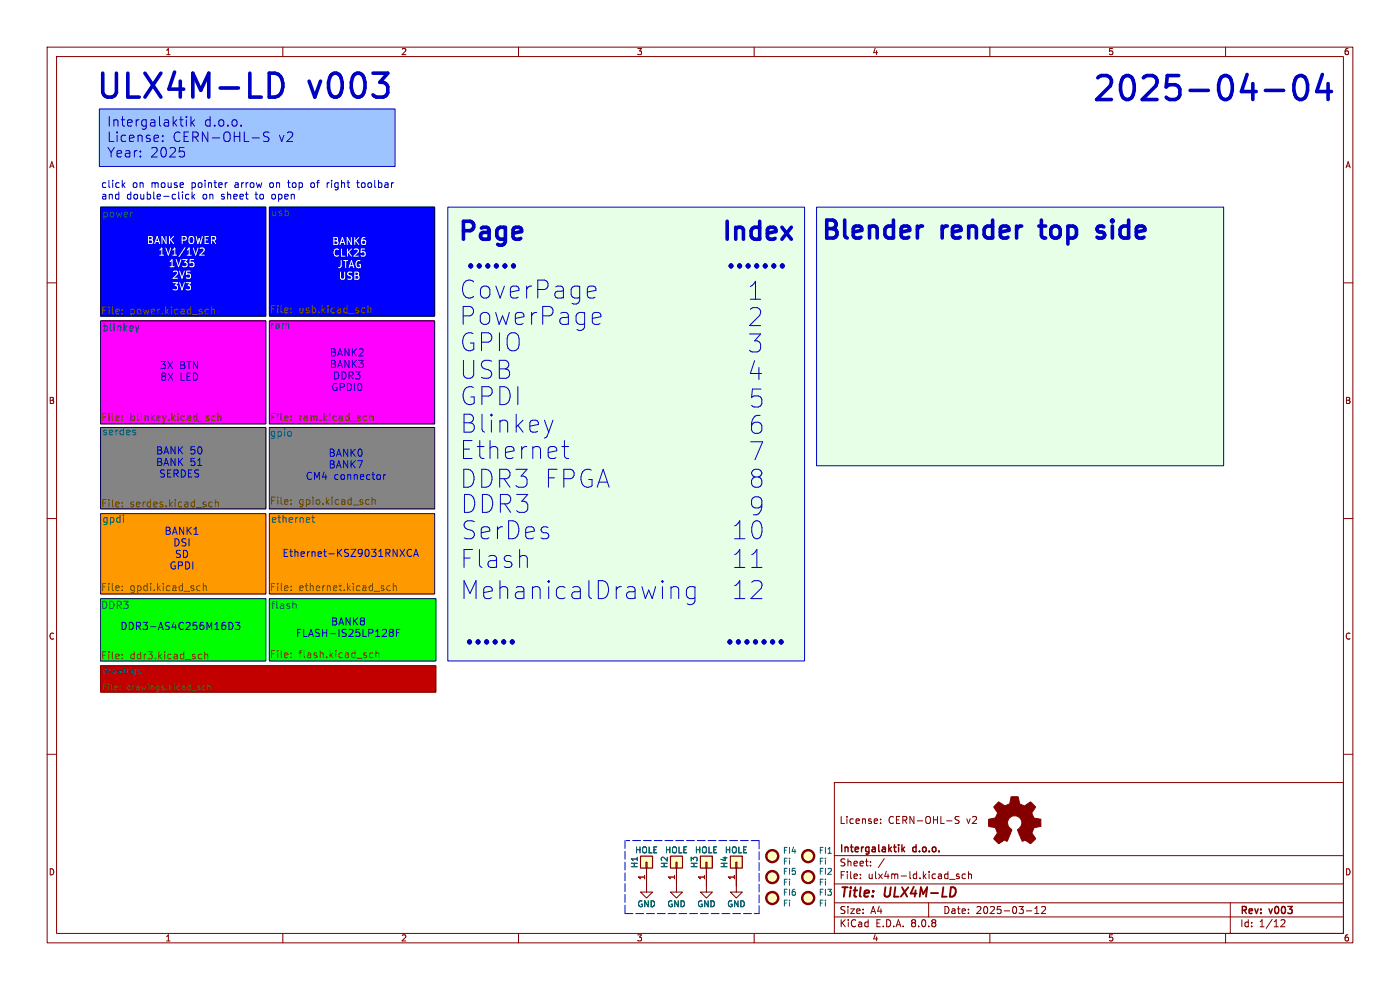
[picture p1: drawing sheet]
<svg xmlns="http://www.w3.org/2000/svg" width="297mm" height="210mm" viewBox="0 0 297 210" stroke-linecap="round" stroke-linejoin="round" font-family="sans-serif">
<defs><g id="words">
<g font-size="7.1" fill="#0000c2">
<text x="20" y="22">ULX4M-LD</text>
<text x="65.5" y="22">v003</text>
<text x="231.3" y="22.5">2025-04-04</text>
</g>
<g font-size="5.3" fill="#0000c2">
<text x="96.6" y="52.1">Page</text>
<text x="166.3" y="52.1">Index</text>
<text x="173.7" y="51.8">Blender</text>
<text x="199.7" y="51.8">render</text>
<text x="222.3" y="51.8">top</text>
<text x="235.8" y="51.8">side</text>
<text x="98.2" y="57.9">......</text>
<text x="153.4" y="57.9">.......</text>
<text x="97.5" y="63.6">CoverPage</text>
<text x="158.6" y="63.9">1</text>
<text x="97.5" y="69.2">PowerPage</text>
<text x="158.6" y="69.4">2</text>
<text x="97.6" y="74.8">GPIO</text>
<text x="158.6" y="75">3</text>
<text x="97.6" y="80.6">USB</text>
<text x="158.6" y="80.9">4</text>
<text x="97.7" y="86.2">GPDI</text>
<text x="158.9" y="86.7">5</text>
<text x="97.7" y="92.1">Blinkey</text>
<text x="158.9" y="92.3">6</text>
<text x="97.6" y="97.6">Ethernet</text>
<text x="158.9" y="97.9">7</text>
<text x="97.6" y="103.7">DDR3 FPGA</text>
<text x="158.9" y="103.7">8</text>
<text x="97.8" y="109.1">DDR3</text>
<text x="158.9" y="109.6">9</text>
<text x="97.9" y="114.7">SerDes</text>
<text x="155.3" y="114.7">10</text>
<text x="97.7" y="120.8">Flash</text>
<text x="155.3" y="120.8">11</text>
<text x="97.7" y="127.4">MehanicalDrawing</text>
<text x="155.3" y="127.4">12</text>
<text x="97.9" y="137.7">......</text>
<text x="153.2" y="137.7">.......</text>
</g>
<g font-size="2.8" fill="#0000c2">
<text x="22.6" y="27.1">Intergalaktik</text>
<text x="43.2" y="27.1">d.o.o.</text>
<text x="22.6" y="30.4">License:</text>
<text x="22.6" y="33.7">Year:</text>
<text x="31.8" y="33.7">2025</text>
<text x="36.5" y="30.4">CERN-OHL-S</text>
<text x="59" y="30.4">v2</text>
</g>
<g font-size="2.8" fill="#840000">
<text x="178" y="190.9">Title:</text>
<text x="187.7" y="190.9">ULX4M-LD</text>
</g>
<g font-size="2.1" fill="#0000c2">
<text x="21.3" y="40">click</text>
<text x="28" y="40">on</text>
<text x="32.1" y="40">mouse</text>
<text x="40.7" y="40">pointer</text>
<text x="50" y="40">arrow</text>
<text x="57.6" y="40">on</text>
<text x="61.7" y="40">top</text>
<text x="66.6" y="40">of</text>
<text x="70.2" y="40">right</text>
<text x="76.8" y="40">toolbar</text>
<text x="21.3" y="42.4">and</text>
<text x="26.8" y="42.4">double-click</text>
<text x="43" y="42.4">on</text>
<text x="47" y="42.4">sheet</text>
<text x="54.5" y="42.4">to</text>
<text x="58" y="42.4">open</text>
<text x="69.9" y="75.8">BANK2</text>
<text x="33.9" y="78.5">3X</text>
<text x="33.9" y="81">8X</text>
<text x="38.1" y="78.5">BTN</text>
<text x="38.1" y="81">LED</text>
<text x="69.9" y="78.3">BANK3</text>
<text x="70.2" y="83.2">GPDI0</text>
<text x="70.6" y="80.7">DDR3</text>
<text x="33" y="96.6">BANK 50</text>
<text x="33" y="99">BANK 51</text>
<text x="33.7" y="101.5">SERDES</text>
<text x="69.6" y="97.1">BANK0</text>
<text x="69.6" y="99.5">BANK7</text>
<text x="64.8" y="102">CM4</text>
<text x="70.8" y="102">connector</text>
<text x="34.8" y="113.6">BANK1</text>
<text x="36.7" y="116.1">DSI</text>
<text x="37" y="118.6">SD</text>
<text x="59.9" y="118.3">Ethernet-KSZ9031RNXCA</text>
<text x="35.9" y="121">GPDI</text>
<text x="25.5" y="133.8">DDR3-AS4C256M16D3</text>
<text x="62.7" y="135.3">FLASH-IS25LP128F</text>
<text x="70.1" y="132.9">BANK8</text>
</g>
<g font-size="2.1" fill="#006464">
<text x="21.6" y="46.2">power</text>
<text x="57.4" y="46">usb</text>
<text x="21.6" y="70.4">blinkey</text>
<text x="57.1" y="69.9">ram</text>
<text x="21.6" y="92.5">serdes</text>
<text x="57.1" y="92.7">gpio</text>
<text x="21.6" y="111">gpdi</text>
<text x="57.4" y="111">ethernet</text>
<text x="21.3" y="129.3">DDR3</text>
<text x="57.4" y="129.3">flash</text>
</g>
<g font-size="2.1" fill="#fff">
<text x="31.1" y="52">BANK POWER</text>
<text x="70.4" y="52.2">BANK6</text>
<text x="33.5" y="54.4">1V1/1V2</text>
<text x="35.7" y="56.9">1V35</text>
<text x="36.4" y="59.3">2V5</text>
<text x="70.5" y="54.6">CLK25</text>
<text x="71.5" y="57.1">JTAG</text>
<text x="71.8" y="59.5">USB</text>
<text x="36.4" y="61.8">3V3</text>
</g>
<g font-size="2.1" fill="#725600">
<text x="21.3" y="67">File:</text>
<text x="27.5" y="67">power.kicad_sch</text>
<text x="57.1" y="66.8">File:</text>
<text x="63.3" y="66.8">usb.kicad_sch</text>
<text x="21.3" y="89.6">File:</text>
<text x="27.5" y="89.6">blinkey.kicad_sch</text>
<text x="57.1" y="89.6">File:</text>
<text x="63.3" y="89.6">ram.kicad_sch</text>
<text x="21.3" y="107.9">File:</text>
<text x="27.5" y="107.9">serdes.kicad_sch</text>
<text x="57.1" y="107.4">File:</text>
<text x="63.3" y="107.4">gpio.kicad_sch</text>
<text x="21.3" y="125.7">File:</text>
<text x="27.5" y="125.7">gpdi.kicad_sch</text>
<text x="57.1" y="125.7">File:</text>
<text x="63.3" y="125.7">ethernet.kicad_sch</text>
<text x="21.3" y="140.2">File:</text>
<text x="27.5" y="140.2">ddr3.kicad_sch</text>
<text x="57.1" y="139.9">File:</text>
<text x="63.3" y="139.9">flash.kicad_sch</text>
</g>
<g font-size="2.1" fill="#840000">
<text x="178" y="175">License:</text>
<text x="188.4" y="175">CERN-OHL-S</text>
<text x="205.1" y="175">v2</text>
<text x="178" y="184">Sheet:</text>
<text x="178" y="181.2">Intergalaktik</text>
<text x="193.7" y="181.2">d.o.o.</text>
<text x="178" y="186.7">File:</text>
<text x="184.1" y="186.7">ulx4m-ld.kicad_sch</text>
<text x="178" y="196.9">KiCad</text>
<text x="178" y="194.1">Size:</text>
<text x="184.7" y="194.1">A4</text>
<text x="185.7" y="196.9">E.D.A.</text>
<text x="193.3" y="196.9">8.0.8</text>
<text x="200" y="194.1">Date:</text>
<text x="207" y="194.1">2025-03-12</text>
<text x="263" y="194.3">Rev:</text>
<text x="263" y="196.9">Id:</text>
<text x="267.1" y="196.9">1/12</text>
<text x="269.4" y="194.3">v003</text>
</g>
<g font-size="1.8" fill="#840000">
<text x="35" y="11.9">1</text>
<text x="85" y="11.9">2</text>
<text x="135" y="11.9">3</text>
<text x="185" y="11.9">4</text>
<text x="235" y="11.9">5</text>
<text x="285" y="11.9">6</text>
<text x="10.3" y="35.9">A</text>
<text x="285.3" y="35.9">A</text>
<text x="10.3" y="85.9">B</text>
<text x="285.3" y="85.9">B</text>
<text x="10.3" y="135.9">C</text>
<text x="285.3" y="135.9">C</text>
<text x="10.3" y="185.9">D</text>
<text x="285.3" y="185.9">D</text>
<text x="35" y="199.9">1</text>
<text x="85" y="199.9">2</text>
<text x="135" y="199.9">3</text>
<text x="185" y="199.9">4</text>
<text x="235" y="199.9">5</text>
<text x="285" y="199.9">6</text>
</g>
<g font-size="1.8" fill="#006464">
<text x="21.6" y="143">drawings</text>
<text x="134.6" y="181.2">HOLE</text>
<text x="135.5" y="184.3" transform="rotate(-90 135.5 184.3)">H1</text>
<text x="141" y="181.2">HOLE</text>
<text x="141.8" y="184.3" transform="rotate(-90 141.8 184.3)">H2</text>
<text x="147.3" y="181.2">HOLE</text>
<text x="148.2" y="184.3" transform="rotate(-90 148.2 184.3)">H3</text>
<text x="153.7" y="181.2">HOLE</text>
<text x="154.5" y="184.3" transform="rotate(-90 154.5 184.3)">H4</text>
<text x="166" y="185.8">FI5</text>
<text x="166" y="181.3">FI4</text>
<text x="166" y="183.6">Fi</text>
<text x="173.6" y="181.3">FI1</text>
<text x="173.6" y="185.8">FI2</text>
<text x="173.6" y="183.6">Fi</text>
<text x="166" y="190.2">FI6</text>
<text x="166" y="188.1">Fi</text>
<text x="173.6" y="190.2">FI3</text>
<text x="173.6" y="188.1">Fi</text>
<text x="135.1" y="192.6">GND</text>
<text x="141.5" y="192.6">GND</text>
<text x="147.8" y="192.6">GND</text>
<text x="154.2" y="192.6">GND</text>
<text x="166" y="192.5">Fi</text>
<text x="173.6" y="192.5">Fi</text>
</g>
<g font-size="1.8" fill="#725600">
<text x="21.6" y="146.8">File:</text>
<text x="26.8" y="146.8">drawings.kicad_sch</text>
</g>
<g font-size="1.8" fill="#a90000">
<text x="136.9" y="186.8" transform="rotate(-90 136.9 186.8)">1</text>
<text x="143.3" y="186.8" transform="rotate(-90 143.3 186.8)">1</text>
<text x="149.6" y="186.8" transform="rotate(-90 149.6 186.8)">1</text>
<text x="156" y="186.8" transform="rotate(-90 156 186.8)">1</text>
</g>
</g></defs>
<g fill="none" stroke="#840000" stroke-width=".21">
<path d="M10 10h277v190h-277zM12 12h273v186h-273zM60 10v2M110 10v2M160 10v2M210 10v2M260 10v2M10 60h2M285 60h2M10 110h2M285 110h2M10 160h2"/>
<path d="M177 166h108v32h-108zM186.8 174.6v.1M186.8 173.8v.1M203.5 173.3l-.6-.1-.2 .1v.5l.6 .3 .2 .3-.3 .3-.6-.1M285 160h2M60 198v2M110 198v2M160 198v2M177 194.5h108M177 191.5h108M177 187.5h108M177 181.5h108"/>
<path d="M182.5 186.3v.1M182.5 185.5v.1M184.7 183.6v.1M184.7 182.8v.1M187.6 182.1l-1.3 2M197 191.5v3M201.5 186.5h1.1M203.5 185.5l-.4-.1-.2 .2 .1 .2 .5 .2v.3h-.6M204.8 185.5l-.4-.1-.3 .3 .1 .6h.6M205.5 185.5l.2-.1 .3 .1 .1 .9M205.5 184.9v1.5M210 198v2"/>
<path d="M217.7 193.2h1.2M219.5 193.8h.9M219.5 192.7l.5-.4v1.5M221 192.4l.5-.1 .3 .4-.9 1.1h.9M260 198v2M261 191.5v6.5M271.7 195.2l.6-.1 .3 .4-.9 1.1h.9"/>
</g>
<path d="M191.3 179.2v1.5M191.9 179.7l-.6 .6M191.5 180.1l.4 .6" fill="none" stroke="#840000" stroke-width=".3"/>
<path d="M21.3 141.2h71.2v5.6h-71.2z" fill="#c20000" stroke="#c20000" stroke-width=".21"/>
<g fill="#f90" stroke="#f90" stroke-width=".21">
<path d="M57.1 109h35.1v17h-35.1z"/>
<path d="M21.3 109h35.1v17h-35.1z"/>
</g>
<g fill="#0f0" stroke="#0f0" stroke-width=".21">
<path d="M57.1 127h35.4v13.2h-35.4z"/>
<path d="M21.3 127h35.1v13.2h-35.1z"/>
</g>
<g fill="#f0f" stroke="#f0f" stroke-width=".21">
<path d="M57.1 68.1h35.1v21.8h-35.1z"/>
<path d="M21.3 68.1h35.1v21.8h-35.1z"/>
</g>
<g fill="#848484" stroke="#848484" stroke-width=".21">
<path d="M57.1 90.7h35.1v17.3h-35.1z"/>
<path d="M21.3 90.7h35.1v17.3h-35.1z"/>
</g>
<g fill="#00f" stroke="#00f" stroke-width=".21">
<path d="M21.3 43.9h35.1v23.2h-35.1z"/>
<path d="M57.1 43.9h35.1v23.2h-35.1z"/>
</g>
<path d="M21.1 23.1h62.7v12.2h-62.7z" fill="#9ec4ff"/>
<g fill="#e6ffe6">
<path d="M173.2 43.9h86.4v54.9h-86.4z"/>
<path d="M95 43.9h75.7v96.3h-75.7z"/>
</g>
<path d="M21.3 141.2h71.2v5.6h-71.2zM156.2 188v1.2h1.3l-1.3 1.3-1.3-1.3h1.3" fill="none" stroke="#840000" stroke-width=".21"/>
<path d="M28 45h.1M28.7 69.1l.4 1.1M29.1 70.2l-.2 .4M29.5 69.1l-.4 1.1M28.6 91.8l.2 .2-.2 .3M28.6 91.2l.1 .1M26.2 109.3v.1M66.1 109.8h.6M66.4 109.3v1.3l.3 .2M62.4 128.1l.4 .2v.8M29.7 142.1l-.3-.1-.2 .2 .1 .2 .4 .1v.3h-.5" fill="none" stroke="#006464" stroke-width=".21"/>
<g fill="none" stroke="#725600" stroke-width=".21">
<path d="M25.9 65.7v.1M25.9 66.5v.1M43.8 65.6l.4 .1M44.2 66.5l-.4 .1M44.9 65.1v1.5M44.9 65.7l.2-.1 .4 .1v.9M61.7 65.4v.2M61.7 66.2v.2M77.3 65.3l.1 .1M77.4 66.3l-.1 .1M78.1 64.8v1.6M78.1 65.5l.2-.2 .4 .1v1"/>
<path d="M25.9 88.3v.1M25.9 89.1v.1M45.6 88.3l-.4-.1-.3 .3 .1 .6h.6M46.3 88.3l.2-.1 .3 .1 .1 .9M46.3 87.7v1.5M61.7 88.3v.1M61.7 89.1v.1M77.4 88.2l.4 .1M77.8 89.1l-.4 .1M78.4 88.3l.3-.1 .3 .1 .1 .9M78.4 87.7v1.5M25.9 106.6v.1"/>
<path d="M25.9 107.4v.1M44.4 107.4h.6M44.4 106.6h.6M45.7 106.6l.2-.1 .4 .1v.9M45.7 106v1.5M61.7 106.1v.1M61.7 106.9v.1M77.9 106l.4 .1M78.3 106.9l-.4 .1M78.9 106.1l.3-.1 .3 .1 .1 .9M78.9 105.5v1.5M25.9 139.6v.2"/>
<path d="M25.9 124.3v.2M25.9 125.1v.2M25.9 138.8v.2M42 124.3h.5M42.3 138.7l.5 .1M42.5 125.2l-.5 .1M42.8 139.7l-.5 .1M43.1 124.4l.3-.1h.3l.1 1M43.1 123.8v1.5M43.4 138.9l.2-.2 .4 .1 .1 1M43.4 138.2v1.6M61.7 125.1v.2"/>
<path d="M61.7 124.3v.2M61.7 138.6v.1M61.7 139.4v.1M78.4 139.2l.3 .3 .4-.1M79.1 138.6l-.4-.1-.3 .3M79.7 138.6l.3-.1 .3 .1 .1 .9M79.7 138v1.5M82.8 124.3h-.4l-.3 .3 .1 .6h.6M83.4 124.4l.3-.1h.3l.1 1M83.4 123.8v1.5M25.4 146.2v.2M25.4 145.6v.1"/>
<path d="M43.5 145.6l-.3-.1-.3 .3 .1 .5h.5M44.1 145.6h.5v.8M44.1 145.1v1.3"/>
</g>
<path d="M21.3 43.9h35.1v23.2h-35.1zM57.1 43.9h35.1v23.2h-35.1zM21.3 68.1h35.1v21.8h-35.1zM57.1 68.1h35.1v21.8h-35.1zM21.3 90.7h35.1v17.3h-35.1zM57.1 90.7h35.1v17.3h-35.1zM21.3 109h35.1v17h-35.1zM57.1 109h35.1v17h-35.1zM21.3 127h35.1v13.2h-35.1zM57.1 127h35.4v13.2h-35.4z" fill="none" stroke="#000" stroke-width=".21"/>
<path d="M135.9 181.6h2.5v2.6h-2.5z" fill="#ffffc2"/>
<path d="M137 182.9h.3v1.3h-.3zM137.2 184.2v3.8" fill="none" stroke="#840000" stroke-width=".21"/>
<path d="M135.9 181.6h2.5v2.6h-2.5z" fill="none" stroke="#840000" stroke-width=".25"/>
<path d="M154.9 181.6h2.6v2.6h-2.6z" fill="#ffffc2"/>
<path d="M156.1 182.9h.2v1.3h-.2zM156.2 184.2v3.8" fill="none" stroke="#840000" stroke-width=".21"/>
<path d="M154.9 181.6h2.6v2.6h-2.6z" fill="none" stroke="#840000" stroke-width=".25"/>
<path d="M148.6 181.6h2.5v2.6h-2.5z" fill="#ffffc2"/>
<path d="M149.7 182.9h.3v1.3h-.3zM149.9 184.2v3.8" fill="none" stroke="#840000" stroke-width=".21"/>
<path d="M148.6 181.6h2.5v2.6h-2.5z" fill="none" stroke="#840000" stroke-width=".25"/>
<path d="M142.2 181.6h2.6v2.6h-2.6z" fill="#ffffc2"/>
<path d="M137.2 184.2v5h1.2l-1.2 1.3-1.3-1.3h1.3M143.4 182.9h.2v1.3h-.2zM143.5 184.2v5h1.3l-1.3 1.3-1.3-1.3h1.3M149.9 184.2v5h1.2l-1.2 1.3-1.3-1.3h1.3M156.2 184.2v3.8" fill="none" stroke="#840000" stroke-width=".21"/>
<path d="M142.2 181.6h2.6v2.6h-2.6z" fill="none" stroke="#840000" stroke-width=".25"/>
<g fill="#ffffc2" stroke="#ffffc2" stroke-width=".21">
<circle cx="163.8" cy="190.5" r="1.27"/>
<circle cx="171.4" cy="181.6" r="1.27"/>
<circle cx="163.8" cy="186.1" r="1.27"/>
<circle cx="171.4" cy="190.5" r="1.27"/>
<circle cx="171.4" cy="186.1" r="1.27"/>
<circle cx="163.8" cy="181.6" r="1.27"/>
</g>
<g fill="none" stroke="#840000" stroke-width=".51">
<circle cx="163.8" cy="186.1" r="1.27"/>
<circle cx="163.8" cy="190.5" r="1.27"/>
<circle cx="163.8" cy="181.6" r="1.27"/>
<circle cx="171.4" cy="186.1" r="1.27"/>
<circle cx="171.4" cy="190.5" r="1.27"/>
<circle cx="171.4" cy="181.6" r="1.27"/>
</g>
<path d="M211.6 170.3l.3-.2 .6 .4a1.06 1.06 0 0 0 1.2 .3 1.06 1.06 0 0 0 .7-1l.2-.8h1.4l.1 .5a1.13 1.13 0 0 0 .7 1.3l.5 .2 1.3-.9 1.1 1-.4 .7a.75 .75 0 0 0-.2 1.2l.2 .5 1.5 .3v1.5l-.7 .1a.8 .8 0 0 0-1 .9l-.2 .4 .1 .2a1.33 1.33 0 0 1 .6 1.2l-1 .9-.8-.6a.61 .61 0 0 0-.9 .1l-1-2.4a1.65 1.65 0 0 0 .8-1.6 1.65 1.65 0 0 0-1-1.4 1.55 1.55 0 0 0-1.9 1 1.55 1.55 0 0 0 .9 1.9l-.9 2.3a.4 .4 0 0 1-.4 .2 .4 .4 0 0 1-.3-.3l-1.2 .8-.6-.6a.6 .6 0 0 1-.5-.5 .6 .6 0 0 1 .4-.6l.4-.6-.2-.5a.71 .71 0 0 0-.9-.8l-.8-.1v-1.5l.5-.1a1.11 1.11 0 0 0 1.2-.7 .75 .75 0 0 0-.2-1.2l-.4-.6z" fill="#840000" stroke="#840000" stroke-width=".21"/>
<g fill="none" stroke="#0000c2" stroke-width=".21">
<path d="M21.1 23.1h62.7v12.2h-62.7zM26.1 39.2l.4 .6M26.5 38.8l-.6 .5M34.5 29.8v.2M34.5 28.8v.2M38.1 25.4h.8M38.7 26.8h.2M38.8 32l.4 .4v.5l-.4 .4M39.5 24.7v.2M39.5 25.4v1.4M40.5 24.7v2.1M40.7 26l.6 .8"/>
<path d="M41.3 25.4l-.8 .8M48.2 38.8h-.3M51.2 26.6v.2M53.5 29.3h1.5M57.1 28.1l-.8-.1-.4 .4 .2 .5 .9 .4v.5l-.3 .2-.8-.1M66 38.9v.7M69.4 38.8v1M69.7 38.8l-.3 .2M75.6 38.8h.6M75.9 38.2v1.4l.2 .2M38.7 40.7v.1M40.1 41.3l-.4-.1-.3 .3 .1 .7h.6"/>
<path d="M40.7 40.7v1.5M40.9 41.6l.4 .6M41.3 41.2l-.6 .6M95 43.9h75.7v96.3h-75.7zM173.2 43.9h86.4v54.9h-86.4zM125.1 60.7h.8l.3 .2 .2 .7-1.8 .4M126.2 66.3h.7l.4 .2 .2 .7-1.8 .3M126.2 63l-.3 .2h-.8M127.3 68.6l-.4 .2h-.7M117.3 89.1l-.9 2.6M119.2 94.7h1.4M119.7 93.5v3.2l.2 .4 .7 .2"/>
<path d="M81.4 100.7v1M81.8 100.7l-.4 .3M84.8 116.5l1.1 1.5M85.9 116.5l-1.1 1.5M87.3 116.7a.72 .72 0 0 0-1 .5 .72 .72 0 0 0 .7 .8l.3-.1M87.7 118l.5-1.5 .6 1.5M87.9 117.6h.7M48.6 132a.77 .77 0 0 1 .8 .8 .77 .77 0 0 1-.8 .7zM49.9 132h1l-.5 .6 .4 .1v.7l-.2 .1-.7-.1M82.7 134l.2 .2M82.7 133.6l.2-.1 .4 .1 .2 .3-.3 .3M82.9 134.2h.3"/>
<path d="M82.9 134.2l-.2 .1M83.2 134.2l.3 .2-.1 .5-.2 .1-.5-.1M84.1 134.2h.5M84.8 133.5h-.7v1.5M142.5 124.6l.4-.2h.5l.4 .2 .2 .4v2M147.4 124.6l-.3-.2h-.8l-.5 .4-.2 .4v1.1l.4 .5 .3 .2h.8l.3-.2M147.4 124.4v3.1a1.03 1.03 0 0 1-1.6 .6"/>
</g>
<g fill="none" stroke="#0000c2" stroke-width=".76">
<path d="M57.1 15.5h1.2a2.32 2.32 0 0 1 1.7 2.9 2.22 2.22 0 0 1-2.9 2.2M268.4 19.2h3.9M275.2 16.3a1.21 1.21 0 0 1 2 .7 4 4 0 0 1-.5 3.9 1.21 1.21 0 0 1-2-.8 4 4 0 0 1 .5-3.8zM280.5 15.8l-1.2 3.6h3.2M281.7 17.7v3.4M108.9 56.2l.2 .2-.2 .2M108.9 56.2l-.2 .2 .2 .2M108.9 56.2v.4M154.3 46.9v3.8M156.1 48.2v2.5M156.1 48.6a.95 .95 0 0 1 1.6 .2v1.9M161.2 48.4l-.4-.2h-.7l-.6 .4-.2 .3v1.1l.4 .6 .4 .1h.7l.4-.1"/>
<path d="M161.2 46.9v3.8M162.8 49.5l1.8-.4-.2-.7-.3-.2h-.8l-.3 .2-.2 .4v1.4l.2 .4 .3 .1h.8l.3-.1M166 56.2l.2 .2-.2 .2M166 56.2l-.2 .2 .2 .2M166 56.2v.4M195.7 48l-.7 .1M220.4 48h1.4M232.7 50.3l.4 .2h.7l.4-.2M234.2 48.1l-.4-.1h-.5l-.4 .1-.2 .4 .2 .5 1.3 .4M108.7 136l.2 .2-.2 .1M108.7 136l-.2 .2 .2 .1M108.7 136v.3"/>
<path d="M165.7 136l.2 .2-.2 .1M165.7 136l-.2 .2 .2 .1M165.7 136v.3"/>
</g>
<path d="M42.5 52.7h.1M43.2 52.7l.1 .2v.4l-.9 .8h.9" fill="none" stroke="#fff" stroke-width=".21"/>
<path d="M132.6 178.3v15.5M161 178.3h-28.2M132.6 193.8h28.4M161 193.8v-15.5" fill="none" stroke="#0000c2" stroke-width=".21" stroke-dasharray="1.7 .6"/>
<use href="#words"/>
</svg>
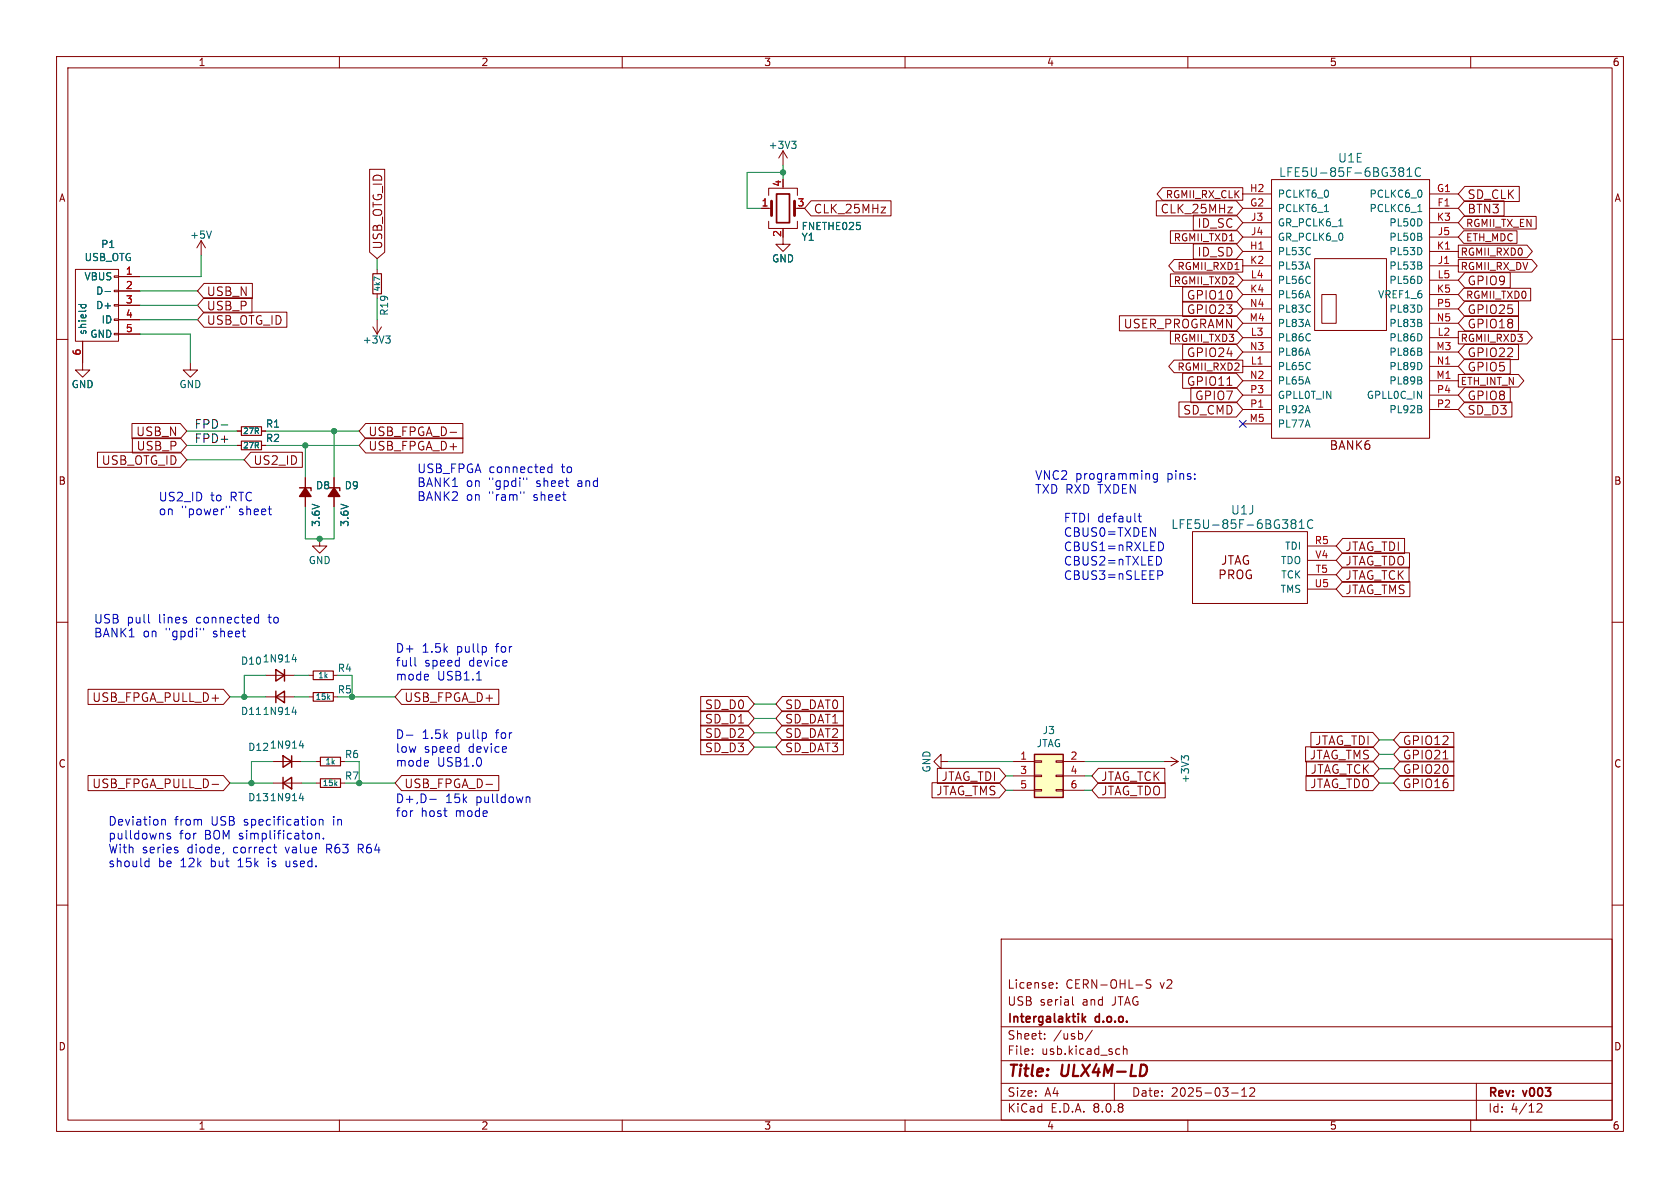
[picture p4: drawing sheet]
<svg xmlns="http://www.w3.org/2000/svg" width="297mm" height="210mm" viewBox="0 0 297 210" stroke-linecap="round" stroke-linejoin="round" font-family="sans-serif">
<defs><g id="words">
<g font-size="2.8" fill="#840000">
<text x="178" y="190.9">Title:</text>
<text x="187.7" y="190.9">ULX4M-LD</text>
</g>
<g font-size="2.1" fill="#006464">
<text x="236.5" y="28.9">U1E</text>
<text x="226" y="31.5">LFE5U-85F-6BG381C</text>
<text x="207" y="93.7">LFE5U-85F-6BG381C</text>
<text x="217.5" y="91.2">U1J</text>
</g>
<g font-size="2.1" fill="#840000">
<text x="259.3" y="35.4">SD_CLK</text>
<text x="143.8" y="37.9">CLK_25MHz</text>
<text x="205.1" y="37.9">CLK_25MHz</text>
<text x="211.6" y="40.5">ID_SC</text>
<text x="259.3" y="37.9">BTN3</text>
<text x="67.8" y="44.2" transform="rotate(-90 67.8 44.2)">USB_OTG_ID</text>
<text x="211.6" y="45.5">ID_SD</text>
<text x="36.4" y="52.5">USB_N</text>
<text x="209.8" y="53.2">GPIO10</text>
<text x="259.3" y="50.6">GPIO9</text>
<text x="36.4" y="57.6">USB_OTG_ID</text>
<text x="36.4" y="55.1">USB_P</text>
<text x="198.6" y="58.2">USER_PROGRAMN</text>
<text x="209.8" y="55.7">GPIO23</text>
<text x="259.3" y="58.2">GPIO18</text>
<text x="259.3" y="55.7">GPIO25</text>
<text x="209.8" y="63.3">GPIO24</text>
<text x="259.3" y="65.9">GPIO5</text>
<text x="259.3" y="63.3">GPIO22</text>
<text x="209.8" y="68.4">GPIO11</text>
<text x="211.2" y="70.9">GPIO7</text>
<text x="259.3" y="70.9">GPIO8</text>
<text x="24" y="77.3">USB_N</text>
<text x="65" y="77.3">USB_FPGA_D-</text>
<text x="209.1" y="73.5">SD_CMD</text>
<text x="259.3" y="73.5">SD_D3</text>
<text x="17.9" y="82.4">USB_OTG_ID</text>
<text x="24.1" y="79.8">USB_P</text>
<text x="44.7" y="82.4">US2_ID</text>
<text x="65" y="79.8">USB_FPGA_D+</text>
<text x="234.9" y="79.8">BANK6</text>
<text x="215.7" y="100.1">JTAG</text>
<text x="237.7" y="100.2">JTAG_TDO</text>
<text x="237.7" y="97.6">JTAG_TDI</text>
<text x="215.2" y="102.6">PROG</text>
<text x="237.7" y="102.7">JTAG_TCK</text>
<text x="237.7" y="105.2">JTAG_TMS</text>
<text x="16.2" y="124.3">USB_FPGA_PULL_D+</text>
<text x="71.4" y="124.3">USB_FPGA_D+</text>
<text x="124.6" y="125.6">SD_D0</text>
<text x="138.7" y="125.6">SD_DAT0</text>
<text x="124.6" y="130.6">SD_D2</text>
<text x="124.6" y="128.1">SD_D1</text>
<text x="138.7" y="130.6">SD_DAT2</text>
<text x="138.7" y="128.1">SD_DAT1</text>
<text x="232.4" y="131.9">JTAG_TDI</text>
<text x="247.9" y="131.9">GPIO12</text>
<text x="124.6" y="133.2">SD_D3</text>
<text x="138.7" y="133.2">SD_DAT3</text>
<text x="231.5" y="134.4">JTAG_TMS</text>
<text x="231.6" y="137">JTAG_TCK</text>
<text x="247.9" y="137">GPIO20</text>
<text x="247.9" y="134.4">GPIO21</text>
<text x="16.2" y="139.5">USB_FPGA_PULL_D-</text>
<text x="71.4" y="139.5">USB_FPGA_D-</text>
<text x="165.5" y="140.8">JTAG_TMS</text>
<text x="166.4" y="138.3">JTAG_TDI</text>
<text x="194.6" y="138.3">JTAG_TCK</text>
<text x="194.6" y="140.8">JTAG_TDO</text>
<text x="231.6" y="139.5">JTAG_TDO</text>
<text x="247.9" y="139.5">GPIO16</text>
<text x="178" y="178">USB</text>
<text x="178" y="175">License:</text>
<text x="183.8" y="178">serial</text>
<text x="188.4" y="175">CERN-OHL-S</text>
<text x="191.4" y="178">and</text>
<text x="196.8" y="178">JTAG</text>
<text x="205.1" y="175">v2</text>
<text x="178" y="184">Sheet:</text>
<text x="178" y="181.2">Intergalaktik</text>
<text x="186.2" y="184">/usb/</text>
<text x="193.7" y="181.2">d.o.o.</text>
<text x="178" y="186.7">File:</text>
<text x="184.1" y="186.7">usb.kicad_sch</text>
<text x="178" y="196.9">KiCad</text>
<text x="178" y="194.1">Size:</text>
<text x="184.7" y="194.1">A4</text>
<text x="185.7" y="196.9">E.D.A.</text>
<text x="193.3" y="196.9">8.0.8</text>
<text x="200" y="194.1">Date:</text>
<text x="207" y="194.1">2025-03-12</text>
<text x="263" y="194.3">Rev:</text>
<text x="263" y="196.9">Id:</text>
<text x="267.1" y="196.9">4/12</text>
<text x="269.4" y="194.3">v003</text>
</g>
<g font-size="2.1" fill="#0f0f0f">
<text x="34.3" y="75.9">FPD-</text>
<text x="34.3" y="78.4">FPD+</text>
</g>
<g font-size="2.1" fill="#0000c2">
<text x="73.7" y="83.7">USB_FPGA connected</text>
<text x="99.3" y="83.7">to</text>
<text x="27.9" y="88.7">US2_ID</text>
<text x="37.2" y="88.7">to</text>
<text x="40.7" y="88.7">RTC</text>
<text x="73.7" y="86.2">BANK1</text>
<text x="73.7" y="88.7">BANK2</text>
<text x="82.4" y="86.2">on</text>
<text x="82.4" y="88.7">on</text>
<text x="86.4" y="86.2">&quot;gpdi&quot;</text>
<text x="86.4" y="88.7">&quot;ram&quot;</text>
<text x="94.4" y="88.7">sheet</text>
<text x="94.9" y="86.2">sheet</text>
<text x="102.4" y="86.2">and</text>
<text x="182.9" y="84.9">VNC2</text>
<text x="182.9" y="87.4">TXD RXD TXDEN</text>
<text x="190.1" y="84.9">programming</text>
<text x="206.3" y="84.9">pins:</text>
<text x="27.9" y="91.2">on</text>
<text x="32" y="91.2">&quot;power&quot;</text>
<text x="42.3" y="91.2">sheet</text>
<text x="188" y="95">CBUS0=TXDEN</text>
<text x="188" y="92.5">FTDI default</text>
<text x="188" y="97.5">CBUS1=nRXLED</text>
<text x="188" y="100.1">CBUS2=nTXLED</text>
<text x="188" y="102.6">CBUS3=nSLEEP</text>
<text x="16.5" y="110.3">USB</text>
<text x="16.5" y="112.8">BANK1</text>
<text x="22.4" y="110.3">pull</text>
<text x="25.2" y="112.8">on</text>
<text x="28.1" y="110.3">lines</text>
<text x="29.3" y="112.8">&quot;gpdi&quot;</text>
<text x="34.8" y="110.3">connected</text>
<text x="37.8" y="112.8">sheet</text>
<text x="47.7" y="110.3">to</text>
<text x="69.8" y="115.5">D+</text>
<text x="69.8" y="117.9">full</text>
<text x="74.6" y="115.5">1.5k</text>
<text x="75" y="117.9">speed</text>
<text x="80.8" y="115.5">pullp</text>
<text x="82.9" y="117.9">device</text>
<text x="87.8" y="115.5">for</text>
<text x="69.8" y="120.4">mode</text>
<text x="77.3" y="120.4">USB1.1</text>
<text x="69.8" y="130.7">D-</text>
<text x="74.6" y="130.7">1.5k</text>
<text x="80.8" y="130.7">pullp</text>
<text x="87.8" y="130.7">for</text>
<text x="69.8" y="133.2">low</text>
<text x="69.8" y="135.6">mode</text>
<text x="74.9" y="133.2">speed</text>
<text x="77.3" y="135.6">USB1.0</text>
<text x="82.9" y="133.2">device</text>
<text x="69.8" y="142.1">D+,D-</text>
<text x="78.7" y="142.1">15k</text>
<text x="84.2" y="142.1">pulldown</text>
<text x="19" y="146.1">Deviation</text>
<text x="19" y="148.5">pulldowns</text>
<text x="30.8" y="146.1">from</text>
<text x="31.7" y="148.5">for</text>
<text x="36.2" y="148.5">BOM simplificaton.</text>
<text x="37.4" y="146.1">USB</text>
<text x="43.2" y="146.1">specification</text>
<text x="59.1" y="146.1">in</text>
<text x="69.8" y="144.5">for</text>
<text x="74.4" y="144.5">host</text>
<text x="80.5" y="144.5">mode</text>
<text x="19" y="151">With</text>
<text x="19" y="153.4">should</text>
<text x="25.1" y="151">series</text>
<text x="27.9" y="153.4">be</text>
<text x="31.9" y="153.4">12k</text>
<text x="33.1" y="151">diode,</text>
<text x="37.4" y="153.4">but</text>
<text x="41.4" y="151">correct</text>
<text x="42.3" y="153.4">15k</text>
<text x="47.8" y="153.4">is</text>
<text x="50.7" y="151">value</text>
<text x="51" y="153.4">used.</text>
<text x="58.1" y="151">R63</text>
<text x="63.8" y="151">R64</text>
</g>
<g font-size="1.8" fill="#840000">
<text x="35" y="11.9">1</text>
<text x="85" y="11.9">2</text>
<text x="135" y="11.9">3</text>
<text x="185" y="11.9">4</text>
<text x="235" y="11.9">5</text>
<text x="285" y="11.9">6</text>
<text x="10.3" y="35.9">A</text>
<text x="206" y="35.2">RGMII_RX_CLK</text>
<text x="285.3" y="35.9">A</text>
<text x="259.1" y="40.3">RGMII_TX_EN</text>
<text x="207.4" y="42.9">RGMII_TXD1</text>
<text x="208.1" y="47.9">RGMII_RXD1</text>
<text x="258.1" y="47.9">RGMII_RX_DV</text>
<text x="258.1" y="45.4">RGMII_RXD0</text>
<text x="259.1" y="42.9">ETH_MDC</text>
<text x="207.4" y="50.5">RGMII_TXD2</text>
<text x="259.1" y="53">RGMII_TXD0</text>
<text x="207.4" y="60.6">RGMII_TXD3</text>
<text x="208.1" y="65.7">RGMII_RXD2</text>
<text x="258.1" y="60.6">RGMII_RXD3</text>
<text x="258.1" y="68.3">ETH_INT_N</text>
<text x="10.3" y="85.9">B</text>
<text x="285.3" y="85.9">B</text>
<text x="10.3" y="135.9">C</text>
<text x="285.3" y="135.9">C</text>
<text x="10.3" y="185.9">D</text>
<text x="285.3" y="185.9">D</text>
<text x="35" y="199.9">1</text>
<text x="85" y="199.9">2</text>
<text x="135" y="199.9">3</text>
<text x="185" y="199.9">4</text>
<text x="235" y="199.9">5</text>
<text x="285" y="199.9">6</text>
</g>
<g font-size="1.8" fill="#006464">
<text x="135.8" y="26.5">+3V3</text>
<text x="225.8" y="35.2">PCLKT6_0</text>
<text x="242" y="35.2">PCLKC6_0</text>
<text x="141.6" y="40.9">FNETHE025</text>
<text x="225.8" y="37.7">PCLKT6_1</text>
<text x="225.8" y="40.2">GR_PCLK6_1</text>
<text x="242" y="37.7">PCLKC6_1</text>
<text x="245.5" y="40.2">PL50D</text>
<text x="14.9" y="46.4">USB_OTG</text>
<text x="17.8" y="44">P1</text>
<text x="33.5" y="42.4">+5V</text>
<text x="136.4" y="46.6">GND</text>
<text x="141.6" y="42.8">Y1</text>
<text x="225.8" y="45.3">PL53C</text>
<text x="225.8" y="42.8">GR_PCLK6_0</text>
<text x="225.8" y="47.9">PL53A</text>
<text x="245.5" y="47.9">PL53B</text>
<text x="245.5" y="42.8">PL50B</text>
<text x="245.5" y="45.3">PL53D</text>
<text x="14.8" y="49.8">VBUS</text>
<text x="16.9" y="52.3">D-</text>
<text x="225.8" y="52.9">PL56A</text>
<text x="225.8" y="50.4">PL56C</text>
<text x="243.5" y="52.9">VREF1_6</text>
<text x="245.5" y="50.4">PL56D</text>
<text x="15.5" y="59.3" transform="rotate(-90 15.5 59.3)">shield</text>
<text x="15.9" y="59.9">GND</text>
<text x="16.9" y="54.8">D+</text>
<text x="17.9" y="57.4">ID</text>
<text x="68.8" y="55.9" transform="rotate(-90 68.8 55.9)">R19</text>
<text x="225.8" y="58">PL83A</text>
<text x="225.8" y="55.5">PL83C</text>
<text x="245.5" y="58">PL83B</text>
<text x="245.5" y="55.5">PL83D</text>
<text x="64" y="60.9">+3V3</text>
<text x="225.8" y="65.6">PL65C</text>
<text x="225.8" y="60.6">PL86C</text>
<text x="225.8" y="63.1">PL86A</text>
<text x="245.5" y="60.6">PL86D</text>
<text x="245.5" y="63.1">PL86B</text>
<text x="245.5" y="65.6">PL89D</text>
<text x="12.6" y="68.8">GND</text>
<text x="31.6" y="68.8">GND</text>
<text x="225.8" y="68.2">PL65A</text>
<text x="225.8" y="70.7">GPLL0T_IN</text>
<text x="241.5" y="70.7">GPLL0C_IN</text>
<text x="245.5" y="68.2">PL89B</text>
<text x="46.9" y="75.8">R1</text>
<text x="225.8" y="75.8">PL77A</text>
<text x="225.8" y="73.3">PL92A</text>
<text x="245.5" y="73.3">PL92B</text>
<text x="46.9" y="78.3">R2</text>
<text x="55.8" y="86.7">D8</text>
<text x="60.8" y="86.7">D9</text>
<text x="56.7" y="93.2" transform="rotate(-90 56.7 93.2)">3.6V</text>
<text x="61.8" y="93.2" transform="rotate(-90 61.8 93.2)">3.6V</text>
<text x="54.5" y="99.9">GND</text>
<text x="226.4" y="99.9">TDO</text>
<text x="227.1" y="97.4">TDI</text>
<text x="226.3" y="105">TMS</text>
<text x="226.4" y="102.5">TCK</text>
<text x="42.5" y="117.7">D10</text>
<text x="46.3" y="117.3">1N914</text>
<text x="42.5" y="126.6">D11</text>
<text x="46.3" y="126.6">1N914</text>
<text x="184.2" y="130">J3</text>
<text x="43.8" y="132.9">D12</text>
<text x="47.6" y="132.5">1N914</text>
<text x="164.7" y="136.7" transform="rotate(-90 164.7 136.7)">GND</text>
<text x="183.2" y="132.3">JTAG</text>
<text x="43.8" y="141.8">D13</text>
<text x="47.6" y="141.8">1N914</text>
<text x="210.4" y="138.5" transform="rotate(-90 210.4 138.5)">+3V3</text>
</g>
<g font-size="1.8" fill="#a90000">
<text x="138.2" y="33.1" transform="rotate(-90 138.2 33.1)">4</text>
<text x="220.9" y="34">H2</text>
<text x="253.9" y="34">G1</text>
<text x="134.5" y="36.6">1</text>
<text x="138.2" y="42" transform="rotate(-90 138.2 42)">2</text>
<text x="140.9" y="36.6">3</text>
<text x="220.9" y="36.6">G2</text>
<text x="221.1" y="39.1">J3</text>
<text x="221.1" y="41.7">J4</text>
<text x="253.9" y="39.1">K3</text>
<text x="254" y="36.6">F1</text>
<text x="254.1" y="41.7">J5</text>
<text x="220.9" y="44.2">H1</text>
<text x="220.9" y="46.7">K2</text>
<text x="253.9" y="44.2">K1</text>
<text x="254.1" y="46.7">J1</text>
<text x="22.2" y="48.6">1</text>
<text x="22.2" y="51.2">2</text>
<text x="22.2" y="53.7">3</text>
<text x="220.9" y="51.8">K4</text>
<text x="221" y="49.3">L4</text>
<text x="253.9" y="51.8">K5</text>
<text x="254" y="49.3">L5</text>
<text x="22.2" y="56.3">4</text>
<text x="22.2" y="58.8">5</text>
<text x="220.8" y="56.9">M4</text>
<text x="220.9" y="54.4">N4</text>
<text x="221" y="59.4">L3</text>
<text x="253.9" y="56.9">N5</text>
<text x="253.9" y="54.4">P5</text>
<text x="254" y="59.4">L2</text>
<text x="14.4" y="62.9" transform="rotate(-90 14.4 62.9)">6</text>
<text x="220.9" y="62">N3</text>
<text x="221" y="64.5">L1</text>
<text x="253.8" y="62">M3</text>
<text x="253.9" y="64.5">N1</text>
<text x="220.9" y="67.1">N2</text>
<text x="220.9" y="69.6">P3</text>
<text x="253.8" y="67.1">M1</text>
<text x="253.9" y="69.6">P4</text>
<text x="220.8" y="74.7">M5</text>
<text x="220.9" y="72.1">P1</text>
<text x="253.9" y="72.1">P2</text>
<text x="232.3" y="96.3">R5</text>
<text x="232.4" y="98.8">V4</text>
<text x="232.5" y="101.3">T5</text>
<text x="232.3" y="103.9">U5</text>
<text x="180.3" y="134.4">1</text>
<text x="180.3" y="136.9">3</text>
<text x="189.2" y="134.4">2</text>
<text x="189.2" y="136.9">4</text>
<text x="180.3" y="139.4">5</text>
<text x="189.2" y="139.4">6</text>
</g>
<g font-size="1.8" fill="#009600">
<text x="59.6" y="119">R4</text>
<text x="59.6" y="122.8">R5</text>
<text x="60.9" y="134.2">R6</text>
<text x="60.9" y="138">R7</text>
</g>
<g font-size="1.4" fill="#006464">
<text x="67.4" y="51.6" transform="rotate(-90 67.4 51.6)">4k7</text>
<text x="42.9" y="76.9">27R</text>
<text x="42.9" y="79.5">27R</text>
<text x="55.7" y="123.9">15k</text>
<text x="56.1" y="120.1">1k</text>
<text x="57.4" y="135.3">1k</text>
<text x="56.9" y="139.2">15k</text>
</g>
</g></defs>
<g fill="none" stroke="#840000" stroke-width=".18">
<path d="M10 10h277v190h-277zM12 12h273v186h-273zM60 10v2M110 10v2M160 10v2M210 10v2M260 10v2M134.6 36.8h1.8M135.9 34.5v-1.2h5.1v1.2M135.9 39.1v1.3h5.1v-1.3M138.4 26.7v2.5M138.4 26.7l-.7 1.2"/>
<path d="M138.4 26.7l.8 1.2M219.7 36.8h5.1M219.7 34.3h5.1M219.7 39.4h5.1M224.8 31.8h27.9v45.7h-27.9zM252.7 36.8h5.1M252.7 34.3h5.1M252.7 39.4h5.1M13.3 47.6h7.7v12.7h-7.7zM20.2 48.8h.8v.2h-.8zM20.2 51.3h.8v.3h-.8zM20.2 53.8h.8v.3h-.8z"/>
<path d="M20.2 56.4h.8v.2h-.8zM20.2 58.9h.8v.3h-.8zM21 48.9h3.8M21 51.4h3.8M21 54h3.8M21 56.5h3.8M21 59.1h3.8M35.6 42.5l.7 1.3M35.6 42.5v2.6M35.6 42.5l-.8 1.3M65.9 57.8l.8 1.3M66.7 47.6v.8"/>
<path d="M66.7 51.9v.8M66.7 56.5v2.6M67.4 57.8l-.7 1.3M138.4 40.4v.2M219.7 44.5h5.1M219.7 47h5.1M219.7 41.9h5.1M219.7 52.1h5.1M219.7 59.7h5.1M219.7 49.5h5.1M219.7 57.2h5.1M219.7 54.6h5.1"/>
<path d="M232.4 45.7h12.7v12.7h-12.7zM233.7 52.1h2.5v5.1h-2.5zM252.7 44.5h5.1M252.7 47h5.1M252.7 41.9h5.1M252.7 52.1h5.1M252.7 59.7h5.1M252.7 49.5h5.1M252.7 57.2h5.1M252.7 54.6h5.1M10 60h2M14.6 60.3v5.1h1.3l-1.3 1.3-1.3-1.3h1.3"/>
<path d="M33.7 64.1v1.3h1.2l-1.2 1.3-1.3-1.3h1.3M41.9 78.7h.8M41.9 76.2h.8M46.2 78.7h.8M46.2 76.2h.8M219.7 64.8h5.1M219.7 67.3h5.1M219.7 62.2h5.1M219.7 74.9h5.1M219.7 72.4h5.1M219.7 69.9h5.1M252.7 64.8h5.1"/>
<path d="M252.7 67.3h5.1M252.7 62.2h5.1M252.7 72.4h5.1M252.7 69.9h5.1M285 60h2M54 84.5v5M59.1 84.5v5M210.8 94h20.3v12.7h-20.3zM231.1 96.5h5.1M231.1 99.1h5.1M10 110h2M47 119.4h5.1"/>
<path d="M54.6 119.4h.8M58.9 119.4h.8M231.1 101.6h5.1M231.1 104.1h5.1M285 110h2M47 123.2h5.1M48.3 138.4h5M54.6 123.2h.8M55.9 138.4h.7M55.9 134.6h.7M58.9 123.2h.8M60.2 138.4h.8"/>
<path d="M60.2 134.6h.8M205.7 134.6h2.6M207 133.9l1.3 .7M208.3 134.6l-1.3 .8M10 160h2M177 166h108v32h-108zM186.8 174.6v.1M186.8 173.8v.1M189.6 176.2v1.3l.2 .2M203.5 173.3l-.6-.1-.2 .1v.5l.6 .3 .2 .3-.3 .3-.6-.1M285 160h2M60 198v2"/>
<path d="M110 198v2M160 198v2M177 194.5h108M177 191.5h108M177 187.5h108M177 181.5h108M182.5 186.3v.1M182.5 185.5v.1M184.7 183.6v.1M184.7 182.8v.1M193.1 182.1l-1.3 2M197 191.5v3"/>
<path d="M197.8 185.4l.2 .1M198 186.3l-.2 .1M198.6 184.9v1.5M198.6 185.5l.2-.1 .4 .1v.9M210 198v2M217.7 193.2h1.2M219.5 193.8h.9M219.5 192.7l.5-.4v1.5M221 192.4l.5-.1 .2 .1 .1 .3-.9 1.1h.9M260 198v2M261 191.5v6.5M271.7 195.2l.6-.1 .2 .1 .1 .3-.9 1.1h.9"/>
</g>
<path d="M137.3 34.3h2.3v5.1h-2.3zM191.3 179.2v1.5M191.9 179.7l-.6 .6M191.5 180.1l.4 .6" fill="none" stroke="#840000" stroke-width=".3"/>
<path d="M53 86.2h2v.5M58 86.2h2.1v.5M48.8 118.4l1.5 1-1.5 1zM50.3 118.4v2M48.8 123.2l1.5-1v2zM48.8 122.2v2M50 138.4l1.6-1v2zM50 137.4v2" fill="none" stroke="#840000" stroke-width=".25"/>
<g fill="none" stroke="#006464" stroke-width=".18">
<path d="M139.9 25h.8l-.4 .4M140.5 25.4l.2 .3v.3l-.2 .2M234.1 37.4h.8M236.7 39.9h.7M247.6 29.7h.3l.3 .2-.3 .4M247.6 30.3h.3M247.9 30.3l.2 .2 .1 .4-.2 .2-.4 .1M248.7 31.2h.9M248.7 30.1l.5-.4v1.5M250.6 37.4h.8M251.1 29.8a.61 .61 0 0 0-.7 0 .61 .61 0 0 0-.2 .7 .57 .57 0 0 0 .3 .6 .57 .57 0 0 0 .6-.1M13.9 53.8h1.3"/>
<path d="M14.4 53.8l-.1 .4M15.1 53.8l.1 .4M18.6 51.5h.9M37.4 40.8l-.4 1.3M67.1 49.4l-1-.4v.6M68.2 59.4h.8l-.5 .5M68.7 59.9l.3 .2v.3l-.3 .3M228.5 91.9h.3l.3 .3-.3 .3M228.5 92.5h.3M228.8 92.5l.2 .2 .1 .4-.1 .2-.5 .1M229.7 93.4h.9M229.7 92.3l.4-.4v1.5"/>
<path d="M232.1 92a.61 .61 0 0 0-.8 0 .61 .61 0 0 0-.2 .8 .57 .57 0 0 0 .3 .5 .57 .57 0 0 0 .7 0M51.6 116.6h.8M52.3 116.2v.8M45.3 126.3h.8M51.6 125.9h.8M52.3 125.5v.8M209.3 134l-.4-.4v.8M209.3 133.8l.3-.2h.3l.2 .2M52.9 141.1h.8M53.5 140.7v.8"/>
</g>
<path d="M65.9 48.4h1.5v3.5h-1.5zM42.7 78h3.5v1.5h-3.5zM42.7 75.4h3.5v1.6h-3.5zM55.4 118.6h3.5v1.5h-3.5zM55.4 122.4h3.5v1.6h-3.5zM56.6 137.7h3.6v1.5h-3.6zM56.6 133.9h3.6v1.5h-3.6z" fill="none" stroke="#840000" stroke-width=".2"/>
<g fill="#840000" stroke="#840000" stroke-width=".25">
<path d="M54 86.2l1 1.6h-2z"/>
<path d="M59.1 86.2l1 1.6h-2.1z"/>
</g>
<path d="M136.4 35.6v2.5M140.5 35.6v2.5" fill="none" stroke="#840000" stroke-width=".51"/>
<path d="M182.9 133.4h5.1v7.6h-5.1z" fill="#ffffc2"/>
<g fill="none" stroke="#840000" stroke-width=".18">
<path d="M65.3 29.9h2.7v14.7l-1.3 1.1-1.4-1.1zM134.6 36.8h1.3M143.4 35.5h14.1v2.7h-14.1l-1.2-1.4zM155.8 36.6h.8l-.8 1h.8M204.4 35.5h14.2l1.1 1.3-1.1 1.4h-14.2zM205.5 33.2h14.2v2.2h-14.2l-.9-1.1zM211 38h7.6l1.1 1.4-1.1 1.3h-7.6zM217.1 36.6h.8l-.8 1h.8M258.8 38.3h12.8v2.2h-12.8l-1-1.1zM259 33h9.6v2.6h-9.6l-1.2-1.3zM259 35.5h6.9v2.7h-6.9l-1.2-1.4zM21 48.9h3.8"/>
<path d="M21 51.4h3.8M21 54h3.8M21 56.5h3.8M21 59.1h3.8M36.1 50.1h8.5v2.7h-8.5l-1.2-1.4zM36.1 55.2h14.6v2.6h-14.6l-1.2-1.3zM36.1 52.6h8.4v2.7h-8.4l-1.2-1.3zM138.4 41.9v1.3h1.3l-1.3 1.3-1.2-1.3h1.2M197.9 55.8h20.7l1.1 1.4-1.1 1.3h-20.7zM206.9 40.8h11.9l.9 1.1-.9 1.1h-11.9zM206.9 48.4h11.9l.9 1.1-.9 1.1h-11.9zM206.9 58.6h11.9l.9 1.1-.9 1.1h-11.9z"/>
<path d="M207.6 45.9h12.1v2.2h-12.1l-1-1.1zM209.1 53.3h9.5l1.1 1.3-1.1 1.3h-9.5zM209.1 50.7h9.5l1.1 1.4-1.1 1.3h-9.5zM211 43.1h7.6l1.1 1.4-1.1 1.3h-7.6zM257.8 58.6h12.2l.9 1.1-.9 1.1h-12.2zM257.8 45.9h13l1 1.1-1 1.1h-13zM257.8 43.3h12.2l.9 1.2-.9 1.1h-12.2zM258.8 40.8h9.4v2.2h-9.4l-1-1.1zM258.8 51h11.8v2.2h-11.8l-1-1.1zM259 48.2h8v2.7h-8l-1.2-1.4zM259 55.8h9.4v2.7h-9.4l-1.2-1.3zM259 53.3h9.4v2.6h-9.4l-1.2-1.3z"/>
<path d="M14.6 60.3v3.8M17.2 79.9h14.7l1.1 1.4-1.1 1.3h-14.7zM23.3 74.9h8.6l1.1 1.3-1.1 1.3h-8.6zM23.4 77.4h8.5l1.1 1.3-1.1 1.4h-8.5zM41.9 76.2h.8M41.9 78.7h.8M44.3 79.9h9.2v2.7h-9.2l-1.1-1.3zM46.2 76.2h.8M46.2 78.7h.8M64.6 77.4h17.2v2.7h-17.2l-1.1-1.4zM64.6 74.9h17.2v2.6h-17.2l-1.1-1.3zM79.6 76.4h1.1"/>
<path d="M207.6 63.7h12.1v2.2h-12.1l-1-1.1zM208.4 71.1h10.2l1.1 1.3-1.1 1.3h-10.2zM209.1 60.9h9.5l1.1 1.3-1.1 1.4h-9.5zM209.1 66h9.5l1.1 1.3-1.1 1.3h-9.5zM210.5 68.5h8.1l1.1 1.4-1.1 1.3h-8.1zM216.9 68.1h.9M257.8 66.2h10.6l1 1.1-1 1.1h-10.6zM259 68.5h8v2.7h-8l-1.2-1.3zM259 71.1h8.3v2.6h-8.3l-1.2-1.3zM259 63.4h8v2.7h-8l-1.2-1.3zM259 60.9h9.4v2.7h-9.4l-1.2-1.4zM54 84.5v1.7"/>
<path d="M54 87.8v1.7M56.5 95.3v1.2h1.3l-1.3 1.3-1.3-1.3h1.3M59.1 84.5v1.7M59.1 87.8v1.7M237.4 97.7h11.8v2.7h-11.8l-1.2-1.3zM237.4 95.2h10.9v2.7h-10.9l-1.2-1.4zM237.4 100.3h11.7v2.6h-11.7l-1.2-1.3zM237.4 102.8h11.9v2.7h-11.9l-1.2-1.4zM15.6 121.9h23.9l1.1 1.3-1.1 1.3h-23.9zM15.6 137.1h23.9l1.1 1.3-1.1 1.4h-23.9zM37.5 138.7h1.2M48.3 134.6h5"/>
<path d="M71 137.1h17.2v2.7h-17.2l-1.2-1.4zM71 121.9h17.2v2.6h-17.2l-1.2-1.3zM85.9 138.7h1.2M123.9 123.1h8.3l1.1 1.4-1.1 1.3h-8.3zM123.9 130.7h8.3l1.1 1.4-1.1 1.3h-8.3zM123.9 128.2h8.3l1.1 1.3-1.1 1.4h-8.3zM123.9 125.7h8.3l1.1 1.3-1.1 1.3h-8.3zM138.3 128.2h10.8v2.7h-10.8l-1.1-1.4zM138.3 130.7h10.8v2.7h-10.8l-1.1-1.3zM138.3 123.1h10.8v2.7h-10.8l-1.1-1.3zM138.3 125.7h10.8v2.6h-10.8l-1.1-1.3zM164.8 138.4h11.9l1.1 1.3-1.1 1.3h-11.9z"/>
<path d="M165.7 135.8h11l1.1 1.4-1.1 1.3h-11zM166.4 134.6v-1.2l-1.3 1.2 1.3 1.3v-1.3h1.2M179.1 134.6h3.8M179.1 137.2h3.8M179.1 139.7h3.8M182.9 139.6h1.2v.2h-1.2zM182.9 137h1.2v.3h-1.2zM182.9 134.5h1.2v.2h-1.2zM186.7 139.6h1.3v.2h-1.3zM186.7 137h1.3v.3h-1.3zM186.7 134.5h1.3v.2h-1.3zM188 134.6h3.8"/>
<path d="M188 137.2h3.8M188 139.7h3.8M194.2 135.8h11.7v2.7h-11.7l-1.2-1.3zM194.2 138.4h11.8v2.6h-11.8l-1.2-1.3zM230.8 132h11.9l1.1 1.4-1.1 1.3h-11.9zM230.9 137.1h11.8l1.1 1.3-1.1 1.4h-11.8zM231 134.6h11.7l1.1 1.3-1.1 1.3h-11.7zM231.8 129.5h10.9l1.1 1.3-1.1 1.3h-10.9zM247.5 137.1h9.5v2.7h-9.5l-1.1-1.4zM247.5 134.6h9.5v2.6h-9.5l-1.1-1.3zM247.5 132h9.5v2.7h-9.5l-1.1-1.3zM247.5 129.5h9.5v2.6h-9.5l-1.1-1.3z"/>
<path d="M255.1 134.2h.9"/>
</g>
<path d="M50 133.6l1.6 1-1.6 1zM51.6 133.6v2M182.9 133.4h5.1v7.6h-5.1z" fill="none" stroke="#840000" stroke-width=".25"/>
<path d="M13.9 53.8h1.3M14.4 53.8l-.1 .4M15.1 53.8l.1 .4M18.6 51.5h.9M52.9 131.8h.8M53.5 131.4v.9" fill="none" stroke="#006464" stroke-width=".18"/>
<path d="M39.1 75.1h1.2" fill="none" stroke="#0f0f0f" stroke-width=".18"/>
<g fill="none" stroke="#0000c2" stroke-width=".18">
<path d="M40 89.5v.3M40.6 89.5v.3M92.6 86.9v.3M93.1 84.5v.3M97.6 82v1.5M97.6 82.6l-.5-.1-.3 .3v.5l.2 .2h.6M201.2 91.2h.6M201.4 90.7v1.3l.4 .3M203.2 83.8v.9M203.4 93.3l.8 1.5v-1.5M204.6 83.7v1.2l-.3 .3h-.3M204.6 83.8l-.4-.1-.3 .3v.4l.1 .3h.6"/>
<path d="M204.8 95.8a.77 .77 0 0 1 .9 .8 .77 .77 0 0 1-.9 .7M204.8 98.4a.82 .82 0 0 1 .5 .7 .82 .82 0 0 1-.5 .8M26.3 109.9l.2 .2M36 111.1v.3M45.1 110.1h.6M45.1 109.2h.6M45.7 108.6v1.5M73.4 116.2v1.3l.2 .3M85.8 114.4l.2 .2v.4l-.2 .2M204.7 100.9h.6l.2 .3-.1 .4-.7 .1M71.8 130h1.2M84.2 120.2h.9"/>
<path d="M85.8 129.6l.2 .2v.4l-.2 .3M25.9 152.2l.4 .1M26.3 151.7v1.5M26.3 153.2h-.4M28.6 144.8v1.1M28.6 145l.2-.2 .4 .1v1M30.1 147.4l-.4-.1-.2 .2 .1 .2 .5 .2v.3h-.6M31.3 150.3l.2 .2-.2 .3M31.3 149.8h.1M39.5 150.7v.2M48.3 149.8h.6M48.5 149.2v1.4l.4 .2"/>
<path d="M55.5 144.8l.3 .3v.5l-.3 .3M55.8 147.3v1M55.8 147.4l.2-.1 .4 .1 .1 .9M56.5 145l.2-.2 .3 .1 .1 1M56.5 144.8v1.1M57.2 148.2v.1M76 141.3h1.1M93.1 140.9h.5l.1 1"/>
</g>
<g fill="none" stroke="#009600" stroke-width=".18">
<path d="M138.4 29.2v2.6M138.4 30.5h-6.3v6.3h2.5M24.8 54h10.1M24.8 59.1h8.9v5M24.8 51.4h10.1M24.8 56.5h10.1M35.6 45.1v3.8h-10.8M66.7 45.7v1.9M66.7 52.7v3.8M33 76.2h8.9M33 78.7h8.9M47 76.2h16.5"/>
<path d="M47 78.7h16.5M54 78.7v5.8M59.1 76.2v8.3M33 81.3h10.2M54 89.5v5.8h5.1v-5.8M47 119.4h-3.8v3.8M52.1 119.4h2.5M62.2 119.4v3.8h7.6M40.6 138.4h7.7M40.6 123.2h6.4M48.3 134.6h-3.9v3.8M52.1 123.2h2.5"/>
<path d="M53.3 138.4h2.6M53.3 134.6h2.6M63.5 134.6v3.8h6.3M133.3 124.5h3.9M133.3 127h3.9M133.3 129.5h3.9M133.3 132.1h3.9M167.6 134.6h11.5M177.8 137.2h1.3M177.8 139.7h1.3M191.8 134.6h13.9M191.8 137.2h1.2"/>
<path d="M191.8 139.7h1.2M243.8 138.4h2.6M243.8 135.9h2.6M243.8 130.8h2.6M243.8 133.4h2.6"/>
</g>
<path d="M219.1 74.3l1.2 1.2M220.3 74.3l-1.2 1.2" fill="none" stroke="#000084" stroke-width=".18"/>
<g fill="#009600" stroke="#009600" stroke-width=".18">
<circle cx="62.2" cy="123.2" r=".46"/>
<circle cx="63.5" cy="138.4" r=".46"/>
<circle cx="54" cy="78.7" r=".46"/>
<circle cx="59.1" cy="76.2" r=".46"/>
<circle cx="56.5" cy="95.3" r=".46"/>
<circle cx="43.2" cy="123.2" r=".46"/>
<circle cx="44.4" cy="138.4" r=".46"/>
<circle cx="138.4" cy="30.5" r=".46"/>
</g>
<use href="#words"/>
</svg>
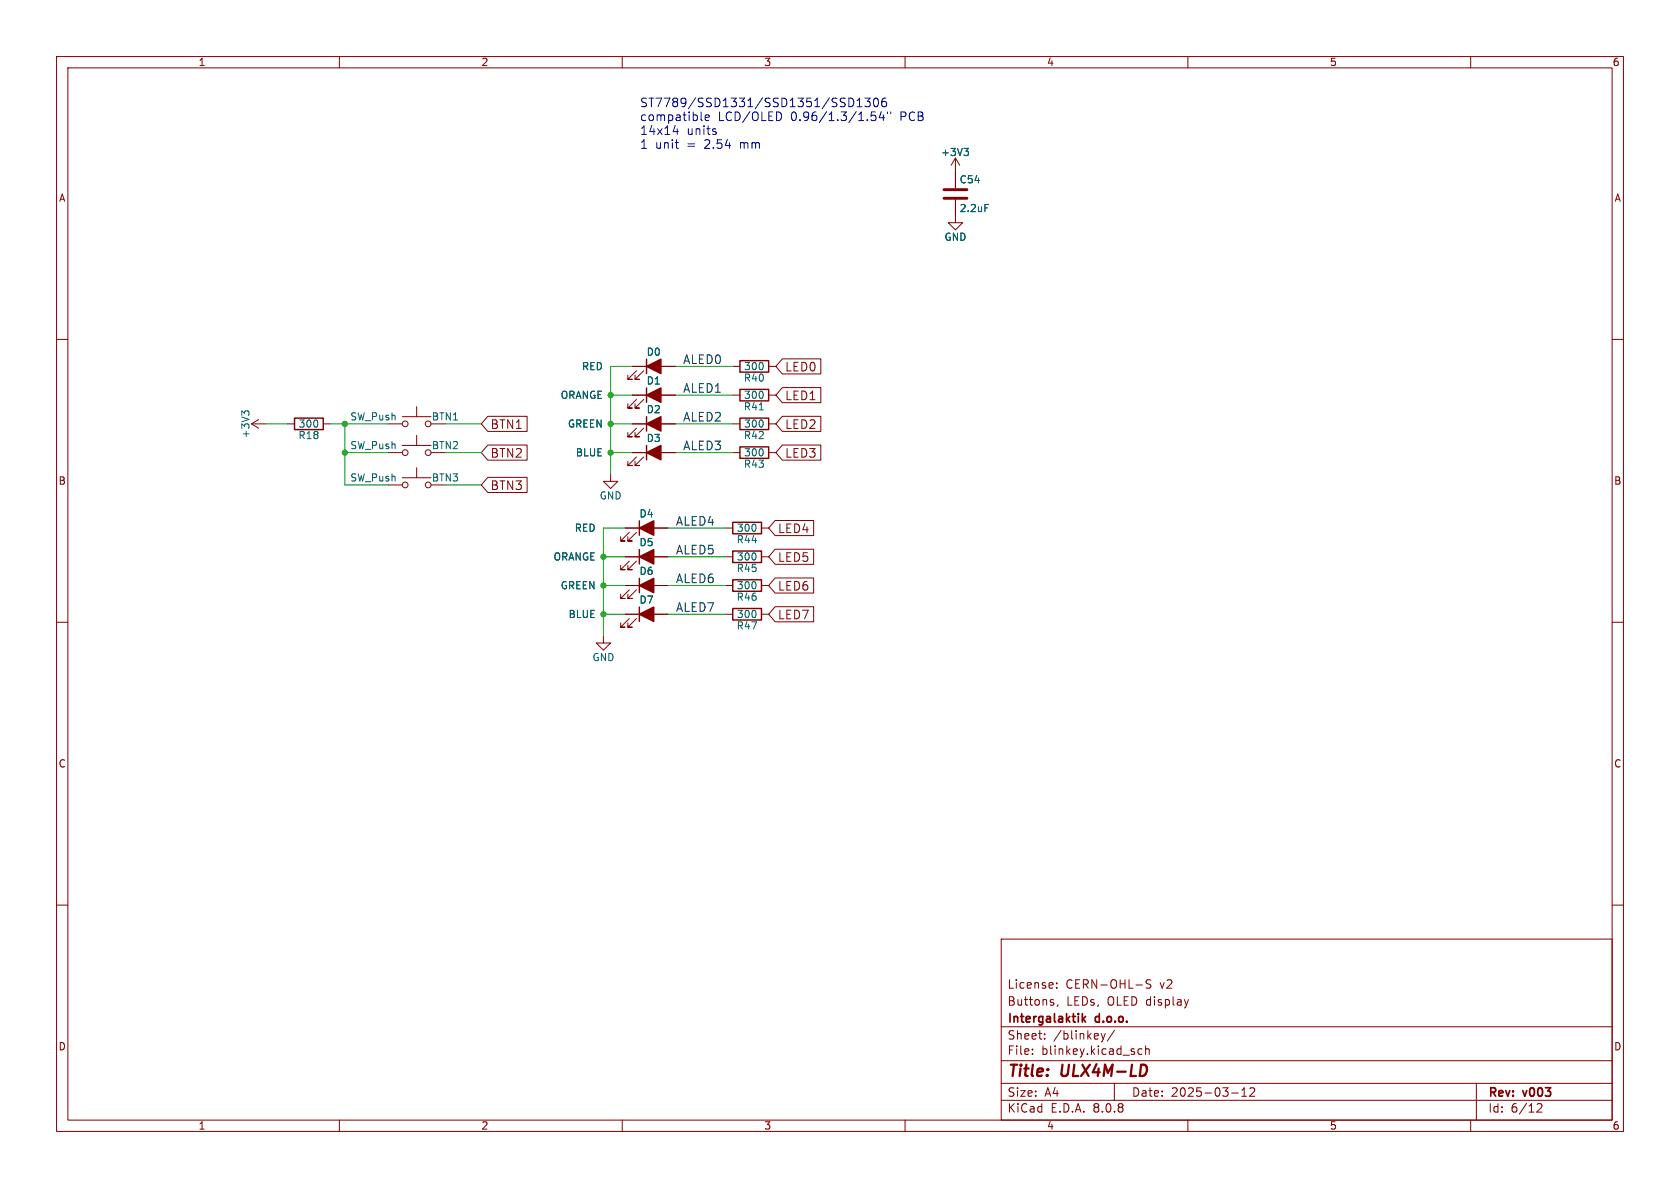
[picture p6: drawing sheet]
<svg xmlns="http://www.w3.org/2000/svg" width="297mm" height="210mm" viewBox="0 0 297 210" stroke-linecap="round" stroke-linejoin="round" font-family="sans-serif">
<defs><g id="words">
<g font-size="2.8" fill="#840000">
<text x="178" y="190.9">Title:</text>
<text x="187.7" y="190.9">ULX4M-LD</text>
</g>
<g font-size="2.1" fill="#0000c2">
<text x="113" y="19.1">ST7789/SSD1331/SSD1351/SSD1306</text>
<text x="113" y="21.5">compatible</text>
<text x="113" y="24">14x14</text>
<text x="121.4" y="24">units</text>
<text x="126.9" y="21.5">LCD/OLED</text>
<text x="139.8" y="21.5">0.96/1.3/1.54&quot;</text>
<text x="159.3" y="21.5">PCB</text>
<text x="113" y="26.4">1</text>
<text x="115.8" y="26.4">unit</text>
<text x="121.5" y="26.4">=</text>
<text x="124.7" y="26.4">2.54</text>
<text x="131.1" y="26.4">mm</text>
</g>
<g font-size="2.1" fill="#0f0f0f">
<text x="120.6" y="64.5">ALED0</text>
<text x="120.6" y="69.5">ALED1</text>
<text x="120.6" y="74.6">ALED2</text>
<text x="120.6" y="79.7">ALED3</text>
<text x="119.4" y="93">ALED4</text>
<text x="119.4" y="98.1">ALED5</text>
<text x="119.4" y="103.2">ALED6</text>
<text x="119.4" y="108.3">ALED7</text>
</g>
<g font-size="2.1" fill="#840000">
<text x="138.7" y="65.9">LED0</text>
<text x="138.7" y="70.9">LED1</text>
<text x="86.6" y="76">BTN1</text>
<text x="138.7" y="76">LED2</text>
<text x="86.6" y="81.1">BTN2</text>
<text x="138.7" y="81.1">LED3</text>
<text x="86.6" y="86.8">BTN3</text>
<text x="137.4" y="94.4">LED4</text>
<text x="137.4" y="99.5">LED5</text>
<text x="137.4" y="104.6">LED6</text>
<text x="137.4" y="109.7">LED7</text>
<text x="178" y="178">Buttons,</text>
<text x="178" y="175">License:</text>
<text x="188.4" y="175">CERN-OHL-S</text>
<text x="188.5" y="178">LEDs,</text>
<text x="195.8" y="178">OLED display</text>
<text x="205.1" y="175">v2</text>
<text x="178" y="184">Sheet:</text>
<text x="178" y="181.2">Intergalaktik</text>
<text x="186.2" y="184">/blinkey/</text>
<text x="193.7" y="181.2">d.o.o.</text>
<text x="178" y="186.7">File:</text>
<text x="184.1" y="186.7">blinkey.kicad_sch</text>
<text x="178" y="196.9">KiCad</text>
<text x="178" y="194.1">Size:</text>
<text x="184.7" y="194.1">A4</text>
<text x="185.7" y="196.9">E.D.A.</text>
<text x="193.3" y="196.9">8.0.8</text>
<text x="200" y="194.1">Date:</text>
<text x="207" y="194.1">2025-03-12</text>
<text x="263" y="194.3">Rev:</text>
<text x="263" y="196.9">Id:</text>
<text x="267.1" y="196.9">6/12</text>
<text x="269.4" y="194.3">v003</text>
</g>
<g font-size="1.8" fill="#840000">
<text x="35" y="11.9">1</text>
<text x="85" y="11.9">2</text>
<text x="135" y="11.9">3</text>
<text x="185" y="11.9">4</text>
<text x="235" y="11.9">5</text>
<text x="285" y="11.9">6</text>
<text x="10.3" y="35.9">A</text>
<text x="285.3" y="35.9">A</text>
<text x="10.3" y="85.9">B</text>
<text x="285.3" y="85.9">B</text>
<text x="10.3" y="135.9">C</text>
<text x="285.3" y="135.9">C</text>
<text x="10.3" y="185.9">D</text>
<text x="285.3" y="185.9">D</text>
<text x="35" y="199.9">1</text>
<text x="85" y="199.9">2</text>
<text x="135" y="199.9">3</text>
<text x="185" y="199.9">4</text>
<text x="235" y="199.9">5</text>
<text x="285" y="199.9">6</text>
</g>
<g font-size="1.8" fill="#006464">
<text x="166.3" y="27.8">+3V3</text>
<text x="169.6" y="32.6">C54</text>
<text x="169.6" y="37.7">2.2uF</text>
<text x="166.9" y="42.8">GND</text>
<text x="102.8" y="65.6">RED</text>
<text x="114.2" y="63.1">D0</text>
<text x="131.4" y="65.6">300</text>
<text x="99" y="70.7">ORANGE</text>
<text x="114.2" y="68.2">D1</text>
<text x="131.4" y="67.7">R40</text>
<text x="131.4" y="70.7">300</text>
<text x="44.3" y="77.6" transform="rotate(-90 44.3 77.6)">+3V3</text>
<text x="52.7" y="77.8">R18</text>
<text x="52.7" y="75.8">300</text>
<text x="61.8" y="74.5">SW_Push</text>
<text x="76.2" y="74.5">BTN1</text>
<text x="100.3" y="75.8">GREEN</text>
<text x="114.2" y="73.3">D2</text>
<text x="131.4" y="77.8">R42</text>
<text x="131.4" y="72.7">R41</text>
<text x="131.4" y="75.8">300</text>
<text x="61.8" y="79.6">SW_Push</text>
<text x="76.2" y="79.6">BTN2</text>
<text x="101.7" y="80.9">BLUE</text>
<text x="114.2" y="78.3">D3</text>
<text x="131.4" y="82.9">R43</text>
<text x="131.4" y="80.9">300</text>
<text x="61.8" y="85.3">SW_Push</text>
<text x="76.2" y="85.3">BTN3</text>
<text x="105.9" y="88.5">GND</text>
<text x="101.5" y="94.2">RED</text>
<text x="113" y="91.7">D4</text>
<text x="130.2" y="94.2">300</text>
<text x="97.8" y="99.3">ORANGE</text>
<text x="113" y="96.7">D5</text>
<text x="113" y="101.8">D6</text>
<text x="130.1" y="101.3">R45</text>
<text x="130.1" y="96.2">R44</text>
<text x="130.2" y="99.3">300</text>
<text x="99" y="104.4">GREEN</text>
<text x="113" y="106.9">D7</text>
<text x="130.1" y="106.4">R46</text>
<text x="130.2" y="104.4">300</text>
<text x="100.4" y="109.4">BLUE</text>
<text x="130.1" y="111.5">R47</text>
<text x="130.2" y="109.4">300</text>
<text x="104.6" y="117.1">GND</text>
</g>
</g></defs>
<g fill="none" stroke="#840000" stroke-width=".18">
<path d="M10 10h277v190h-277zM12 12h273v186h-273zM60 10v2M110 10v2M160 10v2M210 10v2M260 10v2M168.9 35.3v4.1h1.3l-1.3 1.2-1.3-1.2h1.3M168.9 27.9v5.4M168.9 27.9l-.8 1.3M168.9 27.9l.8 1.3M10 60h2"/>
<path d="M44.4 74.9h2.6M44.4 74.9l1.3 .8M45.7 74.2l-1.3 .7M50.8 74.9h1.3M57.1 74.9h1.3M68.6 74.9h2.5M71.1 73.7h5.1M71.1 78.7h5.1M73.7 71.9v1.8M73.7 77v1.7M86.2 73.6h7v2.7h-7l-1.1-1.4zM86.2 78.7h7v2.6h-7l-1.1-1.3z"/>
<path d="M111.8 74.9h7.6M111.8 64.8h7.6M111.8 69.9h7.6M112.5 75.7l-1.5 1.5h.8h-.8v-.7M112.5 65.5l-1.5 1.6h.8h-.8v-.8M112.5 70.6l-1.5 1.5h.8h-.8v-.7M113.8 75.7l-1.5 1.5h.7h-.7v-.7M113.8 65.5l-1.5 1.6h.7h-.7v-.8M113.8 70.6l-1.5 1.5h.7h-.7v-.7M129.5 74.9h1.3M129.5 64.8h1.3M129.5 69.9h1.3"/>
<path d="M135.9 74.9h1.3M135.9 64.8h1.3M135.9 69.9h1.3M138.3 73.6h6.8v2.7h-6.8l-1.1-1.4zM138.3 63.4h6.8v2.7h-6.8l-1.1-1.3zM138.3 68.5h6.8v2.7h-6.8l-1.1-1.3zM138.3 78.7h6.8v2.6h-6.8l-1.1-1.3zM285 60h2M68.6 85.7h2.5M68.6 80h2.5M71.1 84.5h5.1M73.7 82.7v1.8"/>
<path d="M86.2 84.4h7v2.7h-7l-1.1-1.4zM107.9 83.8v1.3h1.3l-1.3 1.3-1.2-1.3h1.2M110.5 98.4h7.6M110.5 93.3h7.6M111.3 94.1l-1.6 1.5h.8h-.8v-.7M111.3 99.2l-1.6 1.5h.8h-.8v-.8M111.8 80h7.6M112.5 80.8l-1.5 1.5h.8h-.8v-.8M112.5 94.1l-1.5 1.5h.8h-.8v-.7M112.5 99.2l-1.5 1.5h.8h-.8v-.8M113.8 80.8l-1.5 1.5h.7h-.7v-.8M128.3 98.4h1.2"/>
<path d="M128.3 93.3h1.2M129.5 80h1.3M134.6 98.4h1.3M134.6 93.3h1.3M135.9 80h1.3M137 92h6.8v2.7h-6.8l-1.1-1.4zM137 97.1h6.8v2.7h-6.8l-1.1-1.4zM10 110h2M106.7 112.4v1.3h1.2l-1.2 1.2-1.3-1.2h1.3M110.5 108.6h7.6M110.5 103.5h7.6M111.3 109.3l-1.6 1.6h.8h-.8v-.8"/>
<path d="M111.3 104.3l-1.6 1.5h.8h-.8v-.8M112.5 109.3l-1.5 1.6h.8h-.8v-.8M112.5 104.3l-1.5 1.5h.8h-.8v-.8M128.3 108.6h1.2M128.3 103.5h1.2M134.6 108.6h1.3M134.6 103.5h1.3M137 107.3h6.8v2.6h-6.8l-1.1-1.3zM137 102.2h6.8v2.6h-6.8l-1.1-1.3zM285 110h2M10 160h2M177 166h108v32h-108z"/>
<path d="M186.1 177.2l.2 .2-.2 .3M186.1 176.7l.1 .1M186.8 174.6v.1M186.8 173.8v.1M187 177.6l-.1 .3M203.5 173.3l-.6-.1-.2 .1v.5l.6 .3 .2 .3-.3 .3-.6-.1M210.1 176.7l-.4 1M285 160h2M60 198v2M110 198v2M160 198v2M177 194.5h108"/>
<path d="M177 191.5h108M177 187.5h108M177 181.5h108M182.5 186.3v.1M182.5 185.5v.1M184.7 183.6v.1M184.7 182.8v.1M194.7 182.7l.3 1M195 183.7l-.1 .4-.2 .1M195.4 182.7l-.4 1M197 191.5v3M197 182.1l-1.3 2"/>
<path d="M201.9 185.5l-.4-.1-.3 .3v.4l.1 .2h.6M202.5 185.5l.2-.1 .4 .1 .1 .9M202.5 184.9v1.5M210 198v2M217.7 193.2h1.2M219.5 193.8h.9M219.5 192.7l.5-.4v1.5M221 192.4l.5-.1 .2 .1 .1 .3-.9 1.1h.9M260 198v2M261 191.5v6.5M271.7 195.2l.6-.1 .2 .1 .1 .3-.9 1.1h.9"/>
<circle cx="71.6" cy="74.9" r=".51"/>
<circle cx="75.7" cy="74.9" r=".51"/>
<circle cx="71.6" cy="80" r=".51"/>
<circle cx="71.6" cy="85.7" r=".51"/>
<circle cx="75.7" cy="85.7" r=".51"/>
<circle cx="75.7" cy="80" r=".51"/>
</g>
<path d="M191.3 179.2v1.5M191.9 179.7l-.6 .6M191.5 180.1l.4 .6" fill="none" stroke="#840000" stroke-width=".3"/>
<g fill="none" stroke="#840000" stroke-width=".25">
<path d="M52.1 73.9h5v2h-5zM114.3 63.5v2.5M114.3 68.6v2.5M114.3 73.7v2.5M114.3 78.7v2.6M130.8 79h5.1v2h-5.1zM130.8 73.9h5.1v2h-5.1zM130.8 68.8h5.1v2.1h-5.1zM130.8 63.8h5.1v2h-5.1zM113 92.1v2.5M113 97.2v2.5M129.5 97.4h5.1v2h-5.1z"/>
<path d="M129.5 92.3h5.1v2.1h-5.1zM113 102.2v2.6M113 107.3v2.6M129.5 107.6h5.1v2h-5.1zM129.5 102.5h5.1v2h-5.1z"/>
</g>
<g fill="#840000" stroke="#840000" stroke-width=".25">
<path d="M114.3 74.9l2.5-1.2v2.5z"/>
<path d="M114.3 64.8l2.5-1.3v2.5z"/>
<path d="M114.3 80l2.5-1.3v2.6z"/>
<path d="M114.3 69.9l2.5-1.3v2.5z"/>
<path d="M113 93.3l2.6-1.2v2.5z"/>
<path d="M113 108.6l2.6-1.3v2.6z"/>
<path d="M113 98.4l2.6-1.2v2.5z"/>
<path d="M113 103.5l2.6-1.3v2.6z"/>
</g>
<path d="M170.4 26.2h.8l-.4 .5M171 26.7l.2 .3v.3l-.2 .2M174.1 36.1h.6M43.2 73.1l-.5-.5v.8M43.2 72.9l.3-.3h.3l.2 .3M134.2 72.5h.8" fill="none" stroke="#006464" stroke-width=".18"/>
<path d="M166.9 35.1h4M166.9 33.5h4" fill="none" stroke="#840000" stroke-width=".51"/>
<g fill="none" stroke="#0000c2" stroke-width=".18">
<path d="M150.1 17.3a.77 .77 0 0 1 .8 .8 .77 .77 0 0 1-.8 .8M151.5 18.9h.9M151.5 17.8l.5-.5v1.6M152.9 17.3h.9l-.5 .6 .5 .2v.6l-.2 .2h-.5l-.2-.2M154.6 17.5l.2-.2a.83 .83 0 0 1 .6 .7 .83 .83 0 0 1-.3 .8l-.2 .1a.82 .82 0 0 1-.3-1.4zM154.8 19.8h-.7l-.1 .7 .2-.1h.5l.2 .3-.1 .5-.2 .1-.6-.1M155.8 19.7l-.4 1.1h1M156.6 17.3a.6 .6 0 0 0-.7 .7v.6l.1 .2 .5 .1 .2-.2v-.5l-.1-.2-.4-.1-.3 .3M156.9 19.8v.3M157.5 19.8v.3M119 23.3h1M119.4 25.2h.6"/>
<path d="M119.7 22.8v1M119.8 26.2h.2M123.9 21.1l.3 .2M124.7 20.8l.7-.1-.1-.3-.4-.1-.2 .2v.7h.6M126.4 23.3l.2 .2-.2 .3M126.4 22.8h.2M138.1 20.2v.8M156.2 20.3v1"/>
</g>
<g fill="none" stroke="#009600" stroke-width=".18">
<path d="M47 74.9h3.8M58.4 74.9h10.2M61 74.9v10.8h7.6M78.7 74.9h6.4M107.9 74.9h3.9M107.9 69.9h3.9M111.8 64.8h-3.9v19M119.4 64.8h10.1M119.4 74.9h10.1M119.4 69.9h10.1M61 80h7.6M78.7 80h6.4"/>
<path d="M78.7 85.7h6.4M106.7 98.4h3.8M107.9 80h3.9M110.5 93.3h-3.8v19.1M118.1 93.3h10.2M118.1 98.4h10.2M119.4 80h10.1M106.7 103.5h3.8M106.7 108.6h3.8M118.1 103.5h10.2M118.1 108.6h10.2"/>
</g>
<g fill="#009600" stroke="#009600" stroke-width=".18">
<circle cx="106.7" cy="98.4" r=".46"/>
<circle cx="106.7" cy="103.5" r=".46"/>
<circle cx="106.7" cy="108.6" r=".46"/>
<circle cx="107.9" cy="80" r=".46"/>
<circle cx="107.9" cy="69.9" r=".46"/>
<circle cx="61" cy="80" r=".46"/>
<circle cx="61" cy="74.9" r=".46"/>
<circle cx="107.9" cy="74.9" r=".46"/>
</g>
<use href="#words"/>
</svg>
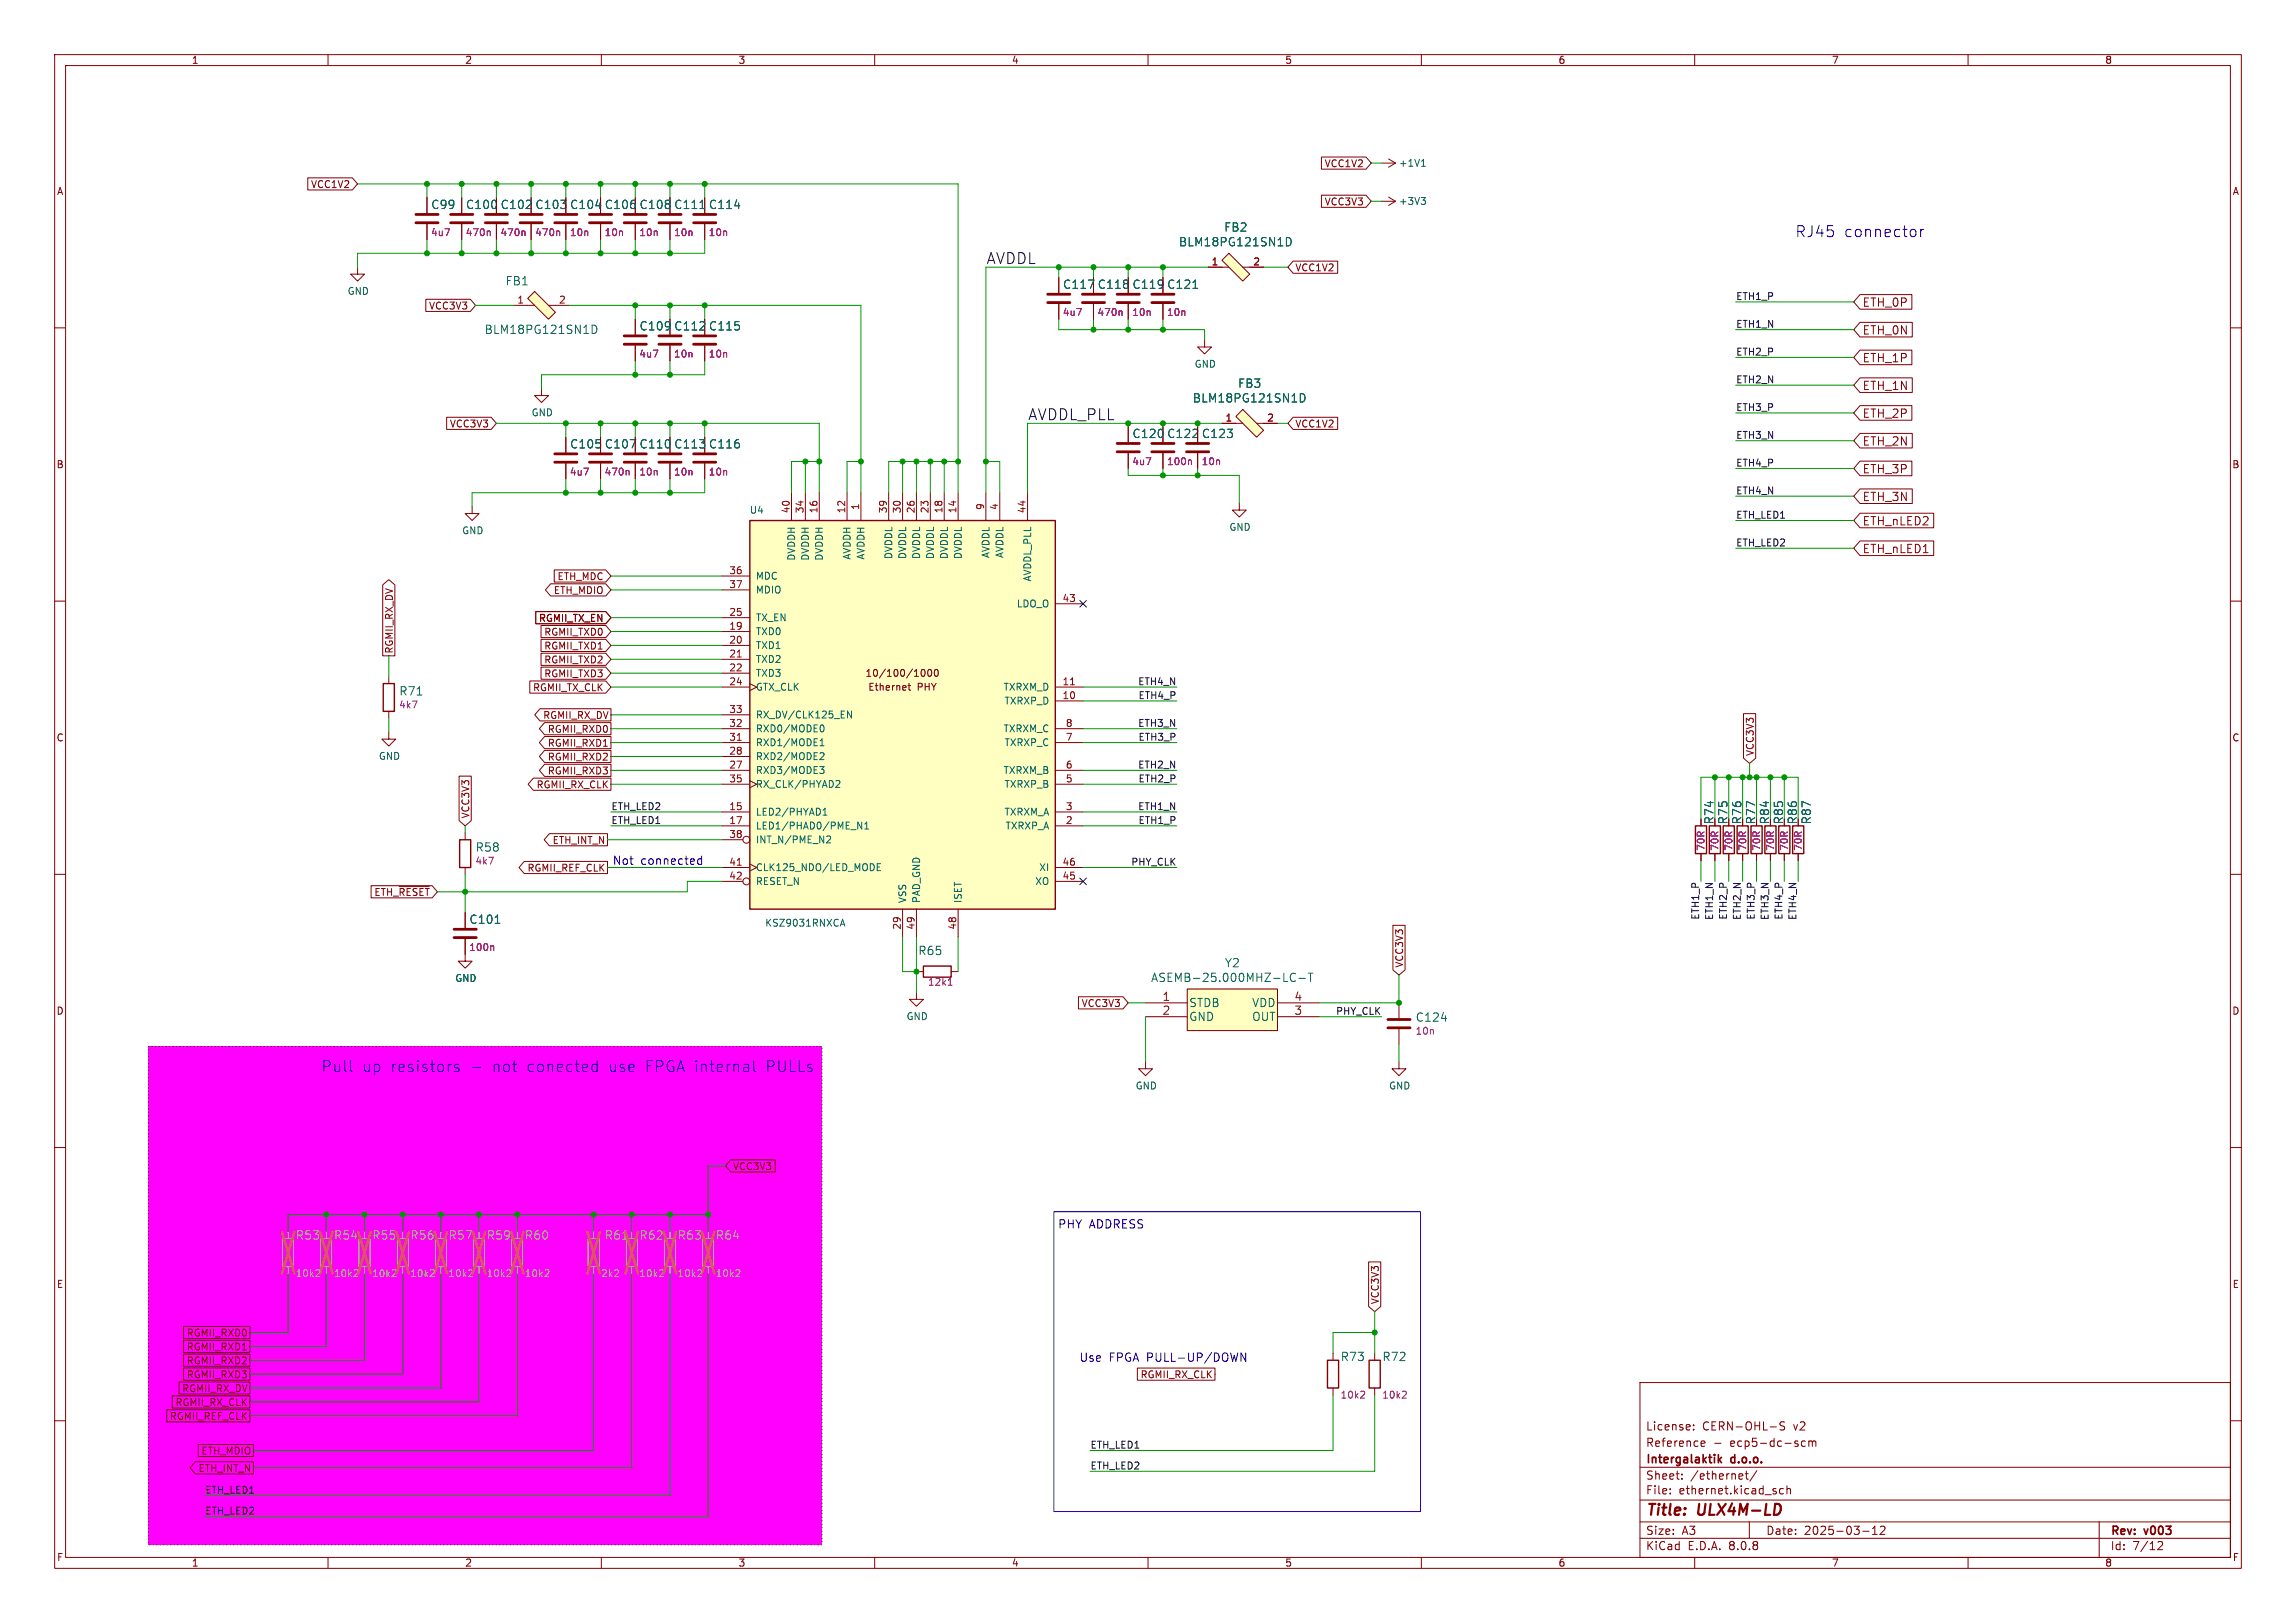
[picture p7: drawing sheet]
<svg xmlns="http://www.w3.org/2000/svg" width="420mm" height="297mm" viewBox="0 0 420 297" stroke-linecap="round" stroke-linejoin="round" font-family="sans-serif">
<defs><g id="words">
<g font-size="2.8" fill="#0000c2">
<text x="328.3" y="43.6">RJ45</text>
<text x="337.2" y="43.6">connector</text>
<text x="58.7" y="196.3">Pull</text>
<text x="66.2" y="196.3">up</text>
<text x="71.4" y="196.3">resistors</text>
<text x="90" y="196.3">not</text>
<text x="96.4" y="196.3">conected</text>
<text x="111.5" y="196.3">use</text>
<text x="118.2" y="196.3">FPGA internal</text>
<text x="140.4" y="196.3">PULLs</text>
</g>
<g font-size="2.8" fill="#0f0f0f">
<text x="180.3" y="48.5">AVDDL</text>
<text x="188" y="77.1">AVDDL_PLL</text>
</g>
<g font-size="2.8" fill="#840000">
<text x="301" y="277.9">Title:</text>
<text x="310.6" y="277.9">ULX4M-LD</text>
</g>
<g font-size="2.1" fill="#006464">
<text x="78.8" y="38.5">C99</text>
<text x="91.5" y="38.5">C102</text>
<text x="104.2" y="38.5">C104</text>
<text x="110.5" y="38.5">C106</text>
<text x="116.9" y="38.5">C108</text>
<text x="123.2" y="38.5">C111</text>
<text x="129.6" y="38.5">C114</text>
<text x="215.6" y="45.3">BLM18PG121SN1D</text>
<text x="223.8" y="42.6">FB2</text>
<text x="92.4" y="52.4">FB1</text>
<text x="194.4" y="53.1">C117</text>
<text x="213.4" y="53.1">C121</text>
<text x="88.6" y="61.3">BLM18PG121SN1D</text>
<text x="116.9" y="60.7">C109</text>
<text x="123.2" y="60.7">C112</text>
<text x="129.6" y="60.7">C115</text>
<text x="226.4" y="71.2">FB3</text>
<text x="218.1" y="73.9">BLM18PG121SN1D</text>
<text x="116.9" y="82.3">C110</text>
<text x="123.2" y="82.3">C113</text>
<text x="129.6" y="82.3">C116</text>
<text x="207.1" y="80.4">C120</text>
<text x="219.8" y="80.4">C123</text>
<text x="73" y="127.5">R71</text>
<text x="316.2" y="150.9" transform="rotate(-90 316.2 150.9)">R75</text>
<text x="321.3" y="150.9" transform="rotate(-90 321.3 150.9)">R77</text>
<text x="323.8" y="150.9" transform="rotate(-90 323.8 150.9)">R84</text>
<text x="326.4" y="150.9" transform="rotate(-90 326.4 150.9)">R85</text>
<text x="331.4" y="150.9" transform="rotate(-90 331.4 150.9)">R87</text>
<text x="86.9" y="156.1">R58</text>
<text x="85.8" y="169.3">C101</text>
<text x="167.9" y="175">R65</text>
<text x="210.5" y="179.9">ASEMB-25.000MHZ-LC-T</text>
<text x="224" y="177.2">Y2</text>
<text x="217.4" y="184.5">STDB</text>
<text x="229" y="184.5">VDD</text>
<text x="217.4" y="187">GND</text>
<text x="229" y="187">OUT</text>
<text x="258.9" y="187.2">C124</text>
<text x="245.2" y="249.3">R73</text>
<text x="252.8" y="249.3">R72</text>
</g>
<g font-size="2.1" fill="#840000">
<text x="85.1" y="38.5">C100</text>
<text x="97.8" y="38.5">C103</text>
<text x="200.7" y="53.1">C118</text>
<text x="207.1" y="53.1">C119</text>
<text x="340.6" y="56.3">ETH_0P</text>
<text x="340.6" y="61.4">ETH_0N</text>
<text x="340.6" y="71.6">ETH_1N</text>
<text x="340.6" y="66.5">ETH_1P</text>
<text x="340.6" y="76.7">ETH_2P</text>
<text x="104.2" y="82.3">C105</text>
<text x="110.5" y="82.3">C107</text>
<text x="213.4" y="80.4">C122</text>
<text x="340.6" y="81.7">ETH_2N</text>
<text x="340.6" y="86.8">ETH_3P</text>
<text x="340.6" y="91.9">ETH_3N</text>
<text x="340.6" y="101.4">ETH_nLED1</text>
<text x="340.6" y="96.3">ETH_nLED2</text>
<text x="313.7" y="150.9" transform="rotate(-90 313.7 150.9)">R74</text>
<text x="318.7" y="150.9" transform="rotate(-90 318.7 150.9)">R76</text>
<text x="328.9" y="150.9" transform="rotate(-90 328.9 150.9)">R86</text>
<text x="301" y="262">License:</text>
<text x="311.4" y="262">CERN-OHL-S</text>
<text x="328.1" y="262">v2</text>
<text x="301" y="268.2">Intergalaktik</text>
<text x="301" y="265">Reference</text>
<text x="316.5" y="265">ecp5-dc-scm</text>
<text x="316.7" y="268.2">d.o.o.</text>
<text x="301" y="273.7">File:</text>
<text x="301" y="271">Sheet:</text>
<text x="307.1" y="273.7">ethernet.kicad_sch</text>
<text x="309.2" y="271">/ethernet/</text>
<text x="301" y="281.1">Size:</text>
<text x="307.6" y="281.1">A3</text>
<text x="323" y="281.1">Date:</text>
<text x="330" y="281.1">2025-03-12</text>
<text x="386" y="281.3">Rev:</text>
<text x="392.4" y="281.3">v003</text>
<text x="301" y="283.9">KiCad</text>
<text x="308.7" y="283.9">E.D.A.</text>
<text x="316.3" y="283.9">8.0.8</text>
<text x="386" y="283.9">Id:</text>
<text x="390.1" y="283.9">7/12</text>
</g>
<g font-size="2.1" fill="#0000c2">
<text x="112" y="158.5">Not</text>
<text x="117.2" y="158.5">connected</text>
<text x="193.5" y="225">PHY ADDRESS</text>
<text x="197.4" y="249.4">Use</text>
<text x="202.8" y="249.4">FPGA PULL-UP/DOWN</text>
</g>
<g font-size="2.1" fill="#a90000">
<text x="212.6" y="183.3">1</text>
<text x="212.6" y="185.8">2</text>
<text x="236.7" y="185.8">3</text>
<text x="236.7" y="183.3">4</text>
</g>
<g font-size="2.1" fill="#989898">
<text x="54" y="227.1">R53</text>
<text x="61" y="227.1">R54</text>
<text x="68" y="227.1">R55</text>
<text x="75" y="227.1">R56</text>
<text x="82" y="227.1">R57</text>
<text x="89" y="227.1">R59</text>
<text x="95.9" y="227.1">R60</text>
<text x="110.5" y="227.1">R61</text>
<text x="116.9" y="227.1">R62</text>
<text x="123.9" y="227.1">R63</text>
<text x="130.9" y="227.1">R64</text>
</g>
<g font-size="1.8" fill="#840000">
<text x="35" y="11.9">1</text>
<text x="85" y="11.9">2</text>
<text x="135" y="11.9">3</text>
<text x="185" y="11.9">4</text>
<text x="235" y="11.9">5</text>
<text x="285" y="11.9">6</text>
<text x="335" y="11.9">7</text>
<text x="385" y="11.9">8</text>
<text x="10.3" y="35.9">A</text>
<text x="56.8" y="34.6">VCC1V2</text>
<text x="242.2" y="30.8">VCC1V2</text>
<text x="408.3" y="35.9">A</text>
<text x="242.2" y="37.8">VCC3V3</text>
<text x="236.9" y="49.8">VCC1V2</text>
<text x="78.4" y="56.8">VCC3V3</text>
<text x="82.2" y="78.4">VCC3V3</text>
<text x="236.9" y="78.4">VCC1V2</text>
<text x="10.3" y="85.9">B</text>
<text x="408.2" y="85.9">B</text>
<text x="101.9" y="106.4">ETH_MDC</text>
<text x="98.5" y="114">RGMII_TX_EN</text>
<text x="101.2" y="108.9">ETH_MDIO</text>
<text x="72.1" y="119.7" transform="rotate(-90 72.1 119.7)">RGMII_RX_DV</text>
<text x="99.5" y="119.1">RGMII_TXD1</text>
<text x="99.5" y="116.5">RGMII_TXD0</text>
<text x="99.5" y="124.1">RGMII_TXD3</text>
<text x="99.5" y="121.6">RGMII_TXD2</text>
<text x="158.2" y="124.1">10/100/1000</text>
<text x="97.4" y="126.7">RGMII_TX_CLK</text>
<text x="99.3" y="131.8">RGMII_RX_DV</text>
<text x="158.7" y="126.6">Ethernet</text>
<text x="167.8" y="126.6">PHY</text>
<text x="10.3" y="135.9">C</text>
<text x="100.1" y="136.8">RGMII_RXD1</text>
<text x="100.1" y="134.3">RGMII_RXD0</text>
<text x="408.2" y="135.9">C</text>
<text x="100.1" y="139.4">RGMII_RXD2</text>
<text x="100.1" y="141.9">RGMII_RXD3</text>
<text x="321" y="138.4" transform="rotate(-90 321 138.4)">VCC3V3</text>
<text x="86" y="149.9" transform="rotate(-90 86 149.9)">VCC3V3</text>
<text x="98.1" y="144.5">RGMII_RX_CLK</text>
<text x="101" y="154.6">ETH_INT_N</text>
<text x="96.4" y="159.7">RGMII_REF_CLK</text>
<text x="68.4" y="164.1">ETH_~{RESET}</text>
<text x="256.9" y="177.2" transform="rotate(-90 256.9 177.2)">VCC3V3</text>
<text x="10.3" y="185.9">D</text>
<text x="197.8" y="184.5">VCC3V3</text>
<text x="408.2" y="185.9">D</text>
<text x="134" y="214.3">VCC3V3</text>
<text x="10.3" y="235.9">E</text>
<text x="252.4" y="238.8" transform="rotate(-90 252.4 238.8)">VCC3V3</text>
<text x="408.3" y="235.9">E</text>
<text x="34.1" y="244.8">RGMII_RXD0</text>
<text x="34.1" y="247.3">RGMII_RXD1</text>
<text x="34.1" y="249.9">RGMII_RXD2</text>
<text x="32" y="257.5">RGMII_RX_CLK</text>
<text x="33.2" y="255">RGMII_RX_DV</text>
<text x="34.1" y="252.4">RGMII_RXD3</text>
<text x="208.5" y="252.4">RGMII_RX_CLK</text>
<text x="31" y="260">RGMII_REF_CLK</text>
<text x="36.2" y="269.6">ETH_INT_N</text>
<text x="36.8" y="266.4">ETH_MDIO</text>
<text x="10.3" y="285.9">F</text>
<text x="35" y="286.9">1</text>
<text x="85" y="286.9">2</text>
<text x="135" y="286.9">3</text>
<text x="185" y="286.9">4</text>
<text x="235" y="286.9">5</text>
<text x="285" y="286.9">6</text>
<text x="335" y="286.9">7</text>
<text x="385" y="286.9">8</text>
<text x="408.3" y="285.9">F</text>
</g>
<g font-size="1.8" fill="#006464">
<text x="255.8" y="30.7">+1V1</text>
<text x="255.8" y="37.7">+3V3</text>
<text x="63.5" y="54.2">GND</text>
<text x="218.4" y="67.5">GND</text>
<text x="97.2" y="76.4">GND</text>
<text x="137.1" y="94.2">U4</text>
<text x="84.5" y="98">GND</text>
<text x="224.8" y="97.3">GND</text>
<text x="138.2" y="106.3">MDC</text>
<text x="145.6" y="102.7" transform="rotate(-90 145.6 102.7)">DVDDH</text>
<text x="148.2" y="102.7" transform="rotate(-90 148.2 102.7)">DVDDH</text>
<text x="150.7" y="102.7" transform="rotate(-90 150.7 102.7)">DVDDH</text>
<text x="155.8" y="102.5" transform="rotate(-90 155.8 102.5)">AVDDH</text>
<text x="158.3" y="102.5" transform="rotate(-90 158.3 102.5)">AVDDH</text>
<text x="163.4" y="102.4" transform="rotate(-90 163.4 102.4)">DVDDL</text>
<text x="166" y="102.4" transform="rotate(-90 166 102.4)">DVDDL</text>
<text x="168.5" y="102.4" transform="rotate(-90 168.5 102.4)">DVDDL</text>
<text x="171" y="102.4" transform="rotate(-90 171 102.4)">DVDDL</text>
<text x="173.6" y="102.4" transform="rotate(-90 173.6 102.4)">DVDDL</text>
<text x="176.1" y="102.4" transform="rotate(-90 176.1 102.4)">DVDDL</text>
<text x="181.2" y="102.2" transform="rotate(-90 181.2 102.2)">AVDDL</text>
<text x="183.7" y="102.2" transform="rotate(-90 183.7 102.2)">AVDDL</text>
<text x="188.8" y="106.5" transform="rotate(-90 188.8 106.5)">AVDDL_PLL</text>
<text x="138.2" y="113.9">TX_EN</text>
<text x="138.2" y="108.8">MDIO</text>
<text x="185.9" y="111.4">LDO_O</text>
<text x="138.2" y="116.4">TXD0</text>
<text x="138.2" y="119">TXD1</text>
<text x="138.2" y="121.5">TXD2</text>
<text x="138.2" y="124.1">TXD3</text>
<text x="138.2" y="126.6">GTX_CLK</text>
<text x="138.2" y="131.7">RX_DV/CLK125_EN</text>
<text x="183.5" y="126.6">TXRXM_D</text>
<text x="183.7" y="129.1">TXRXP_D</text>
<text x="138.2" y="136.8">RXD1/MODE1</text>
<text x="138.2" y="134.2">RXD0/MODE0</text>
<text x="183.5" y="134.2">TXRXM_C</text>
<text x="183.7" y="136.8">TXRXP_C</text>
<text x="69.2" y="139.2">GND</text>
<text x="138.2" y="141.8">RXD3/MODE3</text>
<text x="138.2" y="139.3">RXD2/MODE2</text>
<text x="183.5" y="141.8">TXRXM_B</text>
<text x="138.2" y="149.5">LED2/PHYAD1</text>
<text x="138.2" y="144.4">RX_CLK/PHYAD2</text>
<text x="183.7" y="149.5">TXRXM_A</text>
<text x="183.7" y="144.4">TXRXP_B</text>
<text x="138.2" y="152">LED1/PHAD0/PME_N1</text>
<text x="138.2" y="154.5">INT_N/PME_N2</text>
<text x="183.8" y="152">TXRXP_A</text>
<text x="138.2" y="159.6">CLK125_NDO/LED_MODE</text>
<text x="190" y="159.6">XI</text>
<text x="138.2" y="162.2">RESET_N</text>
<text x="166" y="165.4" transform="rotate(-90 166 165.4)">VSS</text>
<text x="168.5" y="165.4" transform="rotate(-90 168.5 165.4)">PAD_GND</text>
<text x="176.1" y="165.4" transform="rotate(-90 176.1 165.4)">ISET</text>
<text x="189.3" y="162.2">XO</text>
<text x="139.9" y="169.8">KSZ9031RNXCA</text>
<text x="83.2" y="179.9">GND</text>
<text x="165.7" y="186.9">GND</text>
<text x="207.6" y="199.6">GND</text>
<text x="254" y="199.6">GND</text>
</g>
<g font-size="1.8" fill="#840084">
<text x="78.7" y="43.4">4u7</text>
<text x="85.1" y="43.4">470n</text>
<text x="91.4" y="43.4">470n</text>
<text x="97.8" y="43.4">470n</text>
<text x="104.1" y="43.4">10n</text>
<text x="110.5" y="43.4">10n</text>
<text x="116.8" y="43.4">10n</text>
<text x="123.2" y="43.4">10n</text>
<text x="129.5" y="43.4">10n</text>
<text x="194.3" y="58">4u7</text>
<text x="200.7" y="58">470n</text>
<text x="207" y="58">10n</text>
<text x="213.4" y="58">10n</text>
<text x="116.8" y="65.6">4u7</text>
<text x="123.2" y="65.6">10n</text>
<text x="129.5" y="65.6">10n</text>
<text x="104.1" y="87.2">4u7</text>
<text x="110.5" y="87.2">470n</text>
<text x="116.8" y="87.2">10n</text>
<text x="123.2" y="87.2">10n</text>
<text x="129.5" y="87.2">10n</text>
<text x="207" y="85.3">4u7</text>
<text x="213.4" y="85.3">100n</text>
<text x="219.7" y="85.3">10n</text>
<text x="72.9" y="129.8">4k7</text>
<text x="312" y="155.8" transform="rotate(-90 312 155.8)">70R</text>
<text x="314.6" y="155.8" transform="rotate(-90 314.6 155.8)">70R</text>
<text x="317.1" y="155.8" transform="rotate(-90 317.1 155.8)">70R</text>
<text x="319.6" y="155.8" transform="rotate(-90 319.6 155.8)">70R</text>
<text x="322.2" y="155.8" transform="rotate(-90 322.2 155.8)">70R</text>
<text x="324.7" y="155.8" transform="rotate(-90 324.7 155.8)">70R</text>
<text x="327.3" y="155.8" transform="rotate(-90 327.3 155.8)">70R</text>
<text x="329.8" y="155.8" transform="rotate(-90 329.8 155.8)">70R</text>
<text x="86.9" y="158.4">4k7</text>
<text x="85.7" y="174.2">100n</text>
<text x="169.7" y="180.6">12k1</text>
<text x="258.8" y="189.5">10n</text>
<text x="245.1" y="256.1">10k2</text>
<text x="252.7" y="256.1">10k2</text>
</g>
<g font-size="1.8" fill="#a90000">
<text x="221.5" y="48.6">1</text>
<text x="229.2" y="48.6">2</text>
<text x="94.5" y="55.6">1</text>
<text x="102.2" y="55.6">2</text>
<text x="224.1" y="77.2">1</text>
<text x="231.7" y="77.2">2</text>
<text x="144.5" y="94" transform="rotate(-90 144.5 94)">40</text>
<text x="147.1" y="94" transform="rotate(-90 147.1 94)">34</text>
<text x="149.6" y="94" transform="rotate(-90 149.6 94)">16</text>
<text x="154.7" y="94" transform="rotate(-90 154.7 94)">12</text>
<text x="157.2" y="93.4" transform="rotate(-90 157.2 93.4)">1</text>
<text x="162.3" y="94" transform="rotate(-90 162.3 94)">39</text>
<text x="164.8" y="94" transform="rotate(-90 164.8 94)">30</text>
<text x="167.4" y="94" transform="rotate(-90 167.4 94)">26</text>
<text x="169.9" y="94" transform="rotate(-90 169.9 94)">23</text>
<text x="172.5" y="94" transform="rotate(-90 172.5 94)">18</text>
<text x="175" y="94" transform="rotate(-90 175 94)">14</text>
<text x="180.1" y="93.4" transform="rotate(-90 180.1 93.4)">9</text>
<text x="182.6" y="93.4" transform="rotate(-90 182.6 93.4)">4</text>
<text x="187.7" y="94" transform="rotate(-90 187.7 94)">44</text>
<text x="133.3" y="105.2">36</text>
<text x="133.3" y="107.7">37</text>
<text x="133.3" y="112.8">25</text>
<text x="194.3" y="110.2">43</text>
<text x="133.3" y="115.3">19</text>
<text x="133.3" y="117.9">20</text>
<text x="133.3" y="120.4">21</text>
<text x="133.3" y="122.9">22</text>
<text x="133.3" y="125.5">24</text>
<text x="194.3" y="125.5">11</text>
<text x="133.3" y="130.6">33</text>
<text x="194.3" y="128">10</text>
<text x="133.3" y="135.6">31</text>
<text x="133.3" y="133.1">32</text>
<text x="194.9" y="135.6">7</text>
<text x="194.9" y="133.1">8</text>
<text x="133.3" y="140.7">27</text>
<text x="133.3" y="138.2">28</text>
<text x="133.3" y="143.3">35</text>
<text x="194.9" y="143.3">5</text>
<text x="194.9" y="140.7">6</text>
<text x="133.3" y="148.3">15</text>
<text x="194.9" y="148.3">3</text>
<text x="133.3" y="150.9">17</text>
<text x="133.3" y="153.4">38</text>
<text x="194.9" y="150.9">2</text>
<text x="133.3" y="158.5">41</text>
<text x="133.3" y="161">42</text>
<text x="194.3" y="161">45</text>
<text x="194.3" y="158.5">46</text>
<text x="164.8" y="170.2" transform="rotate(-90 164.8 170.2)">29</text>
<text x="167.4" y="170.2" transform="rotate(-90 167.4 170.2)">49</text>
<text x="175" y="170.2" transform="rotate(-90 175 170.2)">48</text>
</g>
<g font-size="1.8" fill="#0f0f0f">
<text x="317.5" y="55">ETH1_P</text>
<text x="317.5" y="60.1">ETH1_N</text>
<text x="317.5" y="65.1">ETH2_P</text>
<text x="317.5" y="70.2">ETH2_N</text>
<text x="317.5" y="75.3">ETH3_P</text>
<text x="317.5" y="80.4">ETH3_N</text>
<text x="317.5" y="85.5">ETH4_P</text>
<text x="317.5" y="95">ETH_LED1</text>
<text x="317.5" y="90.5">ETH4_N</text>
<text x="317.5" y="100.1">ETH_LED2</text>
<text x="208.1" y="125.5">ETH4_N</text>
<text x="208.2" y="128">ETH4_P</text>
<text x="208.1" y="133.1">ETH3_N</text>
<text x="208.2" y="135.6">ETH3_P</text>
<text x="208.1" y="140.7">ETH2_N</text>
<text x="208.2" y="143.2">ETH2_P</text>
<text x="111.8" y="148.3">ETH_LED2</text>
<text x="208.1" y="148.3">ETH1_N</text>
<text x="111.8" y="150.9">ETH_LED1</text>
<text x="208.2" y="150.9">ETH1_P</text>
<text x="206.8" y="158.5">PHY_CLK</text>
<text x="310.9" y="168.4" transform="rotate(-90 310.9 168.4)">ETH1_P</text>
<text x="313.4" y="168.4" transform="rotate(-90 313.4 168.4)">ETH1_N</text>
<text x="316" y="168.4" transform="rotate(-90 316 168.4)">ETH2_P</text>
<text x="318.5" y="168.4" transform="rotate(-90 318.5 168.4)">ETH2_N</text>
<text x="321" y="168.4" transform="rotate(-90 321 168.4)">ETH3_P</text>
<text x="323.6" y="168.4" transform="rotate(-90 323.6 168.4)">ETH3_N</text>
<text x="326.1" y="168.4" transform="rotate(-90 326.1 168.4)">ETH4_P</text>
<text x="328.7" y="168.4" transform="rotate(-90 328.7 168.4)">ETH4_N</text>
<text x="244.3" y="185.8">PHY_CLK</text>
<text x="199.4" y="265.2">ETH_LED1</text>
<text x="199.4" y="269">ETH_LED2</text>
<text x="37.5" y="273.4">ETH_LED1</text>
<text x="37.5" y="277.2">ETH_LED2</text>
</g>
<g font-size="1.8" fill="#a1a1a1">
<text x="54" y="233.9">10k2</text>
<text x="61" y="233.9">10k2</text>
<text x="68" y="233.9">10k2</text>
<text x="74.9" y="233.9">10k2</text>
<text x="81.9" y="233.9">10k2</text>
<text x="88.9" y="233.9">10k2</text>
<text x="95.9" y="233.9">10k2</text>
<text x="109.9" y="233.9">2k2</text>
<text x="116.8" y="233.9">10k2</text>
<text x="123.8" y="233.9">10k2</text>
<text x="130.8" y="233.9">10k2</text>
</g>
</g></defs>
<g fill="none" stroke="#840000" stroke-width=".18">
<path d="M10 10h400v277h-400zM12 12h396v273h-396zM60 10v2M110 10v2M160 10v2M210 10v2M260 10v2M310 10v2M360 10v2M10 60h2M408 60h2M10 110h2"/>
<path d="M408 110h2M10 160h2M408 160h2M10 210h2M408 210h2M300 253h108v32h-108zM10 260h2M300 278.5h108M300 274.5h108M300 268.5h108M305.5 273.2v.2M305.5 272.5v.1"/>
<path d="M307.7 270.5v.2M307.7 269.8v.1M309.8 261.5v.2M309.8 260.8v.1M311.2 264.6h.6M311.2 263.8l.5-.1 .2 .3-.7 .2M313.7 264.1h1.1M319.2 269.7h.6M319.4 269.2v1.3l.4 .2M320 278.5v3M321.4 269.1l-1.3 1.9M326.2 272.5l-.4-.1-.3 .3v.4l.2 .2h.5"/>
<path d="M326.4 260.3l-.5-.1-.2 .1v.5l.6 .2 .1 .4-.2 .3-.6-.1M326.9 272.5l.2-.1 .3 .1 .1 .9M326.9 271.9v1.5M330.2 263.8l-.4-.1-.3 .3v.4l.2 .2h.5M330.9 263.8l.4-.1 .2 .2M330.9 263.7v1M331.5 263.9l.2-.2 .4 .1 .1 .9M331.5 263.9v.8M342.5 279.7l.4-.4v1.5M343.9 279.4l.6-.1 .2 .1 .1 .3-.9 1.1h.9M384 278.5v6.5M408 260h2"/>
<path d="M60 285v2M110 285v2M160 285v2M210 285v2M260 285v2M300 281.5h108M310 285v2M340.7 280.2h1.2M342.5 280.8h.9M360 285v2M394.7 282.2l.6-.1 .2 .1 .1 .3-.9 1.1h.9"/>
</g>
<path d="M314.3 266.2v1.5M314.5 267.1l.4 .6M314.9 266.7l-.6 .6" fill="none" stroke="#840000" stroke-width=".3"/>
<path d="M27.2 191.5h123.2v91.2h-123.2z" fill="#f0f"/>
<path d="M107.8 39.2h4.1M114.2 39.2h4M120.5 39.2h4.1M126.9 39.2h4M107.8 40.8h4.1M114.2 40.8h4M120.5 40.8h4.1M126.9 40.8h4M253.9 188.1h4M253.9 186.6h4" fill="none" stroke="#840000" stroke-width=".51"/>
<g fill="none" stroke="#840000" stroke-width=".18">
<path d="M128.9 36.2v2.8M109.9 41v2.8M116.2 41v2.8M122.6 41v2.8M128.9 41v2.8M99.1 71.1v1.3h1.2l-1.2 1.3-1.3-1.3h1.3M167.6 177.8h1.3M174 177.8h1.3M167.6 181.6v1.3h1.3l-1.3 1.3-1.2-1.3h1.2M255.9 194.3v1.3h1.3l-1.3 1.3-1.3-1.3h1.3M255.9 183.5v2.8M255.9 188.3v2.8"/>
<path d="M243.8 247.6v1.3M243.8 254v1.3M251.5 247.6v1.3M251.5 254v1.3"/>
</g>
<path d="M168.9 176.8h5.1v2h-5.1zM242.8 248.9h2.1v5.1h-2.1zM250.4 248.9h2.1v5.1h-2.1z" fill="none" stroke="#840000" stroke-width=".25"/>
<path d="M173.7 179.2l.1-.2v1.3M173.4 180.3h.8M249.4 254.6l.2 .2v.3l-.8 .7h.8M257 254.6l.3 .2-.1 .3-.7 .7h.8" fill="none" stroke="#840084" stroke-width=".18"/>
<path d="M128 38.2h.9" fill="none" stroke="#006464" stroke-width=".18"/>
<path d="M96.5 54.6l1.3-1.3 3.8 3.9-1.3 1.2z" fill="#ffffc2"/>
<g fill="none" stroke="#840000" stroke-width=".18">
<path d="M78.1 36.2v2.8M65.4 48.9v1.3h1.3l-1.3 1.2-1.3-1.2h1.3M78.1 41v2.8M90.8 41v2.8M94 55.9h3.8M96.5 54.6l1.3-1.3 3.8 3.9-1.3 1.2zM97.2 41v2.8M100.3 55.9h3.8M103.5 41v2.8M116.2 58.4v2.8M200 55.6v2.8M116.2 63.2v2.8"/>
<path d="M122.6 63.2v2.8M128.9 63.2v2.8M206.4 78.1v2.8M103.5 80v2.8M103.5 84.8v2.8M206.4 82.9v2.8M85.1 152.4v1.3M85.1 158.8v1.2M311.1 149.9v1.2M311.1 156.2v1.3M313.7 156.2v1.3M316.2 156.2v1.3"/>
<path d="M318.8 156.2v1.3M321.3 156.2v1.3M323.8 156.2v1.3M326.4 156.2v1.3M328.9 156.2v1.3M85.1 171.8v4.1h1.3l-1.3 1.3-1.3-1.3h1.3M85.1 167v2.8M209.5 194.3v1.3h1.3l-1.3 1.3-1.2-1.3h1.2"/>
</g>
<path d="M108.3 59.5a.77 .77 0 0 1 .9 .8 .77 .77 0 0 1-.9 .7zM90.6 169h.8" fill="none" stroke="#006464" stroke-width=".18"/>
<g fill="none" stroke="#840000" stroke-width=".51">
<path d="M76.1 39.2h4M88.8 39.2h4M95.1 39.2h4.1M101.5 39.2h4M76.1 40.8h4M88.8 40.8h4M95.1 40.8h4.1M101.5 40.8h4M198 55.4h4.1M198 53.8h4.1M114.2 63h4M114.2 61.5h4"/>
<path d="M120.5 63h4.1M120.5 61.5h4.1M126.9 63h4M126.9 61.5h4M101.5 84.6h4M101.5 83.1h4M204.3 82.7h4.1M204.3 81.2h4.1M83.1 171.6h4M83.1 170.1h4"/>
</g>
<path d="M95.8 42.3l.2 .2v.6M102.2 42.3l.2 .2v.6M205.1 56.9l.1 .2v.6M90.1 173.1l.2 .2v.6" fill="none" stroke="#840084" stroke-width=".18"/>
<path d="M84.1 153.7h2v5.1h-2zM310.1 151.1h2.1v5.1h-2.1zM312.7 151.1h2v5.1h-2zM315.2 151.1h2v5.1h-2zM317.8 151.1h2v5.1h-2zM320.3 151.1h2v5.1h-2zM322.8 151.1h2.1v5.1h-2.1zM325.4 151.1h2v5.1h-2zM327.9 151.1h2v5.1h-2z" fill="none" stroke="#840000" stroke-width=".25"/>
<path d="M223.5 47.6l1.3-1.2 3.8 3.8-1.3 1.2z" fill="#ffffc2"/>
<g fill="none" stroke="#840000" stroke-width=".18">
<path d="M84.5 36.2v2.8M252.7 29.8h2.6M252.7 36.8h2.6M254 29.1l1.3 .7M254 36.1l1.3 .7M255.3 29.8l-1.3 .8M255.3 36.8l-1.3 .8M84.5 41v2.8M193.7 50.8v2.8M193.7 55.6v2.8M206.4 55.6v2.8M212.7 55.6v2.8"/>
<path d="M221 48.9h3.8M223.5 47.6l1.3-1.2 3.8 3.8-1.3 1.2zM227.3 48.9h3.8M220.3 62.2v1.3h1.3l-1.3 1.3-1.2-1.3h1.2M212.7 82.9v2.8M219.1 82.9v2.8M226.7 92.1v1.2h1.3l-1.3 1.3-1.3-1.3h1.3"/>
</g>
<path d="M260 36.1h.7l-.4 .5M260 30.4h.7M260.1 29.5l.3-.3v1.2M260.5 36.6l.2 .3v.3l-.2 .2M218.2 52.8h.9M235.3 43.5a.77 .77 0 0 1 .9 .7 .77 .77 0 0 1-.9 .8z" fill="none" stroke="#006464" stroke-width=".18"/>
<path d="M82.4 39.2h4.1M82.4 40.8h4.1M191.6 55.4h4.1M191.6 53.8h4.1M204.3 55.4h4.1M204.3 53.8h4.1M210.7 55.4h4.1M210.7 53.8h4.1M210.7 82.7h4.1M210.7 81.2h4.1M217 82.7h4.1M217 81.2h4.1" fill="none" stroke="#840000" stroke-width=".51"/>
<path d="M89.5 42.3l.2 .2v.6M217.8 84.2l.1 .2v.6" fill="none" stroke="#840084" stroke-width=".18"/>
<path d="M226.1 76.2l1.2-1.3 3.8 3.8-1.2 1.3z" fill="#ffffc2"/>
<path d="M223.5 77.5h3.8M226.1 76.2l1.2-1.3 3.8 3.8-1.2 1.3zM229.9 77.5h3.8" fill="none" stroke="#840000" stroke-width=".18"/>
<path d="M237.9 72a.77 .77 0 0 1 .8 .8 .77 .77 0 0 1-.8 .8z" fill="none" stroke="#006464" stroke-width=".18"/>
<path d="M137.2 95.3h55.8v71.1h-55.8z" fill="#ffffc2"/>
<path d="M137.2 95.3h55.8v71.1h-55.8z" fill="none" stroke="#840000" stroke-width=".25"/>
<g fill="none" stroke="#840000" stroke-width=".18">
<path d="M144.8 90.2v5.1M147.3 90.2v5.1M149.9 90.2v5.1M154.9 90.2v5.1M157.5 90.2v5.1M162.6 90.2v5.1M165.1 90.2v5.1M167.6 90.2v5.1M170.2 90.2v5.1M172.7 90.2v5.1M175.3 90.2v5.1M180.3 90.2v5.1"/>
<path d="M182.9 90.2v5.1M188 90.2v5.1M132.1 115.6h5.1M132.1 118.1h5.1M132.1 113h5.1M132.1 105.4h5.1M132.1 108h5.1M193 110.5h5.1M132.1 125.7h5.1M132.1 120.7h5.1M132.1 123.2h5.1M132.1 138.4h5.1"/>
<path d="M132.1 135.9h5.1M132.1 133.4h5.1M132.1 130.8h5.1M137.2 125.1l1.2 .6-1.2 .7M166.1 125.5h.5M166.3 125v1.1l.3 .2M168.5 122.7l.3-.2a.68 .68 0 0 1 .4 .6 .68 .68 0 0 1-.4 .7l-.3-.3M169.8 122.6l.2-.1a.68 .68 0 0 1 .4 .6 .68 .68 0 0 1-.4 .7l-.3-.5zM171 122.6l.2-.1a.68 .68 0 0 1 .4 .6 .68 .68 0 0 1-.4 .7l-.3-.5zM193 128.3h5.1M193 125.7h5.1M193 135.9h5.1"/>
<path d="M193 133.4h5.1M132.1 148.6h5.1M132.1 151.1h5.1M132.1 141h5.1M132.1 143.5h5.1M132.1 153.7h3.8M132.1 158.8h5.1M137.2 142.9l1.2 .6-1.2 .6M137.2 158.1l1.2 .7-1.2 .6M193 148.6h5.1M193 151.1h5.1M193 141h5.1"/>
<path d="M193 143.5h5.1M193 158.8h5.1M132.1 161.3h3.8M165.1 166.4v5.1M167.6 166.4v5.1M175.3 166.4v5.1M193 161.3h5.1"/>
<circle cx="136.5" cy="153.7" r=".63"/>
<circle cx="136.5" cy="161.3" r=".63"/>
</g>
<path d="M134.9 120.2h.7M134.9 135.5h.7M195.8 125.3h.7M134.9 158.3h.7" fill="none" stroke="#a90000" stroke-width=".18"/>
<g fill="none" stroke="#006464" stroke-width=".18">
<path d="M150 136.5h.7M150 135.6l.4-.4v1.3M150.2 132.7h.1a.68 .68 0 0 1 .5 .6 .68 .68 0 0 1-.5 .6h-.1M150.2 137.7l.4 .1 .1 .3-.8 .9h.8M155.8 130.1v1.3l-.8-1.3v1.3M149.9 140.3h.8l-.4 .5 .4 .1v.4l-.2 .2h-.4M150.6 149.2h.7M150.6 148.3l.3-.4v1.3M151.3 153h.4l.2 .3-.7 .9h.7M153.1 142.8l.4 .1 .1 .3-.7 .9h.7M157.6 150.4v1.3l-.7-1.3v1.3M158.2 151.7h.7"/>
<path d="M158.2 150.8l.3-.4v1.3M160.5 158.7h.4M161.1 158.1h-.6v1.2h.6M153.7 169.5l.4-1.3 .4 1.3M153.8 169.1h.6"/>
</g>
<path d="M217.2 181h16.5v7.6h-16.5z" fill="#ffffc2"/>
<g fill="none" stroke="#840000" stroke-width=".18">
<path d="M56.3 32.5h8.2l.9 1.2-.9 1.1h-8.2zM78.1 36.2v2.8M84.5 36.2v2.8M128.9 36.2v2.8M241.7 35.7h8.2l.9 1.1-.9 1.1h-8.2zM241.7 28.7h8.2l.9 1.1-.9 1.2h-8.2zM77.9 54.8h8.1l1 1.1-1 1.1h-8.1zM78.1 41v2.8M84.5 41v2.8M90.8 41v2.8M97.2 41v2.8M103.5 41v2.8"/>
<path d="M109.9 41v2.8M116.2 41v2.8M116.2 58.4v2.8M122.6 41v2.8M128.9 41v2.8M193.7 50.8v2.8M193.7 55.6v2.8M200 55.6v2.8M206.4 55.6v2.8M212.7 55.6v2.8M221 48.9h2.5M228.6 48.9h2.5"/>
<path d="M236.5 47.8h8.2v2.2h-8.2l-.9-1.1zM340.2 59h9.6v2.7h-9.6l-1.1-1.4zM340.2 53.9h9.5v2.7h-9.5l-1.1-1.4zM81.7 76.4h8.2l.9 1.1-.9 1.1h-8.2zM116.2 63.2v2.8M122.6 63.2v2.8M128.9 63.2v2.8M206.4 78.1v2.8M223.5 77.5h2.6M231.1 77.5h2.6M236.5 76.4h8.2v2.2h-8.2l-.9-1.1zM340.2 74.2h9.5v2.7h-9.5l-1.1-1.3z"/>
<path d="M340.2 69.2h9.6v2.6h-9.6l-1.1-1.3zM340.2 64.1h9.5v2.6h-9.5l-1.1-1.3zM340.2 79.3h9.6v2.7h-9.6l-1.1-1.4zM86.4 92.7v1.3h1.2l-1.2 1.3-1.3-1.3h1.3M103.5 80v2.8M103.5 84.8v2.8M109.9 84.8v2.8M116.2 84.8v2.8M122.6 84.8v2.8M128.9 84.8v2.8M206.4 82.9v2.8M212.7 82.9v2.8"/>
<path d="M219.1 82.9v2.8M340.2 99h13.5v2.7h-13.5l-1.1-1.4zM340.2 93.9h13.5v2.7h-13.5l-1.1-1.3zM340.2 89.5h9.6v2.6h-9.6l-1.1-1.3zM340.2 84.4h9.5v2.7h-9.5l-1.1-1.4zM70 107l1.1-.9 1.1 .9v13h-2.2zM98 111.9h12.8l1 1.1-1 1.1h-12.8zM99 117h11.8l1 1.1-1 1.1h-11.8zM99 119.5h11.8l1 1.2-1 1.1h-11.8zM99 114.5h11.8l1 1.1-1 1.1h-11.8zM100.7 106.8h10.1l1 1.2-1 1.1h-10.1l-.9-1.1zM101.4 104.3h9.4l1 1.1-1 1.1h-9.4z"/>
<path d="M71.1 134v1.3h1.3l-1.3 1.2-1.3-1.2h1.3M71.1 123.8v1.3M71.1 130.2v1.2M96.9 124.6h13.9l1 1.1-1 1.1h-13.9zM98.8 129.7h13v2.2h-13l-1-1.1zM99 122.1h11.8l1 1.1-1 1.1h-11.8zM99.6 137.3h12.2v2.2h-12.2l-.9-1.1zM99.6 139.9h12.2v2.2h-12.2l-.9-1.1zM99.6 134.8h12.2v2.2h-12.2l-.9-1.1zM99.6 132.2h12.2v2.3h-12.2l-.9-1.1zM318.9 130.6h2.3v8.1l-1.2 1-1.1-1zM84 142h2.2v8.2l-1.1 .9-1.1-.9z"/>
<path d="M95.9 157.6h15.2v2.3h-15.2l-1-1.1zM97.6 142.4h14.2v2.2h-14.2l-1-1.1zM100.5 152.6h10.6v2.2h-10.6l-1-1.1zM311.1 149.9v1.2M311.1 156.2v1.3M313.7 156.2v1.3M316.2 156.2v1.3M318.8 156.2v1.3M321.3 156.2v1.3M323.8 156.2v1.3M326.4 156.2v1.3M328.9 156.2v1.3"/>
<path d="M67.9 162.1h11.2l.9 1.1-.9 1.1h-11.2zM73 162.2h5.5M85.1 167v2.8M85.1 171.8v2.8M254.8 169.3h2.2v8.2l-1.1 .9-1.1-.9zM197.3 182.4h8.1l1 1.1-1 1.1h-8.1zM209.5 183.5h7.7M209.5 186.1h7.7M217.2 181h16.5v7.6h-16.5zM233.7 183.5h7.6M233.7 186.1h7.6M133.7 212.2h8.1v2.3h-8.1l-1-1.1z"/>
<path d="M250.3 230.9h2.3v8.2l-1.1 .9-1.2-.9zM30.5 258h15.2v2.2h-15.2zM31.5 255.4h14.2v2.3h-14.2zM32.7 252.9h13v2.2h-13zM33.6 250.3h12.1v2.3h-12.1zM33.6 245.3h12.1v2.2h-12.1zM33.6 247.8h12.1v2.2h-12.1zM33.6 242.7h12.1v2.3h-12.1zM208 250.3h14.2v2.3h-14.2zM35.7 267.5h10.7v2.2h-10.7l-.9-1.1zM36.3 264.3h10.1v2.2h-10.1z"/>
</g>
<path d="M128 38.2h.9M218.2 52.8h.9M235.3 43.5a.77 .77 0 0 1 .9 .7 .77 .77 0 0 1-.9 .8zM237.9 72a.77 .77 0 0 1 .8 .8 .77 .77 0 0 1-.8 .8zM90.6 169h.8M237 178.2a.61 .61 0 0 0-.8 0 .61 .61 0 0 0-.2 .8 .57 .57 0 0 0 .3 .5 .57 .57 0 0 0 .7 0M237.6 179h1.2M239.3 178.1h.9M239.7 178.1v1.5" fill="none" stroke="#006464" stroke-width=".18"/>
<path d="M51.7 226.7h2v5.1h-2zM58.7 226.7h2v5.1h-2zM65.7 226.7h2v5.1h-2zM72.6 226.7h2.1v5.1h-2.1zM79.6 226.7h2.1v5.1h-2.1zM86.6 226.7h2v5.1h-2zM93.6 226.7h2v5.1h-2zM107.6 226.7h2v5.1h-2zM114.6 226.7h2v5.1h-2zM121.5 226.7h2.1v5.1h-2.1zM128.5 226.7h2.1v5.1h-2.1z" fill="none" stroke="#a1a1a1" stroke-width=".25"/>
<g fill="none" stroke="#a1a1a1" stroke-width=".18">
<path d="M52.7 225.4v1.3M52.7 231.8v1.2M58.3 232.4l.2 .2-.1 .3-.7 .7h.8M59.7 225.4v1.3M59.7 231.8v1.2M65.2 232.4l.3 .2-.1 .3-.7 .7h.8M66.7 225.4v1.3M66.7 231.8v1.2M72.2 232.4l.3 .2-.1 .3-.7 .7h.8M73.7 225.4v1.3M73.7 231.8v1.2M79.2 232.4l.3 .2-.1 .3-.7 .7h.8"/>
<path d="M80.6 225.4v1.3M80.6 231.8v1.2M86.2 232.4l.2 .2v.3l-.7 .7h.7M87.6 225.4v1.3M87.6 231.8v1.2M93.2 232.4l.2 .2v.3l-.8 .7h.8M94.6 225.4v1.3M94.6 231.8v1.2M100.2 232.4l.2 .2v.3l-.8 .7h.8M108.6 225.4v1.3M108.6 231.8v1.2M115.6 225.4v1.3"/>
<path d="M115.6 231.8v1.2M121.1 232.4l.3 .2-.1 .3-.7 .7h.8M122.6 225.4v1.3M122.6 231.8v1.2M128.1 232.4l.3 .2-.1 .3-.7 .7h.8M129.5 225.4v1.3M129.5 231.8v1.2M135.1 232.4l.2 .2v.3l-.8 .7h.8"/>
</g>
<g fill="none" stroke="#e65255" stroke-width=".46">
<path d="M51.6 225.4l2.2 7.6M53.8 225.4l-2.2 7.6M58.5 225.4l2.3 7.6M60.8 225.4l-2.3 7.6M65.5 225.4l2.3 7.6M67.8 225.4l-2.3 7.6M72.5 225.4l2.3 7.6M74.8 225.4l-2.3 7.6M79.5 225.4l2.3 7.6M81.8 225.4l-2.3 7.6M86.5 225.4l2.3 7.6M88.8 225.4l-2.3 7.6"/>
<path d="M93.5 225.4l2.3 7.6M95.8 225.4l-2.3 7.6M107.4 225.4l2.3 7.6M109.7 225.4l-2.3 7.6M114.4 225.4l2.3 7.6M116.7 225.4l-2.3 7.6M121.4 225.4l2.3 7.6M123.7 225.4l-2.3 7.6M128.4 225.4l2.3 7.6M130.7 225.4l-2.3 7.6"/>
</g>
<path d="M107.8 84.6h4.1M107.8 83.1h4.1M114.2 84.6h4M114.2 83.1h4M120.5 84.6h4.1M120.5 83.1h4.1M126.9 84.6h4M126.9 83.1h4" fill="none" stroke="#840000" stroke-width=".51"/>
<path d="M89.5 42.3l.2 .2v.6M95.8 42.3l.2 .2v.6M102.2 42.3l.2 .2v.6M205.1 56.9l.1 .2v.6M114.9 86.1l.2 .2v.6M217.8 84.2l.1 .2v.6M90.1 173.1l.2 .2v.6" fill="none" stroke="#840084" stroke-width=".18"/>
<path d="M70.1 125.1h2v5.1h-2z" fill="none" stroke="#840000" stroke-width=".25"/>
<g fill="none" stroke="#0000c2" stroke-width=".18">
<path d="M351.3 42v1.3M351.9 42l-.4 .1-.2 .3M128.3 156.7v1.5M128.3 157.2h-.4l-.3 .3v.4l.2 .2h.5M64.1 194.1v1.7l.3 .3M83.9 194.9l-.5-.1-.3 .2 .1 .3 .7 .2 .1 .2-.1 .3-.2 .1-.6-.1M86.4 195.3h1.5M108.5 196l.2 .1 .5-.1M108.5 194.9l.2-.1 .5 .1M109.2 194.1v2M137.9 194.1v1.7l.3 .3M192.8 221.7h67v54.9h-67z"/>
<path d="M227.9 247.6v1.5l-.9-1.5v1.5"/>
</g>
<path d="M27.2 191.5h123.2v91.2h-123.2z" fill="none" stroke="#000" stroke-width=".18" stroke-dasharray="0 .6"/>
<g fill="none" stroke="#009600" stroke-width=".18">
<path d="M65.4 33.7h109.9v56.5M78.1 33.7v2.5M84.5 33.7v2.5M90.8 33.7v2.5M97.2 33.7v2.5M103.5 33.7v2.5M109.9 33.7v2.5M116.2 33.7v2.5M122.6 33.7v2.5M128.9 33.7v2.5M250.8 36.8h1.9M250.8 29.8h1.9"/>
<path d="M78.1 43.8v2.6M84.5 43.8v2.6M87 55.9h7M90.8 43.8v2.6M97.2 43.8v2.6M103.5 43.8v2.6M104.1 55.9h53.4v34.3M109.9 43.8v2.6M116.2 43.8v2.6M116.2 55.9v2.5M122.6 43.8v2.6M122.6 55.9v2.5"/>
<path d="M128.9 43.8v2.6h-63.5v2.5M128.9 55.9v2.5M193.7 58.4v1.9h26.6v1.9M193.7 48.9v1.9M200 48.9v1.9M200 58.4v1.9M206.4 48.9v1.9M206.4 58.4v1.9M212.7 48.9v1.9M212.7 58.4v1.9M221 48.9h-40.7v41.3M231.1 48.9h4.5"/>
<path d="M317.5 55.2h21.6M90.8 77.5h59.1v12.7M103.5 77.5v2.5M109.9 77.5v2.5M116.2 66v2.6M116.2 77.5v2.5M122.6 66v2.6M122.6 77.5v2.5M128.9 66v2.6h-29.8v2.5M128.9 77.5v2.5M206.4 77.5v.6M212.7 77.5v.6"/>
<path d="M219.1 77.5v.6M223.5 77.5h-35.5v12.7M233.7 77.5h1.9M317.5 70.5h21.6M317.5 65.4h21.6M317.5 60.3h21.6M317.5 75.6h21.6M103.5 87.6v2.6M109.9 87.6v2.6M116.2 87.6v2.6M122.6 87.6v2.6M128.9 87.6v2.6h-42.5v2.5"/>
<path d="M147.3 84.5v5.7M149.9 84.5h-5.1v5.7M157.5 84.5h-2.6v5.7M165.1 84.5v5.7M167.6 84.5v5.7M170.2 84.5v5.7M172.7 84.5v5.7M175.3 84.5h-12.7v5.7M180.3 84.5h2.6v5.7M206.4 85.7v1.3h20.3v5.1M212.7 85.7v1.3M219.1 85.7v1.3"/>
<path d="M317.5 90.8h21.6M317.5 95.3h21.6M317.5 80.6h21.6M317.5 85.7h21.6M111.8 105.4h20.3M111.8 108h20.3M111.8 118.1h20.3M111.8 113h20.3M111.8 115.6h20.3M317.5 100.3h21.6M71.1 120v3.8M71.1 131.4v2.6"/>
<path d="M111.8 130.8h20.3M111.8 120.7h20.3M111.8 125.7h20.3M111.8 135.9h20.3M111.8 123.2h20.3M111.8 138.4h20.3M111.8 133.4h20.3M198.1 128.3h17.2M198.1 125.7h17.2M198.1 135.9h17.2M198.1 133.4h17.2M320 139.7v2.5"/>
<path d="M85.1 151.1v1.3M111.1 158.8h21M111.1 153.7h21M111.8 141h20.3M111.8 151.1h20.3M111.8 148.6h20.3M111.8 143.5h20.3M198.1 141h17.2M198.1 158.8h17.2M198.1 151.1h17.2M198.1 148.6h17.2M198.1 143.5h17.2"/>
<path d="M311.1 149.9v-7.7h17.8v7.7M311.1 157.5v3.8M313.7 142.2v7.7M313.7 157.5v3.8M316.2 142.2v7.7M316.2 157.5v3.8M318.8 142.2v7.7M318.8 157.5v3.8M321.3 142.2v7.7M321.3 157.5v3.8M323.8 142.2v7.7M323.8 157.5v3.8"/>
<path d="M326.4 142.2v7.7M326.4 157.5v3.8M328.9 157.5v3.8M85.1 160v7M132.1 161.3h-6.4v1.9h-45.7M165.1 171.5v6.3h2.5M167.6 171.5v10.1M175.3 171.5v6.3M255.9 178.4v5.1h-14.6M206.4 183.5h3.1M209.5 186.1v8.2M241.3 186.1h11.4"/>
<path d="M255.9 191.1v3.2M132.7 213.4h-3.2v12M52.7 233v10.8h-7M59.7 222.2v3.2M59.7 233v13.4h-14M66.7 222.2v3.2M66.7 233v15.9h-21M73.7 222.2v3.2M73.7 233v18.5h-28M80.6 222.2v3.2M80.6 233v21h-34.9M87.6 222.2v3.2"/>
<path d="M87.6 233v23.5h-41.9M94.6 222.2v3.2M94.6 233v26.1h-48.9M108.6 222.2v3.2M108.6 233v32.4h-62.2M115.6 222.2v3.2M115.6 233v35.6h-69.2M122.6 233v40.7h-85.1M122.6 222.2v3.2M129.5 222.2h-76.8v3.2M129.5 233v44.5h-92M243.8 255.3v10.1h-44.4"/>
<path d="M251.5 243.8h-7.7v3.8M251.5 240v7.6M251.5 255.3v13.9h-52.1"/>
</g>
<path d="M197.5 109.9l1.2 1.2M198.7 109.9l-1.2 1.2M197.5 160.7l1.2 1.2M198.7 160.7l-1.2 1.2" fill="none" stroke="#000084" stroke-width=".18"/>
<g fill="#009600" stroke="#009600" stroke-width=".18">
<circle cx="219.1" cy="87" r=".46"/>
<circle cx="313.7" cy="142.2" r=".46"/>
<circle cx="318.8" cy="142.2" r=".46"/>
<circle cx="320" cy="142.2" r=".46"/>
<circle cx="316.2" cy="142.2" r=".46"/>
<circle cx="167.6" cy="84.5" r=".46"/>
<circle cx="172.7" cy="84.5" r=".46"/>
<circle cx="147.3" cy="84.5" r=".46"/>
<circle cx="165.1" cy="84.5" r=".46"/>
<circle cx="149.9" cy="84.5" r=".46"/>
<circle cx="212.7" cy="77.5" r=".46"/>
<circle cx="219.1" cy="77.5" r=".46"/>
<circle cx="212.7" cy="87" r=".46"/>
<circle cx="206.4" cy="77.5" r=".46"/>
<circle cx="122.6" cy="55.9" r=".46"/>
<circle cx="128.9" cy="55.9" r=".46"/>
<circle cx="128.9" cy="77.5" r=".46"/>
<circle cx="122.6" cy="77.5" r=".46"/>
<circle cx="128.9" cy="33.7" r=".46"/>
<circle cx="122.6" cy="46.4" r=".46"/>
<circle cx="122.6" cy="33.7" r=".46"/>
<circle cx="122.6" cy="68.6" r=".46"/>
<circle cx="321.3" cy="142.2" r=".46"/>
<circle cx="326.4" cy="142.2" r=".46"/>
<circle cx="323.8" cy="142.2" r=".46"/>
<circle cx="206.4" cy="48.9" r=".46"/>
<circle cx="206.4" cy="60.3" r=".46"/>
<circle cx="200" cy="60.3" r=".46"/>
<circle cx="212.7" cy="48.9" r=".46"/>
<circle cx="212.7" cy="60.3" r=".46"/>
<circle cx="200" cy="48.9" r=".46"/>
<circle cx="193.7" cy="48.9" r=".46"/>
<circle cx="122.6" cy="90.2" r=".46"/>
<circle cx="122.6" cy="222.2" r=".46"/>
<circle cx="167.6" cy="177.8" r=".46"/>
<circle cx="129.5" cy="222.2" r=".46"/>
<circle cx="251.5" cy="243.8" r=".46"/>
<circle cx="255.9" cy="183.5" r=".46"/>
<circle cx="180.3" cy="84.5" r=".46"/>
<circle cx="175.3" cy="84.5" r=".46"/>
<circle cx="170.2" cy="84.5" r=".46"/>
<circle cx="157.5" cy="84.5" r=".46"/>
<circle cx="116.2" cy="46.4" r=".46"/>
<circle cx="103.5" cy="46.4" r=".46"/>
<circle cx="109.9" cy="46.4" r=".46"/>
<circle cx="116.2" cy="68.6" r=".46"/>
<circle cx="116.2" cy="55.9" r=".46"/>
<circle cx="109.9" cy="33.7" r=".46"/>
<circle cx="116.2" cy="33.7" r=".46"/>
<circle cx="103.5" cy="33.7" r=".46"/>
<circle cx="73.7" cy="222.2" r=".46"/>
<circle cx="66.7" cy="222.2" r=".46"/>
<circle cx="59.7" cy="222.2" r=".46"/>
<circle cx="108.6" cy="222.2" r=".46"/>
<circle cx="115.6" cy="222.2" r=".46"/>
<circle cx="85.1" cy="163.2" r=".46"/>
<circle cx="87.6" cy="222.2" r=".46"/>
<circle cx="80.6" cy="222.2" r=".46"/>
<circle cx="94.6" cy="222.2" r=".46"/>
<circle cx="78.1" cy="33.7" r=".46"/>
<circle cx="84.5" cy="33.7" r=".46"/>
<circle cx="84.5" cy="46.4" r=".46"/>
<circle cx="90.8" cy="33.7" r=".46"/>
<circle cx="97.2" cy="33.7" r=".46"/>
<circle cx="78.1" cy="46.4" r=".46"/>
<circle cx="90.8" cy="46.4" r=".46"/>
<circle cx="97.2" cy="46.4" r=".46"/>
<circle cx="116.2" cy="77.5" r=".46"/>
<circle cx="109.9" cy="77.5" r=".46"/>
<circle cx="116.2" cy="90.2" r=".46"/>
<circle cx="103.5" cy="90.2" r=".46"/>
<circle cx="103.5" cy="77.5" r=".46"/>
<circle cx="109.9" cy="90.2" r=".46"/>
</g>
<use href="#words"/>
</svg>
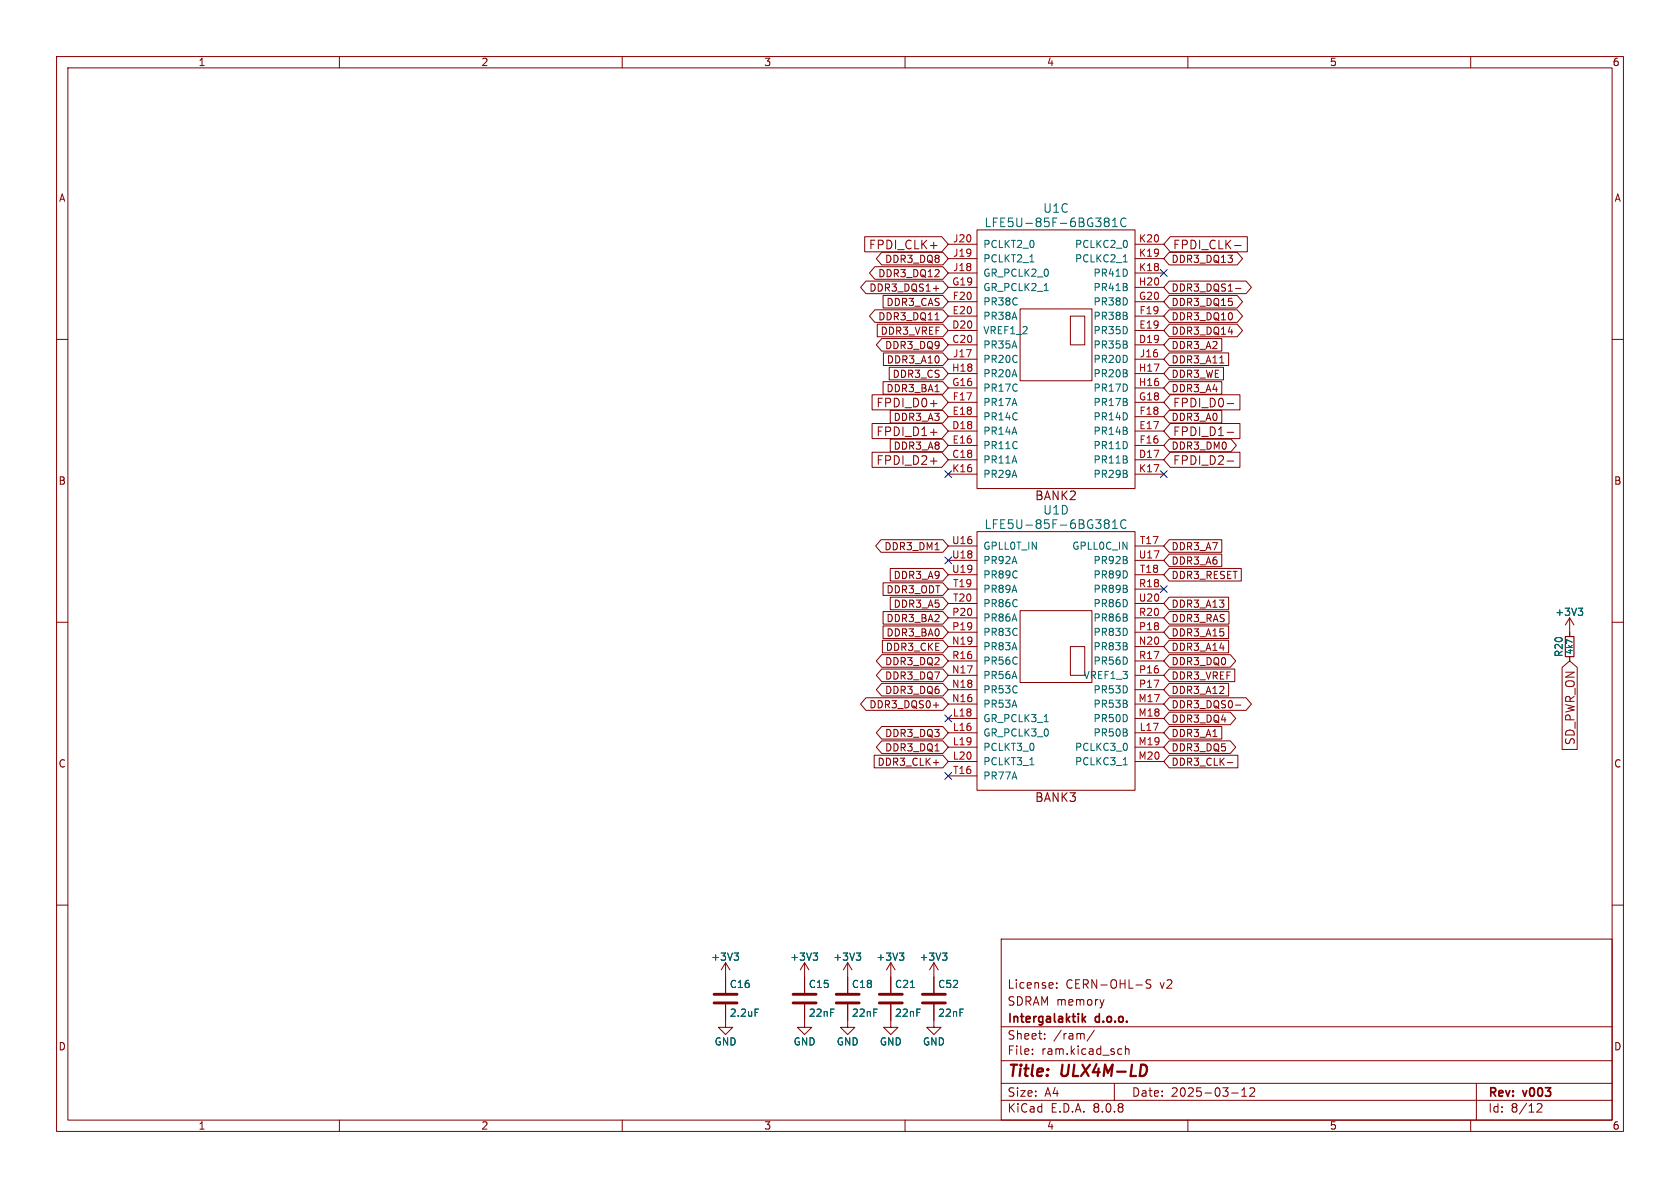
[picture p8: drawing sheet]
<svg xmlns="http://www.w3.org/2000/svg" width="297mm" height="210mm" viewBox="0 0 297 210" stroke-linecap="round" stroke-linejoin="round" font-family="sans-serif">
<defs><g id="words">
<g font-size="2.8" fill="#840000">
<text x="178" y="190.9">Title:</text>
<text x="187.7" y="190.9">ULX4M-LD</text>
</g>
<g font-size="2.1" fill="#006464">
<text x="174" y="40.4">LFE5U-85F-6BG381C</text>
<text x="184.3" y="37.8">U1C</text>
<text x="174" y="93.7">LFE5U-85F-6BG381C</text>
<text x="184.3" y="91.2">U1D</text>
</g>
<g font-size="2.1" fill="#840000">
<text x="153.6" y="44.3">FPDI_CLK+</text>
<text x="207.3" y="44.3">FPDI_CLK-</text>
<text x="154.9" y="72.2">FPDI_D0+</text>
<text x="154.9" y="77.3">FPDI_D1+</text>
<text x="207.3" y="72.2">FPDI_D0-</text>
<text x="207.3" y="77.3">FPDI_D1-</text>
<text x="154.9" y="82.4">FPDI_D2+</text>
<text x="207.3" y="82.4">FPDI_D2-</text>
<text x="182.9" y="88.7">BANK2</text>
<text x="278.6" y="131.8" transform="rotate(-90 278.6 131.8)">SD_PWR_ON</text>
<text x="182.9" y="142">BANK3</text>
<text x="178" y="178">SDRAM memory</text>
<text x="178" y="175">License:</text>
<text x="188.4" y="175">CERN-OHL-S</text>
<text x="205.1" y="175">v2</text>
<text x="178" y="184">Sheet:</text>
<text x="178" y="181.2">Intergalaktik</text>
<text x="186.2" y="184">/ram/</text>
<text x="193.7" y="181.2">d.o.o.</text>
<text x="178" y="186.7">File:</text>
<text x="184.1" y="186.7">ram.kicad_sch</text>
<text x="178" y="196.9">KiCad</text>
<text x="178" y="194.1">Size:</text>
<text x="184.7" y="194.1">A4</text>
<text x="185.7" y="196.9">E.D.A.</text>
<text x="193.3" y="196.9">8.0.8</text>
<text x="200" y="194.1">Date:</text>
<text x="207" y="194.1">2025-03-12</text>
<text x="263" y="194.3">Rev:</text>
<text x="263" y="196.9">Id:</text>
<text x="267.1" y="196.9">8/12</text>
<text x="269.4" y="194.3">v003</text>
</g>
<g font-size="1.8" fill="#840000">
<text x="35" y="11.9">1</text>
<text x="85" y="11.9">2</text>
<text x="135" y="11.9">3</text>
<text x="185" y="11.9">4</text>
<text x="235" y="11.9">5</text>
<text x="285" y="11.9">6</text>
<text x="10.3" y="35.9">A</text>
<text x="285.3" y="35.9">A</text>
<text x="156.4" y="46.7">DDR3_DQ8</text>
<text x="207" y="46.7">DDR3_DQ13</text>
<text x="153.6" y="51.8">DDR3_DQS1+</text>
<text x="155.2" y="49.2">DDR3_DQ12</text>
<text x="207" y="51.8">DDR3_DQS1-</text>
<text x="155.2" y="56.8">DDR3_DQ11</text>
<text x="155.6" y="59.4">DDR3_VREF</text>
<text x="156.6" y="54.3">DDR3_CAS</text>
<text x="207" y="54.3">DDR3_DQ15</text>
<text x="207" y="59.4">DDR3_DQ14</text>
<text x="207" y="56.8">DDR3_DQ10</text>
<text x="156.4" y="61.9">DDR3_DQ9</text>
<text x="156.7" y="64.5">DDR3_A10</text>
<text x="207" y="64.5">DDR3_A11</text>
<text x="207" y="61.9">DDR3_A2</text>
<text x="156.6" y="69.5">DDR3_BA1</text>
<text x="157.7" y="67">DDR3_CS</text>
<text x="207" y="67">DDR3_WE</text>
<text x="207" y="69.5">DDR3_A4</text>
<text x="157.9" y="74.6">DDR3_A3</text>
<text x="207" y="74.6">DDR3_A0</text>
<text x="157.9" y="79.7">DDR3_A8</text>
<text x="207" y="79.7">DDR3_DM0</text>
<text x="10.3" y="85.9">B</text>
<text x="285.3" y="85.9">B</text>
<text x="156.2" y="97.5">DDR3_DM1</text>
<text x="207" y="100">DDR3_A6</text>
<text x="207" y="97.5">DDR3_A7</text>
<text x="156.6" y="105.1">DDR3_ODT</text>
<text x="157.9" y="107.6">DDR3_A5</text>
<text x="157.9" y="102.6">DDR3_A9</text>
<text x="207" y="102.6">DDR3_RESET</text>
<text x="207" y="107.6">DDR3_A13</text>
<text x="156.6" y="110.2">DDR3_BA2</text>
<text x="156.6" y="112.7">DDR3_BA0</text>
<text x="207" y="110.2">DDR3_RAS</text>
<text x="207" y="112.7">DDR3_A15</text>
<text x="156.4" y="117.8">DDR3_DQ2</text>
<text x="156.5" y="115.3">DDR3_CKE</text>
<text x="207" y="115.3">DDR3_A14</text>
<text x="207" y="117.8">DDR3_DQ0</text>
<text x="153.6" y="125.4">DDR3_DQS0+</text>
<text x="156.4" y="120.3">DDR3_DQ7</text>
<text x="156.4" y="122.9">DDR3_DQ6</text>
<text x="207" y="120.3">DDR3_VREF</text>
<text x="207" y="122.9">DDR3_A12</text>
<text x="207" y="125.4">DDR3_DQS0-</text>
<text x="156.4" y="130.5">DDR3_DQ3</text>
<text x="207" y="128">DDR3_DQ4</text>
<text x="207" y="130.5">DDR3_A1</text>
<text x="10.3" y="135.9">C</text>
<text x="155" y="135.6">DDR3_CLK+</text>
<text x="156.4" y="133">DDR3_DQ1</text>
<text x="207" y="133">DDR3_DQ5</text>
<text x="207" y="135.6">DDR3_CLK-</text>
<text x="285.3" y="135.9">C</text>
<text x="10.3" y="185.9">D</text>
<text x="285.3" y="185.9">D</text>
<text x="35" y="199.9">1</text>
<text x="85" y="199.9">2</text>
<text x="135" y="199.9">3</text>
<text x="185" y="199.9">4</text>
<text x="235" y="199.9">5</text>
<text x="285" y="199.9">6</text>
</g>
<g font-size="1.8" fill="#a90000">
<text x="168.4" y="45.5">J19</text>
<text x="168.4" y="42.9">J20</text>
<text x="201.3" y="45.5">K19</text>
<text x="201.3" y="42.9">K20</text>
<text x="168.2" y="50.5">G19</text>
<text x="168.3" y="53.1">F20</text>
<text x="168.4" y="48">J18</text>
<text x="201.2" y="50.5">H20</text>
<text x="201.3" y="53.1">G20</text>
<text x="201.3" y="48">K18</text>
<text x="168.2" y="58.2">D20</text>
<text x="168.3" y="55.6">E20</text>
<text x="201.3" y="58.2">E19</text>
<text x="201.3" y="55.6">F19</text>
<text x="168.2" y="65.8">H18</text>
<text x="168.2" y="60.7">C20</text>
<text x="168.4" y="63.2">J17</text>
<text x="201.2" y="65.8">H17</text>
<text x="201.3" y="60.7">D19</text>
<text x="201.4" y="63.2">J16</text>
<text x="168.2" y="68.3">G16</text>
<text x="168.3" y="70.9">F17</text>
<text x="201.2" y="68.3">H16</text>
<text x="201.3" y="70.9">G18</text>
<text x="168.2" y="75.9">D18</text>
<text x="168.3" y="73.4">E18</text>
<text x="201.3" y="75.9">E17</text>
<text x="201.3" y="73.4">F18</text>
<text x="168.2" y="81">C18</text>
<text x="168.2" y="83.6">K16</text>
<text x="168.3" y="78.5">E16</text>
<text x="201.3" y="81">D17</text>
<text x="201.3" y="83.6">K17</text>
<text x="201.3" y="78.5">F16</text>
<text x="168.2" y="96.3">U16</text>
<text x="168.2" y="98.8">U18</text>
<text x="168.2" y="101.3">U19</text>
<text x="201.2" y="98.8">U17</text>
<text x="201.4" y="96.3">T17</text>
<text x="201.4" y="101.3">T18</text>
<text x="168.4" y="103.9">T19</text>
<text x="168.4" y="106.4">T20</text>
<text x="201.2" y="106.4">U20</text>
<text x="201.3" y="103.9">R18</text>
<text x="168.2" y="111.5">P19</text>
<text x="168.2" y="109">P20</text>
<text x="201.3" y="111.5">P18</text>
<text x="201.3" y="109">R20</text>
<text x="168.2" y="119.1">N17</text>
<text x="168.2" y="114">N19</text>
<text x="168.2" y="116.6">R16</text>
<text x="201.2" y="114">N20</text>
<text x="201.3" y="119.1">P16</text>
<text x="201.3" y="116.6">R17</text>
<text x="168.2" y="124.2">N16</text>
<text x="168.2" y="121.7">N18</text>
<text x="201.2" y="124.2">M17</text>
<text x="201.3" y="121.7">P17</text>
<text x="168.4" y="129.3">L16</text>
<text x="168.4" y="126.7">L18</text>
<text x="168.4" y="131.8">L19</text>
<text x="201.2" y="126.7">M18</text>
<text x="201.2" y="131.8">M19</text>
<text x="201.4" y="129.3">L17</text>
<text x="168.4" y="134.4">L20</text>
<text x="168.4" y="136.9">T16</text>
<text x="201.2" y="134.4">M20</text>
</g>
<g font-size="1.8" fill="#006464">
<text x="173.7" y="46.6">PCLKT2_1</text>
<text x="173.7" y="44">PCLKT2_0</text>
<text x="189.9" y="46.6">PCLKC2_1</text>
<text x="189.9" y="44">PCLKC2_0</text>
<text x="173.7" y="51.7">GR_PCLK2_1</text>
<text x="173.7" y="49.1">GR_PCLK2_0</text>
<text x="193.2" y="51.7">PR41B</text>
<text x="193.2" y="49.1">PR41D</text>
<text x="173.7" y="59.3">VREF1_2</text>
<text x="173.7" y="56.7">PR38A</text>
<text x="173.7" y="54.2">PR38C</text>
<text x="193.2" y="59.3">PR35D</text>
<text x="193.2" y="56.7">PR38B</text>
<text x="193.2" y="54.2">PR38D</text>
<text x="173.7" y="61.8">PR35A</text>
<text x="173.7" y="64.4">PR20C</text>
<text x="193.2" y="61.8">PR35B</text>
<text x="193.2" y="64.4">PR20D</text>
<text x="173.7" y="72">PR17A</text>
<text x="173.7" y="69.4">PR17C</text>
<text x="173.7" y="66.9">PR20A</text>
<text x="193.2" y="72">PR17B</text>
<text x="193.2" y="69.4">PR17D</text>
<text x="193.2" y="66.9">PR20B</text>
<text x="173.7" y="77.1">PR14A</text>
<text x="173.7" y="74.5">PR14C</text>
<text x="193.2" y="77.1">PR14B</text>
<text x="193.2" y="74.5">PR14D</text>
<text x="173.7" y="82.1">PR11A</text>
<text x="173.7" y="79.6">PR11C</text>
<text x="193.2" y="82.1">PR11B</text>
<text x="193.2" y="79.6">PR11D</text>
<text x="173.7" y="84.7">PR29A</text>
<text x="193.2" y="84.7">PR29B</text>
<text x="173.7" y="97.4">GPLL0T_IN</text>
<text x="173.7" y="99.9">PR92A</text>
<text x="189.5" y="97.4">GPLL0C_IN</text>
<text x="193.2" y="99.9">PR92B</text>
<text x="173.7" y="105">PR89A</text>
<text x="173.7" y="107.5">PR86C</text>
<text x="173.7" y="102.5">PR89C</text>
<text x="193.2" y="105">PR89B</text>
<text x="193.2" y="102.5">PR89D</text>
<text x="193.2" y="107.5">PR86D</text>
<text x="173.7" y="112.6">PR83C</text>
<text x="173.7" y="110.1">PR86A</text>
<text x="193.2" y="112.6">PR83D</text>
<text x="193.2" y="110.1">PR86B</text>
<text x="274.9" y="109.1">+3V3</text>
<text x="173.7" y="115.2">PR83A</text>
<text x="173.7" y="117.7">PR56C</text>
<text x="193.2" y="115.2">PR83B</text>
<text x="193.2" y="117.7">PR56D</text>
<text x="276.5" y="116.2" transform="rotate(-90 276.5 116.2)">R20</text>
<text x="173.7" y="125.3">PR53A</text>
<text x="173.7" y="120.2">PR56A</text>
<text x="173.7" y="122.8">PR53C</text>
<text x="191.5" y="120.2">VREF1_3</text>
<text x="193.2" y="125.3">PR53B</text>
<text x="193.2" y="122.8">PR53D</text>
<text x="173.7" y="130.4">GR_PCLK3_0</text>
<text x="173.7" y="127.9">GR_PCLK3_1</text>
<text x="193.2" y="130.4">PR50B</text>
<text x="193.2" y="127.9">PR50D</text>
<text x="173.7" y="132.9">PCLKT3_0</text>
<text x="173.7" y="135.5">PCLKT3_1</text>
<text x="189.9" y="132.9">PCLKC3_0</text>
<text x="189.9" y="135.5">PCLKC3_1</text>
<text x="173.7" y="138">PR77A</text>
<text x="125.6" y="170">+3V3</text>
<text x="139.6" y="170">+3V3</text>
<text x="147.2" y="170">+3V3</text>
<text x="154.8" y="170">+3V3</text>
<text x="162.5" y="170">+3V3</text>
<text x="128.9" y="174.9">C16</text>
<text x="128.9" y="179.9">2.2uF</text>
<text x="142.9" y="174.9">C15</text>
<text x="142.9" y="179.9">22nF</text>
<text x="150.5" y="174.9">C18</text>
<text x="150.5" y="179.9">22nF</text>
<text x="158.1" y="174.9">C21</text>
<text x="158.1" y="179.9">22nF</text>
<text x="165.7" y="174.9">C52</text>
<text x="165.7" y="179.9">22nF</text>
<text x="126.2" y="185">GND</text>
<text x="140.2" y="185">GND</text>
<text x="147.8" y="185">GND</text>
<text x="155.4" y="185">GND</text>
<text x="163.1" y="185">GND</text>
</g>
<text font-size="1.4" fill="#006464" x="278.2" y="115.8" transform="rotate(-90 278.2 115.8)">4k7</text>
</g></defs>
<g fill="none" stroke="#840000" stroke-width=".18">
<path d="M10 10h277v190h-277zM12 12h273v186h-273zM60 10v2M110 10v2M160 10v2M210 10v2M260 10v2M152.9 41.8h13.6l1.1 1.4-1.1 1.3h-13.6zM153.1 49.7h13.6l.9 1.1-.9 1.1h-13.6l-1-1.1zM154.7 47.1h12l.9 1.2-.9 1.1h-12l-1-1.1zM154.7 54.8h12l.9 1.1-.9 1.1h-12l-1-1.1zM155.1 57.3h11.6l.9 1.1-.9 1.1h-11.6z"/>
<path d="M155.9 44.6h10.8l.9 1.1-.9 1.1h-10.8l-1-1.1zM155.9 59.8h10.8l.9 1.2-.9 1.1h-10.8l-1-1.1zM156.1 52.2h10.6l.9 1.1-.9 1.2h-10.6zM164.5 43.4h1.2M165 51h1M165.3 56.6h.7M167.6 58.4h5.1M167.6 55.9h5.1M167.6 53.3h5.1M167.6 50.8h5.1M167.6 48.3h5.1M167.6 45.7h5.1"/>
<path d="M167.6 43.2h5.1M172.7 40.6h28v45.8h-28zM180.3 54.6h12.7v12.7h-12.7zM189.2 55.9h2.6v5.1h-2.6zM200.7 58.4h5M200.7 55.9h5M200.7 53.3h5M200.7 50.8h5M200.7 48.3h5M200.7 45.7h5M200.7 43.2h5M206.7 49.7h13.6l.9 1.1-.9 1.1h-13.6l-1-1.1z"/>
<path d="M206.7 44.6h12l1 1.1-1 1.1h-12l-1-1.1zM206.7 52.2h12l1 1.1-1 1.2h-12l-1-1.2zM206.7 57.3h12l1 1.1-1 1.1h-12l-1-1.1zM206.7 59.8h9.3v2.3h-9.3l-1-1.1zM206.7 54.8h12l1 1.1-1 1.1h-12l-1-1.1zM206.9 41.8h13.6v2.7h-13.6l-1.2-1.3zM218.2 43.4h1.2M218.4 51h1M10 60h2M154.2 69.8h12.3l1.1 1.3-1.1 1.4h-12.3zM154.2 79.9h12.3l1.1 1.4-1.1 1.3h-12.3zM154.2 74.9h12.3l1.1 1.3-1.1 1.3h-12.3z"/>
<path d="M156.1 67.5h10.6l.9 1.1-.9 1.1h-10.6zM156.2 62.4h10.5l.9 1.1-.9 1.1h-10.5zM157.2 64.9h9.5l.9 1.1-.9 1.2h-9.5zM157.4 72.5h9.3l.9 1.2-.9 1.1h-9.3zM157.4 77.6h9.3l.9 1.1-.9 1.2h-9.3zM164.5 71.3h1.2M164.5 76.4h1.2M165.3 69.3h.7M167.6 61h5.1M167.6 76.2h5.1M167.6 78.7h5.1M167.6 73.7h5.1"/>
<path d="M167.6 71.1h5.1M167.6 68.6h5.1M167.6 66h5.1M167.6 63.5h5.1M200.7 61h5M200.7 76.2h5M200.7 78.7h5M200.7 73.7h5M200.7 71.1h5M200.7 68.6h5M200.7 66h5M200.7 63.5h5"/>
<path d="M206.7 64.9h9.6v2.3h-9.6l-1-1.2zM206.7 67.5h9.3v2.2h-9.3l-1-1.1zM206.7 62.4h10.5v2.2h-10.5l-1-1.1zM206.7 77.6h10.9l1 1.1-1 1.2h-10.9l-1-1.2zM206.7 72.5h9.3v2.3h-9.3l-1-1.1zM206.9 69.8h12.3v2.7h-12.3l-1.2-1.4zM206.9 74.9h12.3v2.6h-12.3l-1.2-1.3zM206.9 79.9h12.3v2.7h-12.3l-1.2-1.3zM215.6 64.2h.8M216.9 71.3h1.2M216.9 76.4h1.2M285 60h2"/>
<path d="M155.8 95.4h10.9l.9 1.1-.9 1.1h-10.9l-1-1.1zM164.5 81.5h1.2M167.6 81.3h5.1M167.6 83.8h5.1M167.6 96.5h5.1M167.6 99.1h5.1M172.7 94h28v45.7h-28zM200.7 81.3h5M200.7 83.8h5M200.7 96.5h5M200.7 99.1h5M206.7 97.9h9.3v2.3h-9.3l-1-1.1z"/>
<path d="M206.7 95.4h9.3v2.2h-9.3l-1-1.1zM216.9 81.5h1.2M10 110h2M155.9 118.3h10.8l.9 1.1-.9 1.1h-10.8l-1-1.1zM155.9 115.7h10.8l.9 1.1-.9 1.2h-10.8l-1-1.2zM156 113.2h10.7l.9 1.1-.9 1.1h-10.7zM156.1 108.1h10.6l.9 1.1-.9 1.1h-10.6zM156.1 110.6h10.6l.9 1.2-.9 1.1h-10.6zM156.1 103h10.6l.9 1.1-.9 1.2h-10.6zM157.4 105.6h9.3l.9 1.1-.9 1.1h-9.3zM157.4 100.5h9.3l.9 1.1-.9 1.1h-9.3zM167.6 119.4h5.1"/>
<path d="M167.6 114.3h5.1M167.6 111.8h5.1M167.6 109.2h5.1M167.6 116.8h5.1M167.6 104.1h5.1M167.6 101.6h5.1M167.6 106.7h5.1M180.3 108h12.7v12.7h-12.7zM189.2 114.3h2.6v5.1h-2.6zM200.7 119.4h5M200.7 114.3h5M200.7 111.8h5"/>
<path d="M200.7 109.2h5M200.7 116.8h5M200.7 104.1h5M200.7 101.6h5M200.7 106.7h5M206.7 118.3h11.6v2.2h-11.6l-1-1.1zM206.7 100.5h12.7v2.2h-12.7l-1-1.1zM206.7 105.6h10.5v2.2h-10.5l-1-1.1zM206.7 113.2h10.5v2.2h-10.5l-1-1.1zM206.7 108.1h10.6v2.2h-10.6l-1-1.1zM206.7 110.6h10.5v2.3h-10.5l-1-1.1zM206.7 115.7h10.8l1 1.1-1 1.2h-10.8l-1-1.2z"/>
<path d="M276.2 118l1.3-1.2 1.3 1.2v14.5h-2.6zM277.5 109.2v3.3M277.5 116.1v.7M277.5 109.2l-.8 1.3M277.5 109.2l.8 1.3M285 110h2M153.1 123.3h13.6l.9 1.2-.9 1.1h-13.6l-1-1.1zM154.5 133.5h12.2l.9 1.1-.9 1.1h-12.2zM155.9 128.4h10.8l.9 1.1-.9 1.2h-10.8l-1-1.2zM155.9 120.8h10.8l.9 1.1-.9 1.1h-10.8l-1-1.1zM155.9 131h10.8l.9 1.1-.9 1.1h-10.8l-1-1.1zM165 124.6h1"/>
<path d="M165 134.8h1M167.6 129.5h5.1M167.6 127h5.1M167.6 132.1h5.1M167.6 134.6h5.1M167.6 124.5h5.1M167.6 121.9h5.1M167.6 137.2h5.1M200.7 129.5h5M200.7 127h5M200.7 132.1h5M200.7 134.6h5"/>
<path d="M200.7 124.5h5M200.7 121.9h5M206.7 125.9h10.8l1 1.1-1 1.1h-10.8l-1-1.1zM206.7 120.8h10.5v2.2h-10.5l-1-1.1zM206.7 128.4h9.3v2.3h-9.3l-1-1.2zM206.7 123.3h13.6l.9 1.2-.9 1.1h-13.6l-1-1.1zM206.7 131h10.8l1 1.1-1 1.1h-10.8l-1-1.1zM206.7 133.5h12.1v2.2h-12.1l-1-1.1zM217 134.8h.9M218.4 124.6h1M10 160h2M128.3 177.5v4.1h1.2l-1.2 1.3-1.3-1.3h1.3"/>
<path d="M128.3 170.2v5.3M128.3 170.2l-.8 1.3M128.3 170.2l.7 1.3M142.2 177.5v4.1h1.3l-1.3 1.3-1.2-1.3h1.2M142.2 170.2l-.7 1.3M142.2 170.2v5.3M142.2 170.2l.8 1.3M149.9 177.5v4.1h1.2l-1.2 1.3-1.3-1.3h1.3M149.9 170.2v5.3M149.9 170.2l-.8 1.3M149.9 170.2l.7 1.3M157.5 177.5v4.1h1.2l-1.2 1.3-1.3-1.3h1.3"/>
<path d="M157.5 170.2v5.3M157.5 170.2l-.8 1.3M157.5 170.2l.7 1.3M165.1 177.5v4.1h1.3l-1.3 1.3-1.3-1.3h1.3M165.1 170.2v5.3M165.1 170.2l-.8 1.3M165.1 170.2l.8 1.3M177 166h108v32h-108zM186.8 174.6v.1M186.8 173.8v.1M195.2 176.7l-.4 1M203.5 173.3l-.6-.1-.2 .1v.5l.6 .3 .2 .3-.3 .3-.6-.1"/>
<path d="M285 160h2M60 198v2M110 198v2M160 198v2M177 194.5h108M177 191.5h108M177 187.5h108M177 181.5h108M182.5 186.3v.1M182.5 185.5v.1M184.7 183.6v.1M184.7 182.8v.1"/>
<path d="M193.5 182.1l-1.3 2M197 191.5v3M197.9 185.4l.4 .1M198.3 186.3l-.4 .1M199 185.5l.2-.1 .3 .1 .1 .9M199 184.9v1.5M210 198v2M217.7 193.2h1.2M219.5 193.8h.9M219.5 192.7l.5-.4v1.5M221 192.4l.5-.1 .2 .1 .1 .3-.9 1.1h.9M260 198v2"/>
<path d="M261 191.5v6.5M271.7 195.2l.6-.1 .2 .1 .1 .3-.9 1.1h.9"/>
</g>
<path d="M191.3 179.2v1.5M191.9 179.7l-.6 .6M191.5 180.1l.4 .6" fill="none" stroke="#840000" stroke-width=".3"/>
<g fill="none" stroke="#006464" stroke-width=".18">
<path d="M195.5 38.5h.3l.3 .3-.3 .4M195.5 39.2h.3M195.8 39.2l.2 .1 .1 .5-.2 .2-.4 .1M196.7 39l.4-.5v1.6M199.1 38.7a.61 .61 0 0 0-.8 0 .61 .61 0 0 0-.2 .7 .57 .57 0 0 0 .3 .6 .57 .57 0 0 0 .7-.1M182.1 46.3h.7M184.6 51.4h.7M196.7 40.1h.8M198.6 46.3h.7M195.5 91.9h.3l.3 .3-.3 .3M195.5 92.5h.3M195.8 92.5l.2 .2 .1 .4-.2 .2-.4 .1"/>
<path d="M196.7 92.3l.4-.4v1.5M196.7 93.4h.8M199.1 92a.61 .61 0 0 0-.8 0 .61 .61 0 0 0-.2 .8 .57 .57 0 0 0 .3 .5 .57 .57 0 0 0 .7 0M277 113.1l.9 .4M279 107.5h.8l-.4 .5M279.6 108l.2 .2v.3l-.2 .3M182.1 135.2h.7M184.6 127.6h.7M198.6 135.2h.7M129.8 168.5h.8l-.5 .5M130.3 169l.3 .2v.3l-.3 .2M133.5 178.4h.6"/>
<path d="M143.8 168.5h.7l-.4 .5M144.3 169l.2 .2v.3l-.2 .2M151.4 168.5h.8l-.5 .5M151.9 169l.3 .2v.3l-.3 .2M159 168.5h.8l-.4 .5M159.5 169l.3 .2v.3l-.3 .2M160.9 174.6h.8M166.6 168.5h.8l-.4 .5M167.2 169l.2 .2v.3l-.2 .2"/>
</g>
<path d="M276.7 112.5h1.6v3.6h-1.6z" fill="none" stroke="#840000" stroke-width=".2"/>
<path d="M126.2 177.3h4.1M126.2 175.8h4.1M140.2 177.3h4.1M140.2 175.8h4.1M147.8 177.3h4.1M147.8 175.8h4.1M155.4 177.3h4.1M155.4 175.8h4.1M163.1 177.3h4M163.1 175.8h4" fill="none" stroke="#840000" stroke-width=".51"/>
<g fill="none" stroke="#000084" stroke-width=".18">
<path d="M205.1 47.7l1.2 1.2M206.3 47.7l-1.2 1.2M167 98.5l1.2 1.2M167 83.2l1.2 1.2M168.2 98.5l-1.2 1.2M168.2 83.2l-1.2 1.2M205.1 83.2l1.2 1.2M206.3 83.2l-1.2 1.2M205.1 103.5l1.2 1.2M206.3 103.5l-1.2 1.2M167 126.4l1.2 1.2M167 136.6l1.2 1.2"/>
<path d="M168.2 126.4l-1.2 1.2M168.2 136.6l-1.2 1.2"/>
</g>
<use href="#words"/>
</svg>
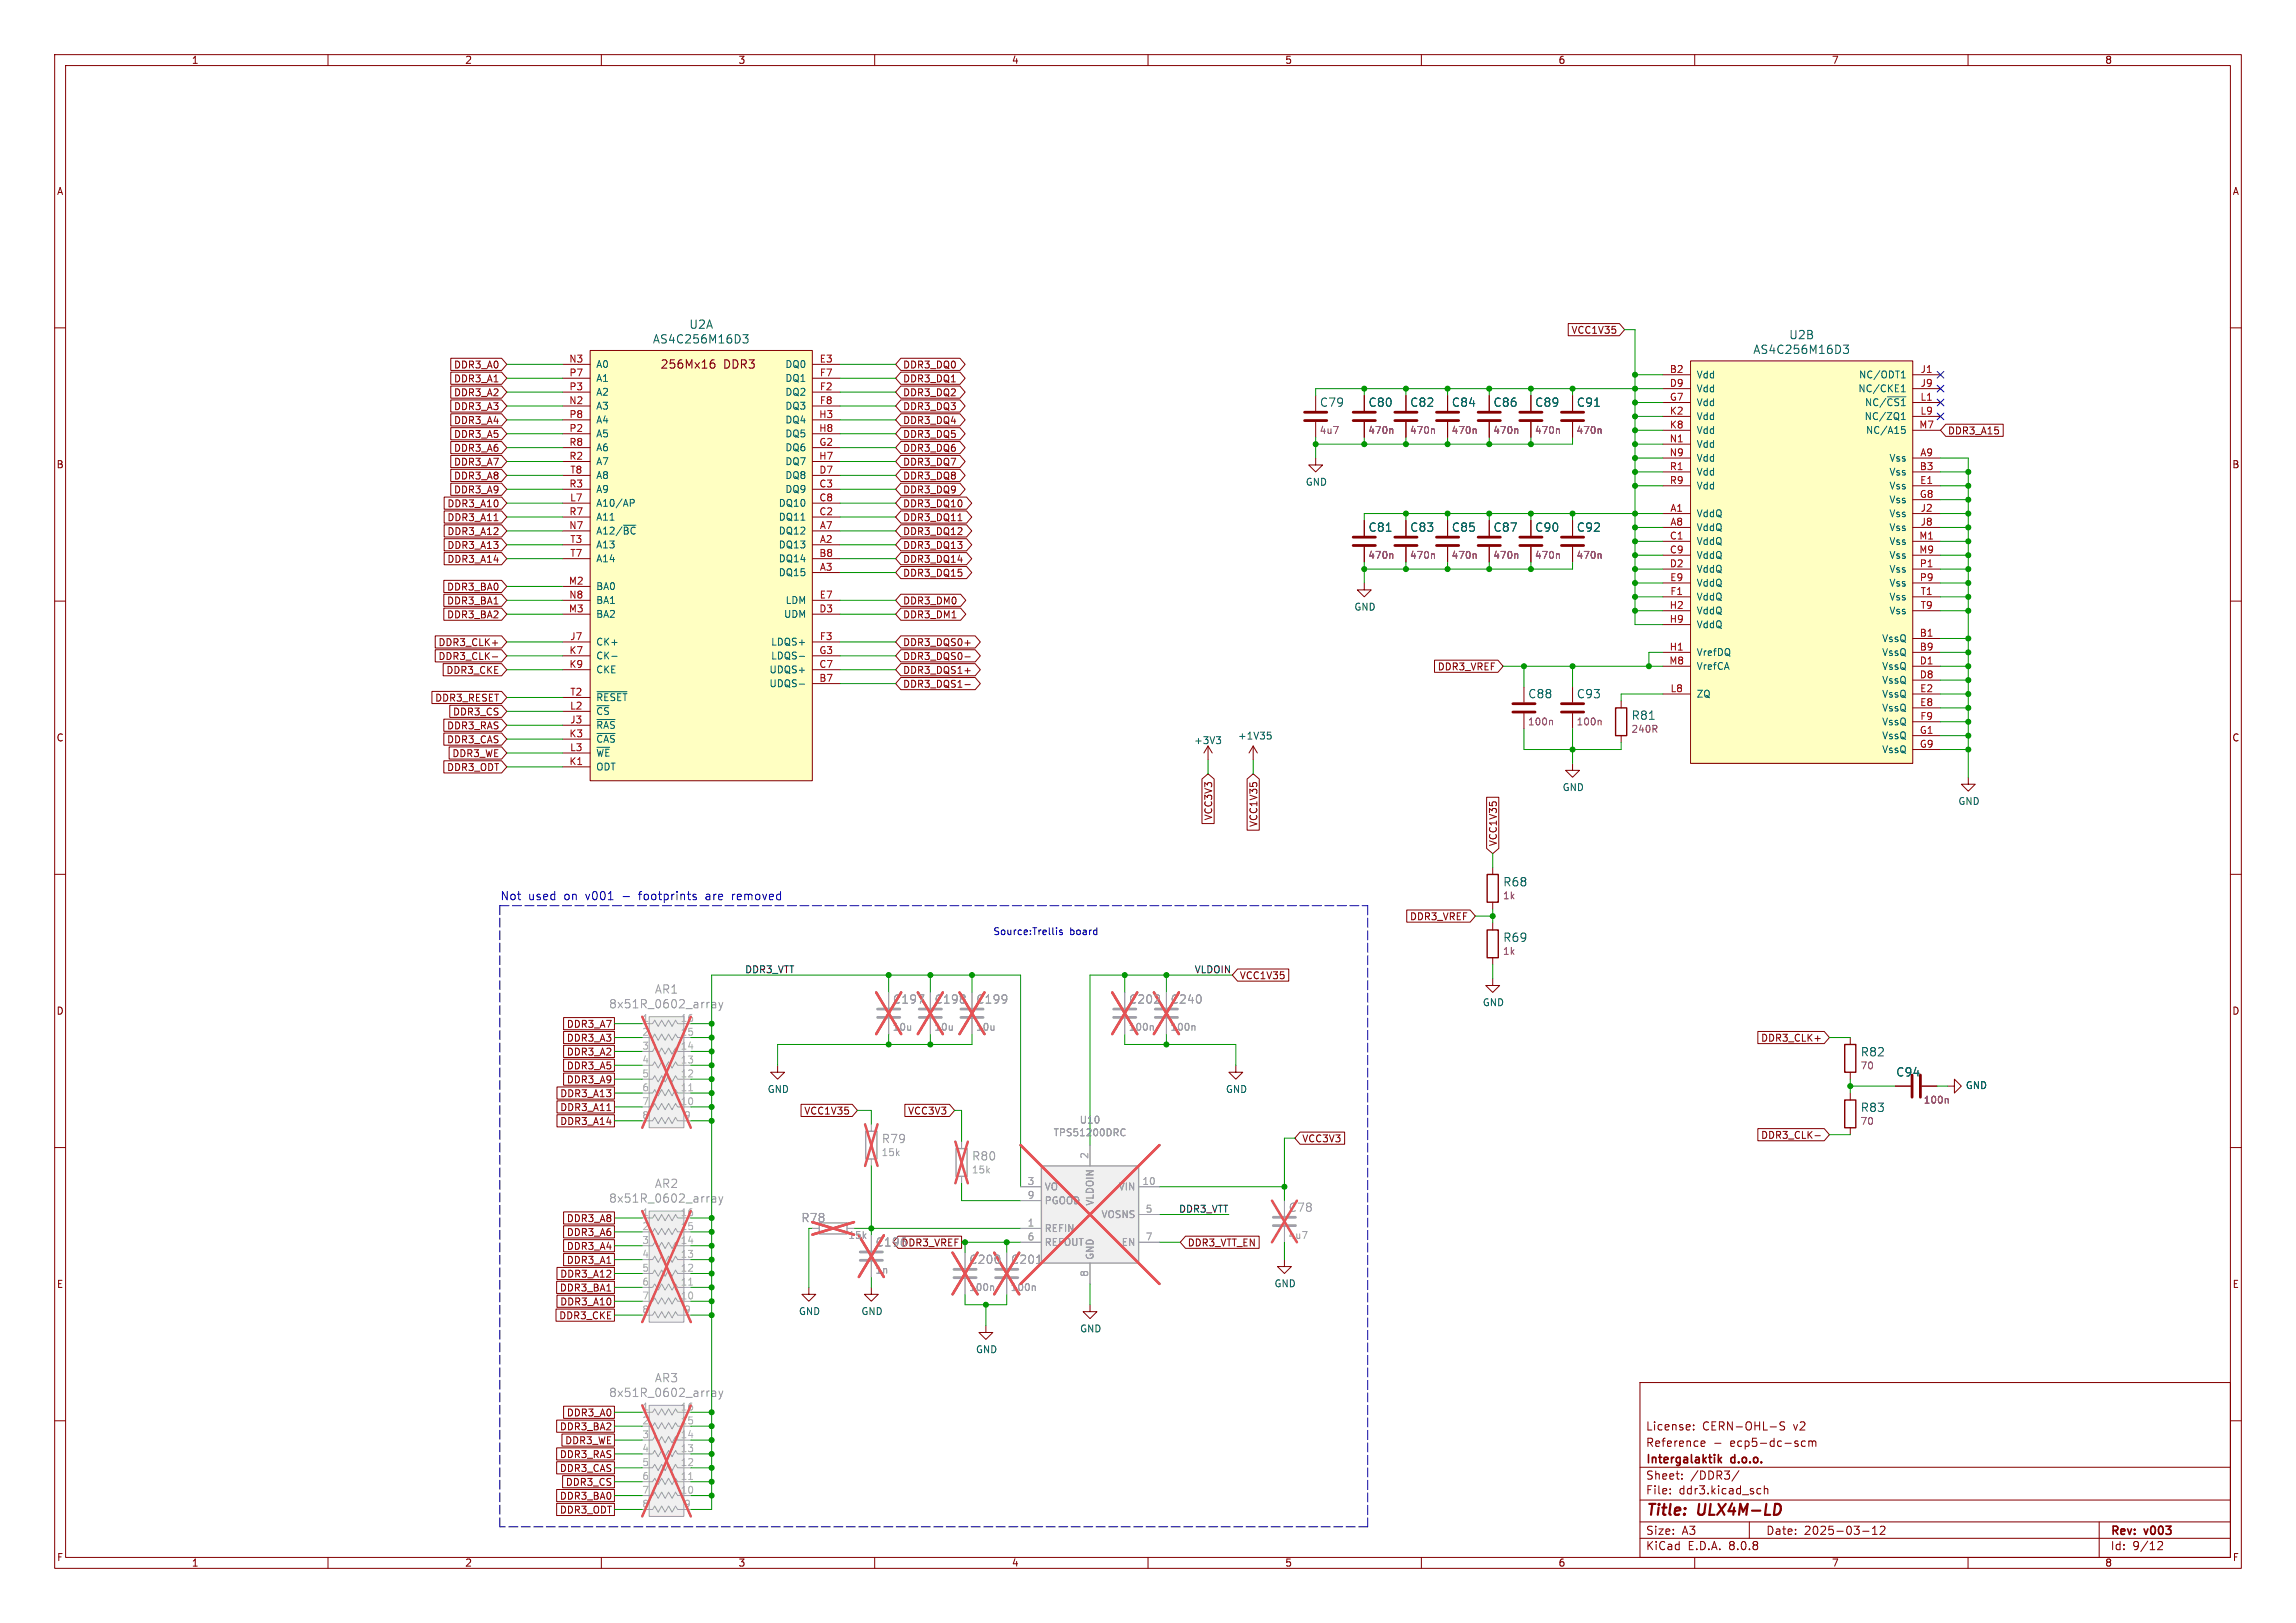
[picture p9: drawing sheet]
<svg xmlns="http://www.w3.org/2000/svg" width="420mm" height="297mm" viewBox="0 0 420 297" stroke-linecap="round" stroke-linejoin="round" font-family="sans-serif">
<defs><g id="words">
<g font-size="2.8" fill="#840000">
<text x="301" y="277.9">Title:</text>
<text x="310.6" y="277.9">ULX4M-LD</text>
</g>
<g font-size="2.1" fill="#006464">
<text x="119.3" y="63.1">AS4C256M16D3</text>
<text x="126" y="60.4">U2A</text>
<text x="320.6" y="65">AS4C256M16D3</text>
<text x="327.2" y="62.3">U2B</text>
<text x="241.4" y="74.7">C79</text>
<text x="250.2" y="74.7">C80</text>
<text x="257.9" y="74.7">C82</text>
<text x="265.5" y="74.7">C84</text>
<text x="273.1" y="74.7">C86</text>
<text x="280.7" y="74.7">C89</text>
<text x="288.3" y="74.7">C91</text>
<text x="250.2" y="97.5">C81</text>
<text x="257.9" y="97.5">C83</text>
<text x="265.5" y="97.5">C85</text>
<text x="273.1" y="97.5">C87</text>
<text x="280.7" y="97.5">C90</text>
<text x="288.3" y="97.5">C92</text>
<text x="279.5" y="128">C88</text>
<text x="288.3" y="128">C93</text>
<text x="298.4" y="131.9">R81</text>
<text x="274.9" y="162.4">R68</text>
<text x="274.9" y="172.6">R69</text>
<text x="340.3" y="193.5">R82</text>
<text x="346.8" y="197.2">C94</text>
<text x="340.3" y="203.7">R83</text>
</g>
<g font-size="2.1" fill="#840000">
<text x="120.7" y="67.7">256Mx16</text>
<text x="132.4" y="67.7">DDR3</text>
<text x="301" y="262">License:</text>
<text x="311.4" y="262">CERN-OHL-S</text>
<text x="328.1" y="262">v2</text>
<text x="301" y="268.2">Intergalaktik</text>
<text x="301" y="265">Reference</text>
<text x="316.5" y="265">ecp5-dc-scm</text>
<text x="316.7" y="268.2">d.o.o.</text>
<text x="301" y="273.7">File:</text>
<text x="301" y="271">Sheet:</text>
<text x="307.1" y="273.7">ddr3.kicad_sch</text>
<text x="309.2" y="271">/DDR3/</text>
<text x="301" y="281.1">Size:</text>
<text x="307.6" y="281.1">A3</text>
<text x="323" y="281.1">Date:</text>
<text x="330" y="281.1">2025-03-12</text>
<text x="386" y="281.3">Rev:</text>
<text x="392.4" y="281.3">v003</text>
<text x="301" y="283.9">KiCad</text>
<text x="308.7" y="283.9">E.D.A.</text>
<text x="316.3" y="283.9">8.0.8</text>
<text x="386" y="283.9">Id:</text>
<text x="390.1" y="283.9">9/12</text>
</g>
<g font-size="2.1" fill="#0000c2">
<text x="91.4" y="164.9">Not</text>
<text x="96.6" y="164.9">used</text>
<text x="103.2" y="164.9">on</text>
<text x="107.3" y="164.9">v001</text>
<text x="114.1" y="164.9">-</text>
<text x="117.3" y="164.9">footprints</text>
<text x="129.7" y="164.9">are</text>
<text x="134.6" y="164.9">removed</text>
</g>
<g font-size="2.1" fill="#989898">
<text x="111.3" y="184.7">8x51R_0602_array</text>
<text x="119.7" y="182">AR1</text>
<text x="163.3" y="183.9">C197</text>
<text x="170.9" y="183.9">C198</text>
<text x="178.5" y="183.9">C199</text>
<text x="206.4" y="183.9">C202</text>
<text x="214.1" y="183.9">C240</text>
<text x="161.2" y="209.4">R79</text>
<text x="177.7" y="212.6">R80</text>
<text x="111.3" y="220.3">8x51R_0602_array</text>
<text x="119.7" y="217.6">AR2</text>
<text x="235.6" y="222">C78</text>
<text x="146.5" y="223.9">R78</text>
<text x="160.1" y="228.3">C196</text>
<text x="177.2" y="231.5">C200</text>
<text x="184.8" y="231.5">C201</text>
<text x="111.3" y="255.9">8x51R_0602_array</text>
<text x="119.7" y="253.2">AR3</text>
</g>
<g font-size="1.8" fill="#840000">
<text x="35" y="11.9">1</text>
<text x="85" y="11.9">2</text>
<text x="135" y="11.9">3</text>
<text x="185" y="11.9">4</text>
<text x="235" y="11.9">5</text>
<text x="285" y="11.9">6</text>
<text x="335" y="11.9">7</text>
<text x="385" y="11.9">8</text>
<text x="10.3" y="35.9">A</text>
<text x="408.3" y="35.9">A</text>
<text x="287.4" y="61.3">VCC1V35</text>
<text x="83" y="67.6">DDR3_A0</text>
<text x="83" y="70.2">DDR3_A1</text>
<text x="165.1" y="70.2">DDR3_DQ1</text>
<text x="165.1" y="67.6">DDR3_DQ0</text>
<text x="83" y="75.2">DDR3_A3</text>
<text x="83" y="77.8">DDR3_A4</text>
<text x="83" y="72.7">DDR3_A2</text>
<text x="165.1" y="72.7">DDR3_DQ2</text>
<text x="165.1" y="77.8">DDR3_DQ4</text>
<text x="165.1" y="75.2">DDR3_DQ3</text>
<text x="83" y="80.3">DDR3_A5</text>
<text x="83" y="82.9">DDR3_A6</text>
<text x="165.1" y="82.9">DDR3_DQ6</text>
<text x="165.1" y="80.3">DDR3_DQ5</text>
<text x="356.2" y="79.7">DDR3_A15</text>
<text x="10.3" y="85.9">B</text>
<text x="83" y="85.4">DDR3_A7</text>
<text x="83" y="87.9">DDR3_A8</text>
<text x="165.1" y="85.4">DDR3_DQ7</text>
<text x="165.1" y="87.9">DDR3_DQ8</text>
<text x="408.2" y="85.9">B</text>
<text x="81.7" y="93">DDR3_A10</text>
<text x="81.7" y="95.6">DDR3_A11</text>
<text x="83" y="90.5">DDR3_A9</text>
<text x="165.1" y="93">DDR3_DQ10</text>
<text x="165.1" y="95.6">DDR3_DQ11</text>
<text x="165.1" y="90.5">DDR3_DQ9</text>
<text x="81.7" y="100.6">DDR3_A13</text>
<text x="81.7" y="98.1">DDR3_A12</text>
<text x="165.1" y="100.6">DDR3_DQ13</text>
<text x="165.1" y="98.1">DDR3_DQ12</text>
<text x="81.7" y="103.2">DDR3_A14</text>
<text x="165.1" y="103.2">DDR3_DQ14</text>
<text x="165.1" y="105.7">DDR3_DQ15</text>
<text x="81.7" y="108.3">DDR3_BA0</text>
<text x="81.7" y="113.3">DDR3_BA2</text>
<text x="81.7" y="110.8">DDR3_BA1</text>
<text x="165.1" y="113.3">DDR3_DM1</text>
<text x="165.1" y="110.8">DDR3_DM0</text>
<text x="80.1" y="118.4">DDR3_CLK+</text>
<text x="165.1" y="118.4">DDR3_DQS0+</text>
<text x="80.1" y="121">DDR3_CLK-</text>
<text x="81.6" y="123.5">DDR3_CKE</text>
<text x="165.1" y="123.5">DDR3_DQS1+</text>
<text x="165.1" y="121">DDR3_DQS0-</text>
<text x="262.9" y="122.9">DDR3_VREF</text>
<text x="79.5" y="128.6">DDR3_RESET</text>
<text x="82.8" y="131.1">DDR3_CS</text>
<text x="165.1" y="126">DDR3_DQS1-</text>
<text x="10.3" y="135.9">C</text>
<text x="81.7" y="133.7">DDR3_RAS</text>
<text x="81.7" y="136.2">DDR3_CAS</text>
<text x="408.2" y="135.9">C</text>
<text x="81.7" y="141.3">DDR3_ODT</text>
<text x="82.6" y="138.7">DDR3_WE</text>
<text x="221.9" y="150.2" transform="rotate(-90 221.9 150.2)">VCC3V3</text>
<text x="230.2" y="151.4" transform="rotate(-90 230.2 151.4)">VCC1V35</text>
<text x="274" y="154.9" transform="rotate(-90 274 154.9)">VCC1V35</text>
<text x="257.8" y="168.6">DDR3_VREF</text>
<text x="226.7" y="179.4">VCC1V35</text>
<text x="10.3" y="185.9">D</text>
<text x="408.2" y="185.9">D</text>
<text x="103.6" y="188.3">DDR3_A7</text>
<text x="103.6" y="190.8">DDR3_A3</text>
<text x="322" y="190.8">DDR3_CLK+</text>
<text x="103.6" y="195.9">DDR3_A5</text>
<text x="103.6" y="193.4">DDR3_A2</text>
<text x="102.4" y="201">DDR3_A13</text>
<text x="102.4" y="203.5">DDR3_A11</text>
<text x="103.6" y="198.4">DDR3_A9</text>
<text x="102.4" y="206.1">DDR3_A14</text>
<text x="147" y="204.2">VCC1V35</text>
<text x="166" y="204.2">VCC3V3</text>
<text x="238.1" y="209.2">VCC3V3</text>
<text x="322" y="208.6">DDR3_CLK-</text>
<text x="103.6" y="223.8">DDR3_A8</text>
<text x="103.6" y="226.4">DDR3_A6</text>
<text x="102.4" y="234">DDR3_A12</text>
<text x="103.6" y="231.5">DDR3_A1</text>
<text x="103.6" y="228.9">DDR3_A4</text>
<text x="164.8" y="228.3">DDR3_VREF</text>
<text x="217.2" y="228.3">DDR3_VTT_EN</text>
<text x="10.3" y="235.9">E</text>
<text x="102.3" y="236.5">DDR3_BA1</text>
<text x="102.4" y="239.1">DDR3_A10</text>
<text x="408.3" y="235.9">E</text>
<text x="102.2" y="241.6">DDR3_CKE</text>
<text x="102.3" y="261.9">DDR3_BA2</text>
<text x="103.6" y="259.4">DDR3_A0</text>
<text x="102.3" y="269.6">DDR3_CAS</text>
<text x="102.3" y="267">DDR3_RAS</text>
<text x="103.3" y="264.5">DDR3_WE</text>
<text x="102.3" y="274.6">DDR3_BA0</text>
<text x="103.4" y="272.1">DDR3_CS</text>
<text x="102.3" y="277.2">DDR3_ODT</text>
<text x="10.3" y="285.9">F</text>
<text x="35" y="286.9">1</text>
<text x="85" y="286.9">2</text>
<text x="135" y="286.9">3</text>
<text x="185" y="286.9">4</text>
<text x="235" y="286.9">5</text>
<text x="285" y="286.9">6</text>
<text x="335" y="286.9">7</text>
<text x="385" y="286.9">8</text>
<text x="408.3" y="285.9">F</text>
</g>
<g font-size="1.8" fill="#a90000">
<text x="104" y="66.4">N3</text>
<text x="104.1" y="71.5">P3</text>
<text x="104.1" y="69">P7</text>
<text x="149.8" y="66.4">E3</text>
<text x="149.9" y="71.5">F2</text>
<text x="149.9" y="69">F7</text>
<text x="305.4" y="68.3">B2</text>
<text x="305.4" y="70.9">D9</text>
<text x="351.2" y="68.3">J1</text>
<text x="351.2" y="70.9">J9</text>
<text x="104" y="74">N2</text>
<text x="104.1" y="76.6">P8</text>
<text x="149.8" y="76.6">H3</text>
<text x="149.9" y="74">F8</text>
<text x="305.4" y="73.4">G7</text>
<text x="305.4" y="75.9">K2</text>
<text x="351.2" y="73.4">L1</text>
<text x="351.2" y="75.9">L9</text>
<text x="104.1" y="79.1">P2</text>
<text x="104.1" y="81.7">R8</text>
<text x="149.8" y="79.1">H8</text>
<text x="149.8" y="81.7">G2</text>
<text x="305.3" y="81">N1</text>
<text x="305.3" y="83.6">N9</text>
<text x="305.4" y="78.5">K8</text>
<text x="351" y="78.5">M7</text>
<text x="351.2" y="83.6">A9</text>
<text x="104.1" y="84.2">R2</text>
<text x="104.1" y="89.3">R3</text>
<text x="104.2" y="86.7">T8</text>
<text x="149.8" y="84.2">H7</text>
<text x="149.8" y="89.3">C3</text>
<text x="149.8" y="86.7">D7</text>
<text x="305.4" y="86.1">R1</text>
<text x="305.4" y="88.6">R9</text>
<text x="351.1" y="86.1">B3</text>
<text x="351.1" y="88.6">E1</text>
<text x="104.1" y="94.4">R7</text>
<text x="104.2" y="91.8">L7</text>
<text x="149.8" y="94.4">C2</text>
<text x="149.8" y="91.8">C8</text>
<text x="305.5" y="93.7">A1</text>
<text x="351.1" y="91.2">G8</text>
<text x="351.2" y="93.7">J2</text>
<text x="104" y="96.9">N7</text>
<text x="104.2" y="99.4">T3</text>
<text x="104.2" y="102">T7</text>
<text x="149.8" y="102">B8</text>
<text x="149.9" y="99.4">A2</text>
<text x="149.9" y="96.9">A7</text>
<text x="305.4" y="98.8">C1</text>
<text x="305.4" y="101.3">C9</text>
<text x="305.5" y="96.3">A8</text>
<text x="351" y="98.8">M1</text>
<text x="351" y="101.3">M9</text>
<text x="351.2" y="96.3">J8</text>
<text x="104" y="107.1">M2</text>
<text x="149.9" y="104.5">A3</text>
<text x="305.4" y="103.9">D2</text>
<text x="305.4" y="106.4">E9</text>
<text x="351.1" y="103.9">P1</text>
<text x="351.1" y="106.4">P9</text>
<text x="104" y="112.1">M3</text>
<text x="104" y="109.6">N8</text>
<text x="149.8" y="112.1">D3</text>
<text x="149.8" y="109.6">E7</text>
<text x="305.3" y="111.5">H2</text>
<text x="305.5" y="109">F1</text>
<text x="351.2" y="109">T1</text>
<text x="351.2" y="111.5">T9</text>
<text x="104.1" y="119.8">K7</text>
<text x="104.2" y="117.2">J7</text>
<text x="149.8" y="119.8">G3</text>
<text x="149.9" y="117.2">F3</text>
<text x="305.3" y="119.1">H1</text>
<text x="305.3" y="114">H9</text>
<text x="351.1" y="116.6">B1</text>
<text x="351.1" y="119.1">B9</text>
<text x="104.1" y="122.3">K9</text>
<text x="149.8" y="124.8">B7</text>
<text x="149.8" y="122.3">C7</text>
<text x="305.3" y="121.7">M8</text>
<text x="351.1" y="121.7">D1</text>
<text x="351.1" y="124.2">D8</text>
<text x="104.2" y="129.9">L2</text>
<text x="104.2" y="127.4">T2</text>
<text x="305.5" y="126.7">L8</text>
<text x="351.1" y="126.7">E2</text>
<text x="351.1" y="129.3">E8</text>
<text x="351.2" y="131.8">F9</text>
<text x="104.1" y="135">K3</text>
<text x="104.2" y="137.5">L3</text>
<text x="104.2" y="132.5">J3</text>
<text x="351.1" y="134.4">G1</text>
<text x="351.1" y="136.9">G9</text>
<text x="104.1" y="140.1">K1</text>
</g>
<g font-size="1.8" fill="#006464">
<text x="109" y="67.5">A0</text>
<text x="109" y="70.1">A1</text>
<text x="143.6" y="67.5">DQ0</text>
<text x="143.6" y="70.1">DQ1</text>
<text x="310.3" y="69.4">Vdd</text>
<text x="310.3" y="72">Vdd</text>
<text x="339.8" y="72">NC/CKE1</text>
<text x="340" y="69.4">NC/ODT1</text>
<text x="109" y="75.2">A3</text>
<text x="109" y="72.6">A2</text>
<text x="109" y="77.7">A4</text>
<text x="143.6" y="72.6">DQ2</text>
<text x="143.6" y="75.2">DQ3</text>
<text x="143.6" y="77.7">DQ4</text>
<text x="310.3" y="74.5">Vdd</text>
<text x="310.3" y="77.1">Vdd</text>
<text x="341" y="77.1">NC/ZQ1</text>
<text x="341" y="74.5">NC/~{CS1}</text>
<text x="109" y="80.2">A5</text>
<text x="109" y="82.8">A6</text>
<text x="143.6" y="82.8">DQ6</text>
<text x="143.6" y="80.2">DQ5</text>
<text x="310.3" y="79.6">Vdd</text>
<text x="310.3" y="82.1">Vdd</text>
<text x="341.2" y="79.6">NC/A15</text>
<text x="109" y="85.3">A7</text>
<text x="109" y="87.9">A8</text>
<text x="143.6" y="87.9">DQ8</text>
<text x="143.6" y="85.3">DQ7</text>
<text x="238.8" y="89.1">GND</text>
<text x="310.3" y="84.7">Vdd</text>
<text x="310.3" y="87.2">Vdd</text>
<text x="310.3" y="89.8">Vdd</text>
<text x="345.5" y="84.7">Vss</text>
<text x="345.5" y="87.2">Vss</text>
<text x="345.5" y="89.8">Vss</text>
<text x="109" y="92.9">A10/AP</text>
<text x="109" y="90.4">A9</text>
<text x="109" y="95.5">A11</text>
<text x="142.4" y="95.5">DQ11</text>
<text x="142.4" y="92.9">DQ10</text>
<text x="143.6" y="90.4">DQ9</text>
<text x="310.3" y="94.8">VddQ</text>
<text x="345.5" y="92.3">Vss</text>
<text x="345.5" y="94.8">Vss</text>
<text x="109" y="98">A12/~{BC}</text>
<text x="109" y="100.6">A13</text>
<text x="142.4" y="100.6">DQ13</text>
<text x="142.4" y="98">DQ12</text>
<text x="310.3" y="97.4">VddQ</text>
<text x="310.3" y="99.9">VddQ</text>
<text x="345.5" y="97.4">Vss</text>
<text x="345.5" y="99.9">Vss</text>
<text x="109" y="103.1">A14</text>
<text x="142.4" y="105.6">DQ15</text>
<text x="142.4" y="103.1">DQ14</text>
<text x="310.3" y="102.5">VddQ</text>
<text x="310.3" y="105">VddQ</text>
<text x="310.3" y="107.5">VddQ</text>
<text x="345.5" y="102.5">Vss</text>
<text x="345.5" y="105">Vss</text>
<text x="345.5" y="107.5">Vss</text>
<text x="109" y="108.2">BA0</text>
<text x="109" y="113.3">BA2</text>
<text x="109" y="110.7">BA1</text>
<text x="143.3" y="113.3">UDM</text>
<text x="143.6" y="110.7">LDM</text>
<text x="247.6" y="111.9">GND</text>
<text x="310.3" y="110.1">VddQ</text>
<text x="310.3" y="112.6">VddQ</text>
<text x="345.5" y="110.1">Vss</text>
<text x="345.5" y="112.6">Vss</text>
<text x="109" y="118.3">CK+</text>
<text x="141" y="118.3">LDQS+</text>
<text x="310.3" y="115.2">VddQ</text>
<text x="344.2" y="117.7">VssQ</text>
<text x="109" y="120.9">CK-</text>
<text x="109" y="123.4">CKE</text>
<text x="140.7" y="126">UDQS-</text>
<text x="140.7" y="123.4">UDQS+</text>
<text x="141" y="120.9">LDQS-</text>
<text x="310.3" y="120.2">VrefDQ</text>
<text x="310.3" y="122.8">VrefCA</text>
<text x="344.2" y="120.2">VssQ</text>
<text x="344.2" y="122.8">VssQ</text>
<text x="344.2" y="125.3">VssQ</text>
<text x="109" y="131">~{CS}</text>
<text x="109" y="128.5">~{RESET}</text>
<text x="310.3" y="127.9">ZQ</text>
<text x="344.2" y="127.9">VssQ</text>
<text x="344.2" y="130.4">VssQ</text>
<text x="109" y="133.6">~{RAS}</text>
<text x="109" y="136.1">~{CAS}</text>
<text x="218.3" y="136.4">+3V3</text>
<text x="226.4" y="135.5">+1V35</text>
<text x="344.2" y="132.9">VssQ</text>
<text x="344.2" y="135.5">VssQ</text>
<text x="109" y="141.2">ODT</text>
<text x="109" y="138.7">~{WE}</text>
<text x="344.2" y="138">VssQ</text>
<text x="285.7" y="145">GND</text>
<text x="358.1" y="147.5">GND</text>
<text x="271.1" y="184.3">GND</text>
<text x="140.3" y="200.2">GND</text>
<text x="224.2" y="200.2">GND</text>
<text x="359.5" y="199.5">GND</text>
<text x="233" y="235.8">GND</text>
<text x="146" y="240.8">GND</text>
<text x="157.5" y="240.8">GND</text>
<text x="197.5" y="244">GND</text>
<text x="178.4" y="247.8">GND</text>
</g>
<g font-size="1.8" fill="#840084">
<text x="241.3" y="79.6">4u7</text>
<text x="250.2" y="79.6">470n</text>
<text x="257.8" y="79.6">470n</text>
<text x="265.4" y="79.6">470n</text>
<text x="273.1" y="79.6">470n</text>
<text x="280.7" y="79.6">470n</text>
<text x="288.3" y="79.6">470n</text>
<text x="250.2" y="102.5">470n</text>
<text x="257.8" y="102.5">470n</text>
<text x="265.4" y="102.5">470n</text>
<text x="273.1" y="102.5">470n</text>
<text x="280.7" y="102.5">470n</text>
<text x="288.3" y="102.5">470n</text>
<text x="279.4" y="132.9">100n</text>
<text x="288.3" y="132.9">100n</text>
<text x="298.3" y="134.3">240R</text>
<text x="274.8" y="164.8">1k</text>
<text x="274.8" y="174.9">1k</text>
<text x="340.2" y="195.9">70</text>
<text x="351.8" y="202.2">100n</text>
<text x="340.2" y="206">70</text>
</g>
<g font-size="1.8" fill="#0000c2">
<text x="181.6" y="171.2">Source:Trellis</text>
<text x="195.7" y="171.2">board</text>
</g>
<g font-size="1.8" fill="#0f0f0f">
<text x="136.2" y="178.2">DDR3_VTT</text>
<text x="218.4" y="178.2">VLDOIN</text>
<text x="215.6" y="222">DDR3_VTT</text>
</g>
<g font-size="1.8" fill="#aaa">
<text x="117.4" y="187.1">1</text>
<text x="117.4" y="189.6">2</text>
<text x="124.4" y="189.6">15</text>
<text x="124.4" y="187.1">16</text>
<text x="117.4" y="192.2">3</text>
<text x="117.4" y="194.7">4</text>
<text x="117.4" y="197.2">5</text>
<text x="124.4" y="197.2">12</text>
<text x="124.4" y="194.7">13</text>
<text x="124.4" y="192.2">14</text>
<text x="117.4" y="199.8">6</text>
<text x="117.4" y="202.3">7</text>
<text x="124.4" y="202.3">10</text>
<text x="124.4" y="199.8">11</text>
<text x="117.4" y="204.9">8</text>
<text x="125" y="204.9">9</text>
<text x="199.1" y="212.2" transform="rotate(-90 199.1 212.2)">2</text>
<text x="187.9" y="216.9">3</text>
<text x="187.9" y="219.5">9</text>
<text x="208.9" y="216.9">10</text>
<text x="209.5" y="222">5</text>
<text x="117.4" y="222.6">1</text>
<text x="117.4" y="225.2">2</text>
<text x="117.4" y="227.7">3</text>
<text x="124.4" y="227.7">14</text>
<text x="124.4" y="225.2">15</text>
<text x="124.4" y="222.6">16</text>
<text x="187.9" y="224.5">1</text>
<text x="187.9" y="227.1">6</text>
<text x="209.5" y="227.1">7</text>
<text x="117.4" y="230.3">4</text>
<text x="117.4" y="232.8">5</text>
<text x="124.4" y="232.8">12</text>
<text x="124.4" y="230.3">13</text>
<text x="199.1" y="233.8" transform="rotate(-90 199.1 233.8)">8</text>
<text x="117.4" y="235.3">6</text>
<text x="117.4" y="237.9">7</text>
<text x="124.4" y="237.9">10</text>
<text x="124.4" y="235.3">11</text>
<text x="117.4" y="240.4">8</text>
<text x="125" y="240.4">9</text>
<text x="117.4" y="258.2">1</text>
<text x="117.4" y="260.7">2</text>
<text x="117.4" y="263.3">3</text>
<text x="124.4" y="263.3">14</text>
<text x="124.4" y="260.7">15</text>
<text x="124.4" y="258.2">16</text>
<text x="117.4" y="265.8">4</text>
<text x="117.4" y="268.4">5</text>
<text x="124.4" y="268.4">12</text>
<text x="124.4" y="265.8">13</text>
<text x="117.4" y="270.9">6</text>
<text x="117.4" y="273.4">7</text>
<text x="117.4" y="276">8</text>
<text x="124.4" y="273.4">10</text>
<text x="124.4" y="270.9">11</text>
<text x="125" y="276">9</text>
</g>
<g font-size="1.8" fill="#a1a1a1">
<text x="163.2" y="188.8">10u</text>
<text x="170.8" y="188.8">10u</text>
<text x="178.4" y="188.8">10u</text>
<text x="206.4" y="188.8">100n</text>
<text x="214" y="188.8">100n</text>
<text x="161.2" y="211.8">15k</text>
<text x="177.7" y="214.9">15k</text>
<text x="155.1" y="226.9">15k</text>
<text x="235.6" y="226.9">4u7</text>
<text x="160" y="233.3">1n</text>
<text x="177.2" y="236.4">100n</text>
<text x="184.8" y="236.4">100n</text>
</g>
<g font-size="1.8" fill="#989898">
<text x="192.6" y="208.1">TPS51200DRC</text>
<text x="197.4" y="205.8">U10</text>
<text x="191" y="218">VO</text>
<text x="191" y="220.6">PGOOD</text>
<text x="200.3" y="220.7" transform="rotate(-90 200.3 220.7)">VLDOIN</text>
<text x="204.5" y="218">VIN</text>
<text x="191" y="225.7">REFIN</text>
<text x="201.4" y="223.1">VOSNS</text>
<text x="191" y="228.2">REFOUT</text>
<text x="200.3" y="230.6" transform="rotate(-90 200.3 230.6)">GND</text>
<text x="205.1" y="228.2">EN</text>
</g>
</g></defs>
<g fill="none" stroke="#840000" stroke-width=".18">
<path d="M10 10h400v277h-400zM12 12h396v273h-396zM60 10v2M110 10v2M160 10v2M210 10v2M260 10v2M310 10v2M360 10v2M10 60h2M240.7 72.4v2.8M240.7 77.2v2.8"/>
<path d="M272.4 72.4v2.8M272.4 77.2v2.8M408 60h2M240.7 83.8v1.3h1.2l-1.2 1.3-1.3-1.3h1.3M287.7 95.3v2.7M10 110h2M287.7 100.1v2.8M408 110h2M221 136.5l-.8 1.3M221 136.5v2.6M221 136.5l.7 1.3M229.2 136.5l-.7 1.3"/>
<path d="M229.2 136.5v2.6M229.2 136.5l.8 1.3M10 160h2M408 160h2M10 210h2M408 210h2M300 253h108v32h-108zM10 260h2M300 278.5h108M300 274.5h108M300 268.5h108M305.5 273.2v.2"/>
<path d="M305.5 272.5v.1M307.7 270.5v.2M307.7 269.8v.1M309.8 261.5v.2M309.8 260.8v.1M311.2 264.6h.6M311.2 263.8l.5-.1 .2 .3-.7 .2M313.7 264.1h1.1M318.1 269.1l-1.3 1.9M320 278.5v3M321.7 272.4l.4 .1M322.1 273.3l-.4 .1"/>
<path d="M322.7 272.5l.2-.1 .4 .1 .1 .9M322.7 271.9v1.5M326.4 260.3l-.5-.1-.2 .1v.5l.6 .2 .1 .4-.2 .3-.6-.1M330.2 263.8l-.4-.1-.3 .3v.4l.2 .2h.5M330.9 263.8l.4-.1 .2 .2M330.9 263.7v1M331.5 263.9l.2-.2 .4 .1 .1 .9M331.5 263.9v.8M342.5 279.7l.4-.4v1.5M343.9 279.4l.6-.1 .2 .1 .1 .3-.9 1.1h.9M384 278.5v6.5M408 260h2"/>
<path d="M60 285v2M110 285v2M160 285v2M210 285v2M260 285v2M300 281.5h108M310 285v2M340.7 280.2h1.2M342.5 280.8h.9M360 285v2M394.7 282.2l.6-.1 .2 .1 .1 .3-.9 1.1h.9"/>
</g>
<path d="M314.3 266.2v1.5M314.5 267.1l.4 .6M314.9 266.7l-.6 .6" fill="none" stroke="#840000" stroke-width=".3"/>
<path d="M149.9 223.8h5v2h-5z" fill="none" stroke="#a1a1a1" stroke-width=".25"/>
<path d="M148.6 224.8h1.3M154.9 224.8h1.3" fill="none" stroke="#a1a1a1" stroke-width=".18"/>
<path d="M148.6 223.6l7.6 2.3M156.2 223.6l-7.6 2.3" fill="none" stroke="#e65255" stroke-width=".46"/>
<path d="M238.6 77h4.1M238.6 75.4h4.1M270.4 77h4M270.4 75.4h4M285.6 99.8h4.1M285.6 98.3h4.1" fill="none" stroke="#840000" stroke-width=".51"/>
<path d="M277.5 78.5l.1 .2v.6M292.7 101.3l.2 .2v.7" fill="none" stroke="#840084" stroke-width=".18"/>
<path d="M222.5 134.8h.8l-.4 .5M223 135.3l.3 .2v.3l-.3 .3M231.9 134h.6M232 134.5h.3l.2 .2-.1 .5-.4 .1" fill="none" stroke="#006464" stroke-width=".18"/>
<path d="M118.7 257.2h6.4v20.3h-6.4z" fill="#f0f0f0"/>
<path d="M117.5 258.4h1.9l.4-.6 .6 1.2 .6-1.2 .7 1.2 .6-1.2 .6 1.2 .7-1.2 .4 .6h1M118.7 257.2h6.4v20.3h-6.4zM118.7 261h.7l.4-.7 .6 1.2 .6-1.2 .7 1.2 .6-1.2 .6 1.2 .7-1.2 .4 .7h1M118.7 276.2h.7l.4-.6 .6 1.1 .6-1.1 .7 1.1 .6-1.1 .6 1.1 .7-1.1 .4 .6h1M118.7 273.7h.7l.4-.7 .6 1.2 .6-1.2 .7 1.2 .6-1.2 .6 1.2 .7-1.2 .4 .7h1M118.7 271.1h.7l.4-.6 .6 1.2 .6-1.2 .7 1.2 .6-1.2 .6 1.2 .7-1.2 .4 .6h1M118.7 268.6h.7l.4-.6 .6 1.1 .6-1.1 .7 1.1 .6-1.1 .6 1.1 .7-1.1 .4 .6h1M118.7 266.1h.7l.4-.7 .6 1.2 .6-1.2 .7 1.2 .6-1.2 .6 1.2 .7-1.2 .4 .7h1M118.7 263.5h.7l.4-.6 .6 1.1 .6-1.1 .7 1.1 .6-1.1 .6 1.1 .7-1.1 .4 .6h1" fill="none" stroke="#a1a1a1" stroke-width=".18"/>
<path d="M126 270.7h.7" fill="none" stroke="#aaa" stroke-width=".18"/>
<path d="M130.3 254.6h.5l.1 1M130.9 254.9l-.5 .1a.3 .3 0 0 0-.2 .3 .3 .3 0 0 0 .2 .3l.5-.1M131.5 254.5l.4 1.1M131.9 255.6l-.2 .3-.2 .2M132.2 254.5l-.3 1.1" fill="none" stroke="#989898" stroke-width=".18"/>
<path d="M117.5 257.2l8.9 20.3M126.4 257.2l-8.9 20.3" fill="none" stroke="#e65255" stroke-width=".46"/>
<path d="M199.4 238.8v1.2h1.3l-1.3 1.3-1.3-1.3h1.3M180.3 242.6v1.2h1.3l-1.3 1.3-1.2-1.3h1.2" fill="none" stroke="#840000" stroke-width=".18"/>
<path d="M107.9 64.1h40.7v78.8h-40.7z" fill="#ffffc2"/>
<g fill="none" stroke="#840000" stroke-width=".18">
<path d="M102.9 66.7h5M102.9 71.8h5M102.9 69.2h5M102.9 74.3h5M102.9 76.8h5M102.9 79.4h5M107.9 64.1h40.7v78.8h-40.7zM148.6 66.7h5.1M148.6 71.8h5.1M148.6 69.2h5.1M148.6 74.3h5.1M148.6 76.8h5.1"/>
<path d="M148.6 79.4h5.1M102.9 99.7h5M102.9 97.2h5M102.9 94.6h5M102.9 89.5h5M102.9 92.1h5M102.9 87h5M102.9 81.9h5M102.9 84.5h5M148.6 99.7h5.1M148.6 97.2h5.1M148.6 94.6h5.1"/>
<path d="M148.6 89.5h5.1M148.6 92.1h5.1M148.6 87h5.1M148.6 81.9h5.1M148.6 84.5h5.1M102.9 102.2h5M102.9 112.4h5M102.9 109.9h5M102.9 117.5h5M102.9 107.3h5M148.6 104.8h5.1M148.6 102.2h5.1"/>
<path d="M148.6 112.4h5.1M148.6 109.9h5.1M148.6 117.5h5.1M102.9 122.6h5M102.9 120h5M102.9 132.7h5M102.9 135.3h5M102.9 130.2h5M102.9 137.8h5M102.9 127.6h5M148.6 125.1h5.1M148.6 122.6h5.1"/>
<path d="M148.6 120h5.1M102.9 140.3h5M148 235.6v1.3h1.2l-1.2 1.2-1.3-1.2h1.3M159.4 235.6v1.3h1.3l-1.3 1.2-1.3-1.2h1.3"/>
</g>
<path d="M130 66.5l.5-.1 .3 .3-.2 .6h-.6M130.6 65.8a.54 .54 0 0 0-.6 .4" fill="none" stroke="#840000" stroke-width=".19"/>
<path d="M135.9 61.3h.9l-.5 .5 .5 .2v.6l-.3 .2h-.4l-.2-.2M115.3 91.4h.5l.2 .2-.1 .4h-.6M109.2 131.7h3.3M109.2 134.2h3.3M109.2 126.6h5.5M111.9 120.1h1M146.2 125.2h1M146.2 120.1h1" fill="none" stroke="#006464" stroke-width=".18"/>
<path d="M118.7 221.6h6.4v20.3h-6.4z" fill="#f0f0f0"/>
<path d="M117.5 222.9h1.9l.4-.7 .6 1.2 .6-1.2 .7 1.2 .6-1.2 .6 1.2 .7-1.2 .4 .7h1M118.7 221.6h6.4v20.3h-6.4zM118.7 225.4h.7l.4-.6 .6 1.1 .6-1.1 .7 1.1 .6-1.1 .6 1.1 .7-1.1 .4 .6h1M118.7 238.1h.7l.4-.6 .6 1.1 .6-1.1 .7 1.1 .6-1.1 .6 1.1 .7-1.1 .4 .6h1M118.7 235.6h.7l.4-.7 .6 1.2 .6-1.2 .7 1.2 .6-1.2 .6 1.2 .7-1.2 .4 .7h1M118.7 233h.7l.4-.6 .6 1.2 .6-1.2 .7 1.2 .6-1.2 .6 1.2 .7-1.2 .4 .6h1M118.7 230.5h.7l.4-.6 .6 1.1 .6-1.1 .7 1.1 .6-1.1 .6 1.1 .7-1.1 .4 .6h1M118.7 228h.7l.4-.7 .6 1.2 .6-1.2 .7 1.2 .6-1.2 .6 1.2 .7-1.2 .4 .7h1M118.7 240.7h.7l.4-.7 .6 1.2 .6-1.2 .7 1.2 .6-1.2 .6 1.2 .7-1.2 .4 .7h1" fill="none" stroke="#a1a1a1" stroke-width=".18"/>
<path d="M126 235.2h.7" fill="none" stroke="#aaa" stroke-width=".18"/>
<path d="M130.3 219.1h.5l.1 .9M130.9 219.3l-.5 .1a.3 .3 0 0 0-.2 .3 .3 .3 0 0 0 .2 .3l.5-.1M131.5 219l.4 1M132.2 219l-.3 1M131.9 220l-.2 .4-.2 .1" fill="none" stroke="#989898" stroke-width=".18"/>
<path d="M117.5 221.6l8.9 20.3M126.4 221.6l-8.9 20.3" fill="none" stroke="#e65255" stroke-width=".46"/>
<path d="M142.2 194.9v1.3h1.3l-1.3 1.3-1.2-1.3h1.2" fill="none" stroke="#840000" stroke-width=".18"/>
<path d="M118.7 186.1h6.4v20.3h-6.4z" fill="#f0f0f0"/>
<g fill="none" stroke="#a1a1a1" stroke-width=".18">
<path d="M117.5 187.3h1.9l.4-.6 .6 1.1 .6-1.1 .7 1.1 .6-1.1 .6 1.1 .7-1.1 .4 .6h1M118.7 186.1h6.4v20.3h-6.4zM118.7 189.9h.7l.4-.7 .6 1.2 .6-1.2 .7 1.2 .6-1.2 .6 1.2 .7-1.2 .4 .7h1M118.7 197.5h.7l.4-.6 .6 1.1 .6-1.1 .7 1.1 .6-1.1 .6 1.1 .7-1.1 .4 .6h1M118.7 194.9h.7l.4-.6 .6 1.2 .6-1.2 .7 1.2 .6-1.2 .6 1.2 .7-1.2 .4 .6h1M118.7 192.4h.7l.4-.6 .6 1.1 .6-1.1 .7 1.1 .6-1.1 .6 1.1 .7-1.1 .4 .6h1M118.7 205.1h.7l.4-.6 .6 1.1 .6-1.1 .7 1.1 .6-1.1 .6 1.1 .7-1.1 .4 .6h1M118.7 202.6h.7l.4-.7 .6 1.2 .6-1.2 .7 1.2 .6-1.2 .6 1.2 .7-1.2 .4 .7h1M118.7 200h.7l.4-.6 .6 1.1 .6-1.1 .7 1.1 .6-1.1 .6 1.1 .7-1.1 .4 .6h1M159.4 205.7v1.3M159.4 212.1v1.3M175.9 208.9v1.3"/>
<path d="M175.9 215.3v1.2M234.9 219.7v2.8M159.4 226.1v2.8M159.4 230.9v2.8M176.5 229.2v2.8M176.5 234.1v2.8M181.6 235.3l.2 .2v.7M184.1 229.2v2.8M184.1 234.1v2.8M189.2 235.3l.2 .2v.7M234.9 224.5v2.8"/>
</g>
<path d="M126 199.6h.7" fill="none" stroke="#aaa" stroke-width=".18"/>
<path d="M130.3 183.5h.5l.1 .9M130.9 183.8l-.5 .1a.3 .3 0 0 0-.2 .3 .3 .3 0 0 0 .2 .2h.5M131.5 183.4l.4 1M131.9 184.4l-.2 .4-.2 .1M132.2 183.4l-.3 1M189.6 231.2h.9" fill="none" stroke="#989898" stroke-width=".18"/>
<g fill="none" stroke="#e65255" stroke-width=".46">
<path d="M117.5 186.1l8.9 20.3M126.4 186.1l-8.9 20.3M158.2 205.7l2.3 7.7M160.5 205.7l-2.3 7.7M174.8 208.9l2.2 7.6M177 208.9l-2.2 7.6M232.7 219.7l4.5 7.6M237.2 219.7l-4.5 7.6M157.1 226.1l4.6 7.6M161.7 226.1l-4.6 7.6M174.2 229.2l4.6 7.7M178.8 229.2l-4.6 7.7"/>
<path d="M181.9 229.2l4.5 7.7M186.4 229.2l-4.5 7.7"/>
</g>
<path d="M285.6 77h4.1M285.6 75.4h4.1" fill="none" stroke="#840000" stroke-width=".51"/>
<path d="M287.7 72.4v2.8M287.7 77.2v2.8M234.9 230.5v1.3h1.3l-1.3 1.2-1.2-1.2h1.2" fill="none" stroke="#840000" stroke-width=".18"/>
<path d="M292.7 78.5l.2 .2v.6" fill="none" stroke="#840084" stroke-width=".18"/>
<path d="M158.4 207h2v5.1h-2zM174.9 210.2h2v5.1h-2z" fill="none" stroke="#a1a1a1" stroke-width=".25"/>
<path d="M157.4 230.6h4M157.4 229.1h4M174.5 233.8h4.1M174.5 232.3h4.1M182.1 233.8h4.1M182.1 232.3h4.1M232.9 224.3h4.1M232.9 222.8h4.1" fill="none" stroke="#a1a1a1" stroke-width=".51"/>
<path d="M190.5 213.4h17.8v17.7h-17.8z" fill="#f0f0f0"/>
<path d="M190.5 213.4h17.8v17.7h-17.8z" fill="none" stroke="#a1a1a1" stroke-width=".25"/>
<g fill="none" stroke="#a1a1a1" stroke-width=".18">
<path d="M162.6 181.6v2.8M162.6 186.4v2.8M170.2 181.6v2.8M170.2 186.4v2.8M177.8 181.6v2.8M177.8 186.4v2.8M205.7 181.6v2.8M205.7 186.4v2.8M210.8 187.7l.2 .2v.6M213.4 181.6v2.8M213.4 186.4v2.8M218.4 187.7l.2 .2v.6"/>
<path d="M186.7 217.2h3.8M186.7 219.7h3.8M199.4 209.6v3.8M208.3 217.2h3.8M186.7 224.8h3.8M186.7 227.3h3.8M199.4 231.1v3.8M208.3 222.2h3.8M208.3 227.3h3.8"/>
</g>
<path d="M205.3 206.6h.3l.2 .1M205.8 207.7l-.2 .1h-.3" fill="none" stroke="#989898" stroke-width=".18"/>
<path d="M160.3 181.6l4.5 7.6M164.8 181.6l-4.5 7.6M167.9 181.6l4.6 7.6M172.5 181.6l-4.6 7.6M175.5 181.6l4.6 7.6M180.1 181.6l-4.6 7.6M203.5 181.6l4.5 7.6M208 181.6l-4.5 7.6M211.1 181.6l4.5 7.6M215.6 181.6l-4.5 7.6M186.7 209.5l25.4 25.5M212.1 209.5l-25.4 25.5" fill="none" stroke="#e65255" stroke-width=".46"/>
<path d="M249.6 72.4v2.8M249.6 77.2v2.8M226.1 194.9v1.3h1.2l-1.2 1.3-1.3-1.3h1.3M338.5 189.9v1.2M338.5 196.2v1.3M338.5 200v1.3M338.5 206.4v1.2" fill="none" stroke="#840000" stroke-width=".18"/>
<path d="M160.5 186.2h4.1M160.5 184.7h4.1M168.1 186.2h4.1M168.1 184.7h4.1M175.8 186.2h4M175.8 184.7h4M203.7 186.2h4.1M203.7 184.7h4.1M211.3 186.2h4.1M211.3 184.7h4.1" fill="none" stroke="#a1a1a1" stroke-width=".51"/>
<path d="M247.5 77h4.1M247.5 75.4h4.1" fill="none" stroke="#840000" stroke-width=".51"/>
<path d="M254.6 78.5l.2 .2v.6" fill="none" stroke="#840084" stroke-width=".18"/>
<path d="M337.4 191.1h2.1v5.1h-2.1zM337.4 201.3h2.1v5.1h-2.1z" fill="none" stroke="#840000" stroke-width=".25"/>
<path d="M309.2 66h40.7v73.7h-40.7z" fill="#ffffc2"/>
<g fill="none" stroke="#840000" stroke-width=".18">
<path d="M286.9 59.2h9.3l1 1.1-1 1.1h-9.3zM82.5 65.6h9.3l.9 1.1-.9 1.1h-9.3zM82.5 73.2h9.3l.9 1.1-.9 1.1h-9.3zM82.5 75.7h9.3l.9 1.1-.9 1.1h-9.3zM82.5 78.3h9.3l.9 1.1-.9 1.1h-9.3zM82.5 70.6h9.3l.9 1.2-.9 1.1h-9.3zM82.5 68.1h9.3l.9 1.1-.9 1.1h-9.3zM164.8 68.1h10.8l.9 1.1-.9 1.1h-10.8l-1-1.1zM164.8 70.6h10.8l.9 1.2-.9 1.1h-10.8l-1-1.1zM164.8 75.7h10.8l.9 1.1-.9 1.1h-10.8l-1-1.1zM164.8 65.6h10.8l.9 1.1-.9 1.1h-10.8l-1-1.1zM164.8 73.2h10.8l.9 1.1-.9 1.1h-10.8l-1-1.1z"/>
<path d="M164.8 78.3h10.8l.9 1.1-.9 1.1h-10.8l-1-1.1zM249.6 72.4v2.8M249.6 77.2v2.8M257.2 72.4v2.8M257.2 77.2v2.8M264.8 72.4v2.8M264.8 77.2v2.8M272.4 72.4v2.8M272.4 77.2v2.8M280 72.4v2.8M280 77.2v2.8M287.7 72.4v2.8"/>
<path d="M287.7 77.2v2.8M304.2 68.6h5M304.2 71.1h5M304.2 73.7h5M304.2 76.2h5M304.2 78.7h5M309.2 66h40.7v73.7h-40.7zM349.9 68.6h5.1M349.9 71.1h5.1M349.9 73.7h5.1M349.9 76.2h5.1M349.9 78.7h5.1"/>
<path d="M355.9 77.6h10.5v2.3h-10.5l-.9-1.2zM81.2 91h10.6l.9 1.1-.9 1.1h-10.6zM81.2 98.6h10.6l.9 1.1-.9 1.1h-10.6zM81.2 96h10.6l.9 1.2-.9 1.1h-10.6zM81.2 93.5h10.6l.9 1.1-.9 1.1h-10.6zM82.5 83.3h9.3l.9 1.2-.9 1.1h-9.3zM82.5 85.9h9.3l.9 1.1-.9 1.1h-9.3zM82.5 80.8h9.3l.9 1.1-.9 1.1h-9.3zM82.5 88.4h9.3l.9 1.1-.9 1.1h-9.3zM90.4 95.3h.7M164.8 83.3h10.8l.9 1.2-.9 1.1h-10.8l-1-1.1zM164.8 80.8h10.8l.9 1.1-.9 1.1h-10.8l-1-1.1z"/>
<path d="M164.8 85.9h10.8l.9 1.1-.9 1.1h-10.8l-1-1.1zM164.8 98.6h12l1 1.1-1 1.1h-12l-1-1.1zM164.8 96h12l1 1.2-1 1.1h-12l-1-1.1zM164.8 91h12l1 1.1-1 1.1h-12l-1-1.1zM164.8 93.5h12l1 1.1-1 1.1h-12l-1-1.1zM164.8 88.4h10.8l.9 1.1-.9 1.1h-10.8l-1-1.1zM175.2 95.3h.8M249.6 95.3v2.7M257.2 95.3v2.7M264.8 95.3v2.7M272.4 95.3v2.7M280 95.3v2.7"/>
<path d="M287.7 95.3v2.7M304.2 94h5M304.2 96.5h5M304.2 83.8h5M304.2 86.4h5M304.2 99.1h5M304.2 88.9h5M304.2 81.3h5M349.9 94h5.1M349.9 96.5h5.1M349.9 83.8h5.1M349.9 86.4h5.1"/>
<path d="M349.9 99.1h5.1M349.9 88.9h5.1M349.9 91.4h5.1M79.6 116.4h12.2l.9 1.1-.9 1.1h-12.2zM79.6 118.9h12.2l.9 1.1-.9 1.1h-12.2zM81.2 106.2h10.6l.9 1.1-.9 1.1h-10.6zM81.2 111.3h10.6l.9 1.1-.9 1.1h-10.6zM81.2 108.7h10.6l.9 1.2-.9 1.1h-10.6zM81.2 101.1h10.6l.9 1.1-.9 1.1h-10.6zM90.1 117.7h.9M90.4 110.5h.7M164.8 101.1h12l1 1.1-1 1.1h-12l-1-1.1z"/>
<path d="M164.8 103.7h12l1 1.1-1 1.1h-12l-1-1.1zM164.8 111.3h10.9l1 1.1-1 1.1h-10.9l-1-1.1zM164.8 108.7h10.9l1 1.2-1 1.1h-10.9l-1-1.1zM164.8 116.4h13.6l.9 1.1-.9 1.1h-13.6l-1-1.1zM164.8 118.9h13.6l.9 1.1-.9 1.1h-13.6l-1-1.1zM176.5 117.7h1M249.6 106.7v1.3h1.2l-1.2 1.2-1.3-1.2h1.3M249.6 100.1v2.8M257.2 100.1v2.8M264.8 100.1v2.8M272.4 100.1v2.8M280 100.1v2.8"/>
<path d="M287.7 100.1v2.8M304.2 119.4h5M304.2 101.6h5M304.2 104.1h5M304.2 106.7h5M304.2 109.2h5M304.2 111.8h5M304.2 114.3h5M349.9 116.8h5.1M349.9 119.4h5.1M349.9 101.6h5.1M349.9 104.1h5.1"/>
<path d="M349.9 106.7h5.1M349.9 109.2h5.1M349.9 111.8h5.1M79 126.5h12.8l.9 1.1-.9 1.1h-12.8zM81.1 121.4h10.7l.9 1.2-.9 1.1h-10.7zM81.2 131.6h10.6l.9 1.1-.9 1.1h-10.6zM81.2 139.2h10.6l.9 1.1-.9 1.1h-10.6zM81.2 134.1h10.6l.9 1.2-.9 1.1h-10.6zM82.2 136.7h9.6l.9 1.1-.9 1.1h-9.6zM82.3 129.1h9.5l.9 1.1-.9 1.1h-9.5zM90.1 120.2h.9M164.8 121.4h13.6l.9 1.2-.9 1.1h-13.6l-1-1.1z"/>
<path d="M164.8 124h13.6l.9 1.1-.9 1.1h-13.6l-1-1.1zM176.5 122.7h1M176.5 120.2h1M176.5 125.3h1M262.4 120.8h11.6l1 1.1-1 1.1h-11.6zM278.8 125.7v2.8M278.8 130.6v2.8M287.7 139.7v1.3h1.2l-1.2 1.2-1.3-1.2h1.3M287.7 125.7v2.8M287.7 130.6v2.8M296.5 128.3v1.2M296.5 134.6v1.3"/>
<path d="M304.2 121.9h5M304.2 127h5M349.9 121.9h5.1M349.9 124.5h5.1M349.9 127h5.1M349.9 129.5h5.1M349.9 132.1h5.1M349.9 134.6h5.1M349.9 137.2h5.1M219.9 142.6l1.1-1 1.1 1v8.1h-2.2zM228.1 142.6l1.1-1 1.1 1v9.3h-2.2zM271.9 145.9h2.3v9.4l-1.2 .9-1.1-.9z"/>
<path d="M273 158.8v1.2M360 142.2v1.3h1.3l-1.3 1.3-1.2-1.3h1.2M226.4 177.3h9.3v2.2h-9.3l-1-1.1zM257.3 166.5h11.6l1 1.1-1 1.2h-11.6zM273 179.1v1.2h1.3l-1.3 1.3-1.2-1.3h1.2M273 165.1v1.3M273 168.9v1.3M273 175.3v1.2M101.9 198.9h10.5v2.2h-10.5zM103.1 186.2h9.3v2.2h-9.3zM103.1 193.8h9.3v2.3h-9.3zM103.1 196.4h9.3v2.2h-9.3z"/>
<path d="M103.1 188.8h9.3v2.2h-9.3zM103.1 191.3h9.3v2.2h-9.3zM321.5 188.8h12.2l.9 1.1-.9 1.1h-12.2zM332 190.1h1M346.7 198.8h2.8M351.5 198.8h2.8M356.2 198.8h1.3v-1.3l1.3 1.3-1.3 1.2v-1.2M101.9 204h10.5v2.2h-10.5zM101.9 201.5h10.5v2.2h-10.5zM111 203.2h.7M146.5 202.1h9.4l.9 1.1-.9 1.1h-9.4zM165.5 202.1h8.2l.9 1.1-.9 1.1h-8.2z"/>
<path d="M237.8 207.2h8.2v2.2h-8.2l-.9-1.1zM321.5 206.5h12.2l.9 1.1-.9 1.2h-12.2zM332 207.8h1M101.7 239.6h10.7v2.2h-10.7zM101.8 234.5h10.6v2.2h-10.6zM101.9 231.9h10.5v2.3h-10.5zM101.9 237h10.5v2.2h-10.5zM103.1 229.4h9.3v2.2h-9.3zM103.1 226.9h9.3v2.2h-9.3zM103.1 221.8h9.3v2.2h-9.3zM103.1 224.3h9.3v2.2h-9.3zM111 236.3h.7"/>
<path d="M164.3 226.2h11.6v2.2h-11.6l-1-1.1zM216.9 226.2h13.4v2.2h-13.4l-1-1.1zM101.8 259.9h10.6v2.2h-10.6zM103.1 257.3h9.3v2.3h-9.3zM101.8 267.5h10.6v2.2h-10.6zM101.8 265h10.6v2.2h-10.6zM101.8 272.6h10.6v2.2h-10.6zM101.8 275.1h10.6v2.2h-10.6zM102.8 262.4h9.6v2.2h-9.6zM102.9 270h9.5v2.3h-9.5z"/>
</g>
<path d="M337.2 63.2h.9l-.5 .5 .5 .2v.6l-.3 .2h-.4l-.2-.2M345.2 72.6h3.4M347.8 69.2h.7M347.8 70.8l.4-.4v1.3M347.8 75.9l.4-.4v1.3M347.8 71.7h.7M347.8 76.8h.7M347.9 78h.6M347.9 78.6l.4-.1 .2 .3-.1 .5h-.5M347.9 68.2l.3-.3v1.3" fill="none" stroke="#006464" stroke-width=".18"/>
<path d="M295.5 129.5h2.1v5.1h-2.1zM272 170.2h2.1v5.1h-2.1zM272 160h2.1v5.1h-2.1z" fill="none" stroke="#840000" stroke-width=".25"/>
<g fill="none" stroke="#840000" stroke-width=".51">
<path d="M255.1 77h4.1M255.1 75.4h4.1M262.8 77h4M262.8 75.4h4M278 77h4.1M278 75.4h4.1M247.5 99.8h4.1M247.5 98.3h4.1M255.1 99.8h4.1M255.1 98.3h4.1M262.8 99.8h4M262.8 98.3h4"/>
<path d="M270.4 99.8h4M270.4 98.3h4M278 99.8h4.1M278 98.3h4.1M276.7 130.3h4.1M276.7 128.8h4.1M285.6 130.3h4.1M285.6 128.8h4.1M349.8 196.7v4.1M351.3 196.7v4.1"/>
</g>
<g fill="none" stroke="#840084" stroke-width=".18">
<path d="M254.6 78.5l.2 .2v.6M262.2 78.5l.2 .2v.6M269.8 78.5l.2 .2v.6M277.5 78.5l.1 .2v.6M285.1 78.5l.2 .2v.6M292.7 78.5l.2 .2v.6M254.6 101.3l.2 .2v.7M262.2 101.3l.2 .2v.7M269.8 101.3l.2 .2v.7M277.5 101.3l.1 .2v.7M285.1 101.3l.2 .2v.7M292.7 101.3l.2 .2v.7"/>
<path d="M283.8 131.8l.2 .2v.7M292.7 131.8l.2 .2v.7M356.2 201l.2 .2v.7"/>
</g>
<path d="M127.3 163.7l-.3-.1-.3 .3 .1 .2 .5 .1v.4h-.6M134 163.6v1.1M134.1 163.8l-.1 .1M193.3 169.8v.1M193.3 170.2v.8M194.3 170.3l-.3-.1-.2 .2 .1 .2 .4 .1v.3h-.5" fill="none" stroke="#0000c2" stroke-width=".18"/>
<path d="M91.4 165.7h158.8M250.2 165.7v113.7M91.4 279.4v-113.7M250.2 279.4h-158.8" fill="none" stroke="#0000c2" stroke-width=".18" stroke-dasharray="1.7 .6"/>
<g fill="none" stroke="#009600" stroke-width=".18">
<path d="M92.7 76.8h10.2M92.7 66.7h10.2M92.7 69.2h10.2M92.7 74.3h10.2M92.7 79.4h10.2M92.7 71.8h10.2M153.7 76.8h10.1M153.7 66.7h10.1M153.7 69.2h10.1M153.7 74.3h10.1M153.7 79.4h10.1M153.7 71.8h10.1"/>
<path d="M249.6 71.1v1.3M257.2 71.1v1.3M264.8 71.1v1.3M272.4 71.1v1.3M280 71.1v1.3M287.7 71.1v1.3M297.2 60.3h1.9v54h5.1M299.1 78.7h5.1M299.1 73.7h5.1M299.1 76.2h5.1M299.1 68.6h5.1M304.2 71.1h-63.5v1.3"/>
<path d="M92.7 94.6h10.2M92.7 99.7h10.2M92.7 97.2h10.2M92.7 92.1h10.2M92.7 87h10.2M92.7 89.5h10.2M92.7 84.5h10.2M92.7 81.9h10.2M153.7 94.6h10.1M153.7 99.7h10.1M153.7 97.2h10.1M153.7 92.1h10.1"/>
<path d="M153.7 87h10.1M153.7 89.5h10.1M153.7 84.5h10.1M153.7 81.9h10.1M240.7 80v3.8M249.6 80v1.3M257.2 80v1.3M257.2 94v1.3M264.8 80v1.3M264.8 94v1.3M272.4 80v1.3M272.4 94v1.3"/>
<path d="M280 80v1.3M280 94v1.3M287.7 80v1.3h-47M287.7 94v1.3M299.1 81.3h5.1M299.1 88.9h5.1M299.1 83.8h5.1M299.1 86.4h5.1M299.1 99.1h5.1M299.1 96.5h5.1M304.2 94h-54.6v1.3M355 94h5"/>
<path d="M355 88.9h5M355 83.8h5v58.4M355 86.4h5M355 99.1h5M355 96.5h5M355 91.4h5M92.7 117.5h10.2M92.7 102.2h10.2M92.7 112.4h10.2M92.7 107.3h10.2M92.7 109.9h10.2M153.7 117.5h10.1"/>
<path d="M153.7 104.8h10.1M153.7 102.2h10.1M153.7 112.4h10.1M153.7 109.9h10.1M249.6 102.9v3.8M257.2 102.9v1.2M264.8 102.9v1.2M272.4 102.9v1.2M280 102.9v1.2M287.7 102.9v1.2h-38.1M299.1 104.1h5.1M299.1 101.6h5.1"/>
<path d="M299.1 106.7h5.1M299.1 111.8h5.1M299.1 109.2h5.1M304.2 119.4h-2.6v2.5M355 104.1h5M355 101.6h5M355 106.7h5M355 111.8h5M355 109.2h5M355 116.8h5M355 119.4h5M92.7 132.7h10.2"/>
<path d="M92.7 127.6h10.2M92.7 122.6h10.2M92.7 120h10.2M92.7 130.2h10.2M92.7 137.8h10.2M92.7 135.3h10.2M153.7 122.6h10.1M153.7 125.1h10.1M153.7 120h10.1M221 139.1v2.5M229.2 139.1v2.5M275 121.9h29.2"/>
<path d="M278.8 121.9v3.8M278.8 133.4v3.8h17.7v-1.3M287.7 121.9v3.8M287.7 133.4v6.3M304.2 127h-7.7v1.3M355 124.5h5M355 121.9h5M355 127h5M355 137.2h5M355 132.1h5M355 134.6h5M355 129.5h5"/>
<path d="M92.7 140.3h10.2M273 156.2v2.6M162.6 178.4v3.2M170.2 178.4v3.2M177.8 178.4v3.2M205.7 178.4v3.2M213.4 178.4v3.2M225.4 178.4h-26v31.2M269.9 167.6h3.1M273 166.4v2.5M273 176.5v2.6M112.4 194.9h5.1"/>
<path d="M112.4 189.9h5.1M112.4 197.5h5.1M112.4 187.3h5.1M112.4 192.4h5.1M126.4 194.9h3.8M126.4 189.9h3.8M126.4 197.5h3.8M126.4 187.3h3.8M126.4 192.4h3.8M162.6 189.2v1.9M170.2 189.2v1.9M177.8 189.2v1.9h-35.6v3.8"/>
<path d="M205.7 189.2v1.9h20.4v3.8M213.4 189.2v1.9M334.6 189.9h3.9M338.5 197.5v2.5M338.5 198.8h8.2M354.3 198.8h1.9M112.4 202.6h5.1M112.4 200h5.1M112.4 205.1h5.1M126.4 202.6h3.8M126.4 200h3.8M126.4 205.1h3.8"/>
<path d="M156.8 203.2h2.6v2.5M159.4 213.4v12.7M174.6 203.2h1.3v5.7M175.9 216.5v3.2h10.8M186.7 217.2v-38.8h-56.5v97.8h-3.8M212.1 217.2h22.8M236.9 208.3h-2v11.4M334.6 207.6h3.9M112.4 222.9h5.1M112.4 233h5.1M112.4 238.1h5.1M112.4 225.4h5.1"/>
<path d="M112.4 228h5.1M112.4 230.5h5.1M112.4 235.6h5.1M126.4 222.9h3.8M126.4 233h3.8M126.4 238.1h3.8M126.4 225.4h3.8M126.4 228h3.8M126.4 230.5h3.8M126.4 235.6h3.8M148.6 224.8h-.6v10.8M156.2 224.8h30.5"/>
<path d="M159.4 233.7v1.9M175.9 227.3h10.8M176.5 236.9v1.9h7.6v-1.9M176.5 227.3v1.9M180.3 238.8v3.8M184.1 227.3v1.9M199.4 234.9v3.9M212.1 227.3h3.8M212.1 222.2h12.7M234.9 227.3v3.2M112.4 240.7h5.1M112.4 258.4h5.1"/>
<path d="M126.4 240.7h3.8M126.4 258.4h3.8M112.4 263.5h5.1M112.4 261h5.1M112.4 276.2h5.1M112.4 268.6h5.1M112.4 273.7h5.1M112.4 271.1h5.1M112.4 266.1h5.1M126.4 263.5h3.8M126.4 261h3.8M126.4 268.6h3.8"/>
<path d="M126.4 273.7h3.8M126.4 271.1h3.8M126.4 266.1h3.8"/>
</g>
<path d="M354.4 75.6l1.2 1.2M354.4 70.5l1.2 1.2M354.4 68l1.2 1.2M354.4 73.1l1.2 1.2M355.6 75.6l-1.2 1.2M355.6 70.5l-1.2 1.2M355.6 68l-1.2 1.2M355.6 73.1l-1.2 1.2" fill="none" stroke="#000084" stroke-width=".18"/>
<path d="M205.3 206.6h.3l.2 .1M205.8 207.7l-.2 .1h-.3M189.6 231.2h.9" fill="none" stroke="#989898" stroke-width=".18"/>
<g fill="none" stroke="#a1a1a1" stroke-width=".18">
<path d="M162.6 181.6v2.8M162.6 186.4v2.8M170.2 181.6v2.8M170.2 186.4v2.8M177.8 181.6v2.8M177.8 186.4v2.8M205.7 181.6v2.8M205.7 186.4v2.8M210.8 187.7l.2 .2v.6M213.4 181.6v2.8M213.4 186.4v2.8M218.4 187.7l.2 .2v.6"/>
<path d="M186.7 217.2h3.8M186.7 219.7h3.8M199.4 209.6v3.8M208.3 217.2h3.8M148.6 224.8h1.3M154.9 224.8h1.3M159.4 226.1v2.8M159.4 230.9v2.8M176.5 229.2v2.8M176.5 234.1v2.8M181.6 235.3l.2 .2v.7M184.1 229.2v2.8"/>
<path d="M184.1 234.1v2.8M186.7 224.8h3.8M186.7 227.3h3.8M189.2 235.3l.2 .2v.7M199.4 231.1v3.8M208.3 222.2h3.8M208.3 227.3h3.8"/>
</g>
<g fill="none" stroke="#e65255" stroke-width=".46">
<path d="M160.3 181.6l4.5 7.6M164.8 181.6l-4.5 7.6M167.9 181.6l4.6 7.6M172.5 181.6l-4.6 7.6M175.5 181.6l4.6 7.6M180.1 181.6l-4.6 7.6M203.5 181.6l4.5 7.6M208 181.6l-4.5 7.6M211.1 181.6l4.5 7.6M215.6 181.6l-4.5 7.6M186.7 209.5l25.4 25.5M212.1 209.5l-25.4 25.5"/>
<path d="M148.6 223.6l7.6 2.3M156.2 223.6l-7.6 2.3M157.1 226.1l4.6 7.6M161.7 226.1l-4.6 7.6M174.2 229.2l4.6 7.7M178.8 229.2l-4.6 7.7M181.9 229.2l4.5 7.7M186.4 229.2l-4.5 7.7"/>
</g>
<g fill="#009600" stroke="#009600" stroke-width=".18">
<circle cx="170.2" cy="191.1" r=".46"/>
<circle cx="162.6" cy="191.1" r=".46"/>
<circle cx="205.7" cy="178.4" r=".46"/>
<circle cx="213.4" cy="178.4" r=".46"/>
<circle cx="234.9" cy="217.2" r=".46"/>
<circle cx="170.2" cy="178.4" r=".46"/>
<circle cx="213.4" cy="191.1" r=".46"/>
<circle cx="130.2" cy="192.4" r=".46"/>
<circle cx="130.2" cy="197.5" r=".46"/>
<circle cx="130.2" cy="194.9" r=".46"/>
<circle cx="130.2" cy="189.9" r=".46"/>
<circle cx="130.2" cy="240.7" r=".46"/>
<circle cx="130.2" cy="238.1" r=".46"/>
<circle cx="130.2" cy="258.4" r=".46"/>
<circle cx="130.2" cy="268.6" r=".46"/>
<circle cx="130.2" cy="273.7" r=".46"/>
<circle cx="130.2" cy="266.1" r=".46"/>
<circle cx="130.2" cy="263.5" r=".46"/>
<circle cx="130.2" cy="261" r=".46"/>
<circle cx="130.2" cy="202.6" r=".46"/>
<circle cx="130.2" cy="200" r=".46"/>
<circle cx="130.2" cy="205.1" r=".46"/>
<circle cx="130.2" cy="271.1" r=".46"/>
<circle cx="130.2" cy="235.6" r=".46"/>
<circle cx="130.2" cy="233" r=".46"/>
<circle cx="130.2" cy="230.5" r=".46"/>
<circle cx="130.2" cy="228" r=".46"/>
<circle cx="130.2" cy="222.9" r=".46"/>
<circle cx="130.2" cy="225.4" r=".46"/>
<circle cx="180.3" cy="238.8" r=".46"/>
<circle cx="184.1" cy="227.3" r=".46"/>
<circle cx="177.8" cy="178.4" r=".46"/>
<circle cx="176.5" cy="227.3" r=".46"/>
<circle cx="287.7" cy="94" r=".46"/>
<circle cx="299.1" cy="94" r=".46"/>
<circle cx="299.1" cy="104.1" r=".46"/>
<circle cx="299.1" cy="106.7" r=".46"/>
<circle cx="299.1" cy="96.5" r=".46"/>
<circle cx="299.1" cy="101.6" r=".46"/>
<circle cx="299.1" cy="99.1" r=".46"/>
<circle cx="257.2" cy="104.1" r=".46"/>
<circle cx="249.6" cy="104.1" r=".46"/>
<circle cx="280" cy="71.1" r=".46"/>
<circle cx="272.4" cy="71.1" r=".46"/>
<circle cx="264.8" cy="71.1" r=".46"/>
<circle cx="272.4" cy="81.3" r=".46"/>
<circle cx="264.8" cy="94" r=".46"/>
<circle cx="264.8" cy="81.3" r=".46"/>
<circle cx="257.2" cy="94" r=".46"/>
<circle cx="360" cy="116.8" r=".46"/>
<circle cx="360" cy="127" r=".46"/>
<circle cx="360" cy="119.4" r=".46"/>
<circle cx="360" cy="121.9" r=".46"/>
<circle cx="360" cy="124.5" r=".46"/>
<circle cx="360" cy="101.6" r=".46"/>
<circle cx="360" cy="99.1" r=".46"/>
<circle cx="360" cy="106.7" r=".46"/>
<circle cx="360" cy="109.2" r=".46"/>
<circle cx="360" cy="104.1" r=".46"/>
<circle cx="360" cy="132.1" r=".46"/>
<circle cx="360" cy="134.6" r=".46"/>
<circle cx="360" cy="129.5" r=".46"/>
<circle cx="360" cy="137.2" r=".46"/>
<circle cx="338.5" cy="198.8" r=".46"/>
<circle cx="360" cy="94" r=".46"/>
<circle cx="360" cy="88.9" r=".46"/>
<circle cx="360" cy="91.4" r=".46"/>
<circle cx="299.1" cy="88.9" r=".46"/>
<circle cx="299.1" cy="86.4" r=".46"/>
<circle cx="360" cy="96.5" r=".46"/>
<circle cx="360" cy="86.4" r=".46"/>
<circle cx="301.6" cy="121.9" r=".46"/>
<circle cx="299.1" cy="111.8" r=".46"/>
<circle cx="360" cy="111.8" r=".46"/>
<circle cx="278.8" cy="121.9" r=".46"/>
<circle cx="287.7" cy="121.9" r=".46"/>
<circle cx="287.7" cy="137.2" r=".46"/>
<circle cx="299.1" cy="109.2" r=".46"/>
<circle cx="299.1" cy="81.3" r=".46"/>
<circle cx="299.1" cy="83.8" r=".46"/>
<circle cx="299.1" cy="76.2" r=".46"/>
<circle cx="299.1" cy="71.1" r=".46"/>
<circle cx="299.1" cy="73.7" r=".46"/>
<circle cx="299.1" cy="78.7" r=".46"/>
<circle cx="287.7" cy="71.1" r=".46"/>
<circle cx="280" cy="81.3" r=".46"/>
<circle cx="299.1" cy="68.6" r=".46"/>
<circle cx="280" cy="94" r=".46"/>
<circle cx="280" cy="104.1" r=".46"/>
<circle cx="272.4" cy="94" r=".46"/>
<circle cx="272.4" cy="104.1" r=".46"/>
<circle cx="264.8" cy="104.1" r=".46"/>
<circle cx="273" cy="167.6" r=".46"/>
<circle cx="159.4" cy="224.8" r=".46"/>
<circle cx="162.6" cy="178.4" r=".46"/>
<circle cx="257.2" cy="71.1" r=".46"/>
<circle cx="257.2" cy="81.3" r=".46"/>
<circle cx="249.6" cy="71.1" r=".46"/>
<circle cx="240.7" cy="81.3" r=".46"/>
<circle cx="249.6" cy="81.3" r=".46"/>
<circle cx="130.2" cy="187.3" r=".46"/>
</g>
<use href="#words"/>
</svg>
